VERSION 5.8 ;
BUSBITCHARS "[]" ;
DIVIDERCHAR "/" ;
UNITS
    DATABASE MICRONS 1000 ;
END UNITS

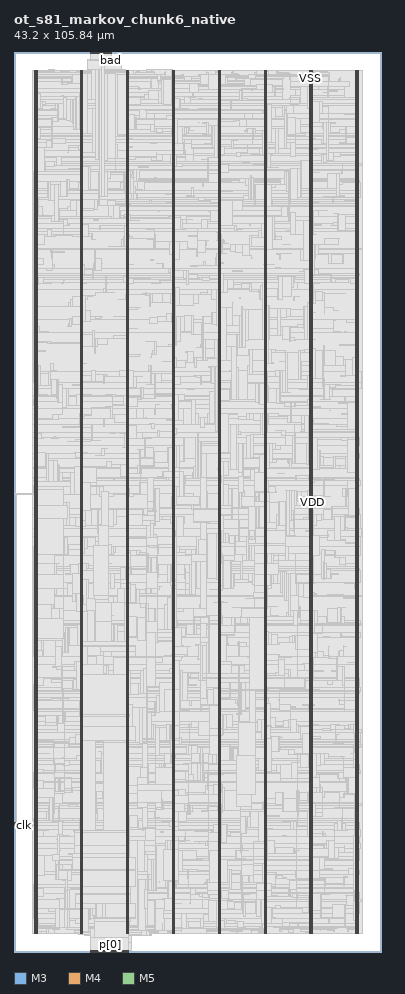
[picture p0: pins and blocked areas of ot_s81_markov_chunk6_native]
MACRO ot_s81_markov_chunk6_native
  FOREIGN ot_s81_markov_chunk6_native 0 0 ;
  CLASS BLOCK ;
  SIZE 43.2 BY 105.84 ;
  PIN bad
    DIRECTION OUTPUT ;
    USE SIGNAL ;
    PORT
      LAYER M3 ;
        RECT  11.448 105.696 11.466 105.84 ;
    END
  END bad
  PIN clk
    DIRECTION INPUT ;
    USE SIGNAL ;
    PORT
      LAYER M4 ;
        RECT  0 14.88 0.192 14.904 ;
    END
  END clk
  PIN p[0]
    DIRECTION INPUT ;
    USE SIGNAL ;
    PORT
      LAYER M3 ;
        RECT  11.304 0 11.322 0.144 ;
    END
  END p[0]
  PIN p[10]
    DIRECTION INPUT ;
    USE SIGNAL ;
    PORT
      LAYER M3 ;
        RECT  12.024 0 12.042 0.144 ;
    END
  END p[10]
  PIN p[11]
    DIRECTION INPUT ;
    USE SIGNAL ;
    PORT
      LAYER M5 ;
        RECT  12.048 0 12.072 0.192 ;
    END
  END p[11]
  PIN p[12]
    DIRECTION INPUT ;
    USE SIGNAL ;
    PORT
      LAYER M3 ;
        RECT  12.168 0 12.186 0.144 ;
    END
  END p[12]
  PIN p[13]
    DIRECTION INPUT ;
    USE SIGNAL ;
    PORT
      LAYER M5 ;
        RECT  12.192 0 12.216 0.192 ;
    END
  END p[13]
  PIN p[14]
    DIRECTION INPUT ;
    USE SIGNAL ;
    PORT
      LAYER M3 ;
        RECT  12.312 0 12.33 0.144 ;
    END
  END p[14]
  PIN p[15]
    DIRECTION INPUT ;
    USE SIGNAL ;
    PORT
      LAYER M5 ;
        RECT  12.336 0 12.36 0.192 ;
    END
  END p[15]
  PIN p[16]
    DIRECTION INPUT ;
    USE SIGNAL ;
    PORT
      LAYER M3 ;
        RECT  12.456 0 12.474 0.144 ;
    END
  END p[16]
  PIN p[17]
    DIRECTION INPUT ;
    USE SIGNAL ;
    PORT
      LAYER M5 ;
        RECT  12.48 0 12.504 0.192 ;
    END
  END p[17]
  PIN p[18]
    DIRECTION INPUT ;
    USE SIGNAL ;
    PORT
      LAYER M3 ;
        RECT  12.6 0 12.618 0.144 ;
    END
  END p[18]
  PIN p[19]
    DIRECTION INPUT ;
    USE SIGNAL ;
    PORT
      LAYER M5 ;
        RECT  12.624 0 12.648 0.192 ;
    END
  END p[19]
  PIN p[1]
    DIRECTION INPUT ;
    USE SIGNAL ;
    PORT
      LAYER M5 ;
        RECT  11.328 0 11.352 0.192 ;
    END
  END p[1]
  PIN p[20]
    DIRECTION INPUT ;
    USE SIGNAL ;
    PORT
      LAYER M3 ;
        RECT  12.744 0 12.762 0.144 ;
    END
  END p[20]
  PIN p[21]
    DIRECTION INPUT ;
    USE SIGNAL ;
    PORT
      LAYER M5 ;
        RECT  12.768 0 12.792 0.192 ;
    END
  END p[21]
  PIN p[22]
    DIRECTION INPUT ;
    USE SIGNAL ;
    PORT
      LAYER M3 ;
        RECT  12.888 0 12.906 0.144 ;
    END
  END p[22]
  PIN p[23]
    DIRECTION INPUT ;
    USE SIGNAL ;
    PORT
      LAYER M5 ;
        RECT  12.912 0 12.936 0.192 ;
    END
  END p[23]
  PIN p[24]
    DIRECTION INPUT ;
    USE SIGNAL ;
    PORT
      LAYER M3 ;
        RECT  13.032 0 13.05 0.144 ;
    END
  END p[24]
  PIN p[25]
    DIRECTION INPUT ;
    USE SIGNAL ;
    PORT
      LAYER M5 ;
        RECT  13.056 0 13.08 0.192 ;
    END
  END p[25]
  PIN p[26]
    DIRECTION INPUT ;
    USE SIGNAL ;
    PORT
      LAYER M3 ;
        RECT  13.176 0 13.194 0.144 ;
    END
  END p[26]
  PIN p[27]
    DIRECTION INPUT ;
    USE SIGNAL ;
    PORT
      LAYER M5 ;
        RECT  13.2 0 13.224 0.192 ;
    END
  END p[27]
  PIN p[28]
    DIRECTION INPUT ;
    USE SIGNAL ;
    PORT
      LAYER M3 ;
        RECT  13.32 0 13.338 0.144 ;
    END
  END p[28]
  PIN p[29]
    DIRECTION INPUT ;
    USE SIGNAL ;
    PORT
      LAYER M5 ;
        RECT  13.344 0 13.368 0.192 ;
    END
  END p[29]
  PIN p[2]
    DIRECTION INPUT ;
    USE SIGNAL ;
    PORT
      LAYER M3 ;
        RECT  11.448 0 11.466 0.144 ;
    END
  END p[2]
  PIN p[30]
    DIRECTION INPUT ;
    USE SIGNAL ;
    PORT
      LAYER M3 ;
        RECT  13.464 0 13.482 0.144 ;
    END
  END p[30]
  PIN p[31]
    DIRECTION INPUT ;
    USE SIGNAL ;
    PORT
      LAYER M5 ;
        RECT  13.488 0 13.512 0.192 ;
    END
  END p[31]
  PIN p[3]
    DIRECTION INPUT ;
    USE SIGNAL ;
    PORT
      LAYER M5 ;
        RECT  11.472 0 11.496 0.192 ;
    END
  END p[3]
  PIN p[4]
    DIRECTION INPUT ;
    USE SIGNAL ;
    PORT
      LAYER M3 ;
        RECT  11.592 0 11.61 0.144 ;
    END
  END p[4]
  PIN p[5]
    DIRECTION INPUT ;
    USE SIGNAL ;
    PORT
      LAYER M5 ;
        RECT  11.616 0 11.64 0.192 ;
    END
  END p[5]
  PIN p[6]
    DIRECTION INPUT ;
    USE SIGNAL ;
    PORT
      LAYER M3 ;
        RECT  11.736 0 11.754 0.144 ;
    END
  END p[6]
  PIN p[7]
    DIRECTION INPUT ;
    USE SIGNAL ;
    PORT
      LAYER M5 ;
        RECT  11.76 0 11.784 0.192 ;
    END
  END p[7]
  PIN p[8]
    DIRECTION INPUT ;
    USE SIGNAL ;
    PORT
      LAYER M3 ;
        RECT  11.88 0 11.898 0.144 ;
    END
  END p[8]
  PIN p[9]
    DIRECTION INPUT ;
    USE SIGNAL ;
    PORT
      LAYER M5 ;
        RECT  11.904 0 11.928 0.192 ;
    END
  END p[9]
  PIN rst_n
    DIRECTION INPUT ;
    USE SIGNAL ;
    PORT
      LAYER M4 ;
        RECT  0 15.024 0.192 15.048 ;
    END
  END rst_n
  PIN sum[0]
    DIRECTION INPUT ;
    USE SIGNAL ;
    PORT
      LAYER M3 ;
        RECT  9 0 9.018 0.144 ;
    END
  END sum[0]
  PIN sum[10]
    DIRECTION INPUT ;
    USE SIGNAL ;
    PORT
      LAYER M3 ;
        RECT  9.72 0 9.738 0.144 ;
    END
  END sum[10]
  PIN sum[11]
    DIRECTION INPUT ;
    USE SIGNAL ;
    PORT
      LAYER M5 ;
        RECT  9.744 0 9.768 0.192 ;
    END
  END sum[11]
  PIN sum[12]
    DIRECTION INPUT ;
    USE SIGNAL ;
    PORT
      LAYER M3 ;
        RECT  9.864 0 9.882 0.144 ;
    END
  END sum[12]
  PIN sum[13]
    DIRECTION INPUT ;
    USE SIGNAL ;
    PORT
      LAYER M5 ;
        RECT  9.888 0 9.912 0.192 ;
    END
  END sum[13]
  PIN sum[14]
    DIRECTION INPUT ;
    USE SIGNAL ;
    PORT
      LAYER M3 ;
        RECT  10.008 0 10.026 0.144 ;
    END
  END sum[14]
  PIN sum[15]
    DIRECTION INPUT ;
    USE SIGNAL ;
    PORT
      LAYER M5 ;
        RECT  10.032 0 10.056 0.192 ;
    END
  END sum[15]
  PIN sum[16]
    DIRECTION INPUT ;
    USE SIGNAL ;
    PORT
      LAYER M3 ;
        RECT  10.152 0 10.17 0.144 ;
    END
  END sum[16]
  PIN sum[17]
    DIRECTION INPUT ;
    USE SIGNAL ;
    PORT
      LAYER M5 ;
        RECT  10.176 0 10.2 0.192 ;
    END
  END sum[17]
  PIN sum[18]
    DIRECTION INPUT ;
    USE SIGNAL ;
    PORT
      LAYER M3 ;
        RECT  10.296 0 10.314 0.144 ;
    END
  END sum[18]
  PIN sum[19]
    DIRECTION INPUT ;
    USE SIGNAL ;
    PORT
      LAYER M5 ;
        RECT  10.32 0 10.344 0.192 ;
    END
  END sum[19]
  PIN sum[1]
    DIRECTION INPUT ;
    USE SIGNAL ;
    PORT
      LAYER M5 ;
        RECT  9.024 0 9.048 0.192 ;
    END
  END sum[1]
  PIN sum[20]
    DIRECTION INPUT ;
    USE SIGNAL ;
    PORT
      LAYER M3 ;
        RECT  10.44 0 10.458 0.144 ;
    END
  END sum[20]
  PIN sum[21]
    DIRECTION INPUT ;
    USE SIGNAL ;
    PORT
      LAYER M5 ;
        RECT  10.464 0 10.488 0.192 ;
    END
  END sum[21]
  PIN sum[22]
    DIRECTION INPUT ;
    USE SIGNAL ;
    PORT
      LAYER M3 ;
        RECT  10.584 0 10.602 0.144 ;
    END
  END sum[22]
  PIN sum[23]
    DIRECTION INPUT ;
    USE SIGNAL ;
    PORT
      LAYER M5 ;
        RECT  10.608 0 10.632 0.192 ;
    END
  END sum[23]
  PIN sum[24]
    DIRECTION INPUT ;
    USE SIGNAL ;
    PORT
      LAYER M3 ;
        RECT  10.728 0 10.746 0.144 ;
    END
  END sum[24]
  PIN sum[25]
    DIRECTION INPUT ;
    USE SIGNAL ;
    PORT
      LAYER M5 ;
        RECT  10.752 0 10.776 0.192 ;
    END
  END sum[25]
  PIN sum[26]
    DIRECTION INPUT ;
    USE SIGNAL ;
    PORT
      LAYER M3 ;
        RECT  10.872 0 10.89 0.144 ;
    END
  END sum[26]
  PIN sum[27]
    DIRECTION INPUT ;
    USE SIGNAL ;
    PORT
      LAYER M5 ;
        RECT  10.896 0 10.92 0.192 ;
    END
  END sum[27]
  PIN sum[28]
    DIRECTION INPUT ;
    USE SIGNAL ;
    PORT
      LAYER M3 ;
        RECT  11.016 0 11.034 0.144 ;
    END
  END sum[28]
  PIN sum[29]
    DIRECTION INPUT ;
    USE SIGNAL ;
    PORT
      LAYER M5 ;
        RECT  11.04 0 11.064 0.192 ;
    END
  END sum[29]
  PIN sum[2]
    DIRECTION INPUT ;
    USE SIGNAL ;
    PORT
      LAYER M3 ;
        RECT  9.144 0 9.162 0.144 ;
    END
  END sum[2]
  PIN sum[30]
    DIRECTION INPUT ;
    USE SIGNAL ;
    PORT
      LAYER M3 ;
        RECT  11.16 0 11.178 0.144 ;
    END
  END sum[30]
  PIN sum[31]
    DIRECTION INPUT ;
    USE SIGNAL ;
    PORT
      LAYER M5 ;
        RECT  11.184 0 11.208 0.192 ;
    END
  END sum[31]
  PIN sum[3]
    DIRECTION INPUT ;
    USE SIGNAL ;
    PORT
      LAYER M5 ;
        RECT  9.168 0 9.192 0.192 ;
    END
  END sum[3]
  PIN sum[4]
    DIRECTION INPUT ;
    USE SIGNAL ;
    PORT
      LAYER M3 ;
        RECT  9.288 0 9.306 0.144 ;
    END
  END sum[4]
  PIN sum[5]
    DIRECTION INPUT ;
    USE SIGNAL ;
    PORT
      LAYER M5 ;
        RECT  9.312 0 9.336 0.192 ;
    END
  END sum[5]
  PIN sum[6]
    DIRECTION INPUT ;
    USE SIGNAL ;
    PORT
      LAYER M3 ;
        RECT  9.432 0 9.45 0.144 ;
    END
  END sum[6]
  PIN sum[7]
    DIRECTION INPUT ;
    USE SIGNAL ;
    PORT
      LAYER M5 ;
        RECT  9.456 0 9.48 0.192 ;
    END
  END sum[7]
  PIN sum[8]
    DIRECTION INPUT ;
    USE SIGNAL ;
    PORT
      LAYER M3 ;
        RECT  9.576 0 9.594 0.144 ;
    END
  END sum[8]
  PIN sum[9]
    DIRECTION INPUT ;
    USE SIGNAL ;
    PORT
      LAYER M5 ;
        RECT  9.6 0 9.624 0.192 ;
    END
  END sum[9]
  PIN vin
    DIRECTION INPUT ;
    USE SIGNAL ;
    PORT
      LAYER M4 ;
        RECT  0 15.168 0.192 15.192 ;
    END
  END vin
  PIN vout
    DIRECTION OUTPUT ;
    USE SIGNAL ;
    PORT
      LAYER M3 ;
        RECT  11.304 105.696 11.322 105.84 ;
    END
  END vout
  PIN y[0]
    DIRECTION OUTPUT ;
    USE SIGNAL ;
    PORT
      LAYER M3 ;
        RECT  9 105.696 9.018 105.84 ;
    END
  END y[0]
  PIN y[10]
    DIRECTION OUTPUT ;
    USE SIGNAL ;
    PORT
      LAYER M3 ;
        RECT  9.72 105.696 9.738 105.84 ;
    END
  END y[10]
  PIN y[11]
    DIRECTION OUTPUT ;
    USE SIGNAL ;
    PORT
      LAYER M5 ;
        RECT  9.744 105.648 9.768 105.84 ;
    END
  END y[11]
  PIN y[12]
    DIRECTION OUTPUT ;
    USE SIGNAL ;
    PORT
      LAYER M3 ;
        RECT  9.864 105.696 9.882 105.84 ;
    END
  END y[12]
  PIN y[13]
    DIRECTION OUTPUT ;
    USE SIGNAL ;
    PORT
      LAYER M5 ;
        RECT  9.888 105.648 9.912 105.84 ;
    END
  END y[13]
  PIN y[14]
    DIRECTION OUTPUT ;
    USE SIGNAL ;
    PORT
      LAYER M3 ;
        RECT  10.008 105.696 10.026 105.84 ;
    END
  END y[14]
  PIN y[15]
    DIRECTION OUTPUT ;
    USE SIGNAL ;
    PORT
      LAYER M5 ;
        RECT  10.032 105.648 10.056 105.84 ;
    END
  END y[15]
  PIN y[16]
    DIRECTION OUTPUT ;
    USE SIGNAL ;
    PORT
      LAYER M3 ;
        RECT  10.152 105.696 10.17 105.84 ;
    END
  END y[16]
  PIN y[17]
    DIRECTION OUTPUT ;
    USE SIGNAL ;
    PORT
      LAYER M5 ;
        RECT  10.176 105.648 10.2 105.84 ;
    END
  END y[17]
  PIN y[18]
    DIRECTION OUTPUT ;
    USE SIGNAL ;
    PORT
      LAYER M3 ;
        RECT  10.296 105.696 10.314 105.84 ;
    END
  END y[18]
  PIN y[19]
    DIRECTION OUTPUT ;
    USE SIGNAL ;
    PORT
      LAYER M5 ;
        RECT  10.32 105.648 10.344 105.84 ;
    END
  END y[19]
  PIN y[1]
    DIRECTION OUTPUT ;
    USE SIGNAL ;
    PORT
      LAYER M5 ;
        RECT  9.024 105.648 9.048 105.84 ;
    END
  END y[1]
  PIN y[20]
    DIRECTION OUTPUT ;
    USE SIGNAL ;
    PORT
      LAYER M3 ;
        RECT  10.44 105.696 10.458 105.84 ;
    END
  END y[20]
  PIN y[21]
    DIRECTION OUTPUT ;
    USE SIGNAL ;
    PORT
      LAYER M5 ;
        RECT  10.464 105.648 10.488 105.84 ;
    END
  END y[21]
  PIN y[22]
    DIRECTION OUTPUT ;
    USE SIGNAL ;
    PORT
      LAYER M3 ;
        RECT  10.584 105.696 10.602 105.84 ;
    END
  END y[22]
  PIN y[23]
    DIRECTION OUTPUT ;
    USE SIGNAL ;
    PORT
      LAYER M5 ;
        RECT  10.608 105.648 10.632 105.84 ;
    END
  END y[23]
  PIN y[24]
    DIRECTION OUTPUT ;
    USE SIGNAL ;
    PORT
      LAYER M3 ;
        RECT  10.728 105.696 10.746 105.84 ;
    END
  END y[24]
  PIN y[25]
    DIRECTION OUTPUT ;
    USE SIGNAL ;
    PORT
      LAYER M5 ;
        RECT  10.752 105.648 10.776 105.84 ;
    END
  END y[25]
  PIN y[26]
    DIRECTION OUTPUT ;
    USE SIGNAL ;
    PORT
      LAYER M3 ;
        RECT  10.872 105.696 10.89 105.84 ;
    END
  END y[26]
  PIN y[27]
    DIRECTION OUTPUT ;
    USE SIGNAL ;
    PORT
      LAYER M5 ;
        RECT  10.896 105.648 10.92 105.84 ;
    END
  END y[27]
  PIN y[28]
    DIRECTION OUTPUT ;
    USE SIGNAL ;
    PORT
      LAYER M3 ;
        RECT  11.016 105.696 11.034 105.84 ;
    END
  END y[28]
  PIN y[29]
    DIRECTION OUTPUT ;
    USE SIGNAL ;
    PORT
      LAYER M5 ;
        RECT  11.04 105.648 11.064 105.84 ;
    END
  END y[29]
  PIN y[2]
    DIRECTION OUTPUT ;
    USE SIGNAL ;
    PORT
      LAYER M3 ;
        RECT  9.144 105.696 9.162 105.84 ;
    END
  END y[2]
  PIN y[30]
    DIRECTION OUTPUT ;
    USE SIGNAL ;
    PORT
      LAYER M3 ;
        RECT  11.16 105.696 11.178 105.84 ;
    END
  END y[30]
  PIN y[31]
    DIRECTION OUTPUT ;
    USE SIGNAL ;
    PORT
      LAYER M5 ;
        RECT  11.184 105.648 11.208 105.84 ;
    END
  END y[31]
  PIN y[3]
    DIRECTION OUTPUT ;
    USE SIGNAL ;
    PORT
      LAYER M5 ;
        RECT  9.168 105.648 9.192 105.84 ;
    END
  END y[3]
  PIN y[4]
    DIRECTION OUTPUT ;
    USE SIGNAL ;
    PORT
      LAYER M3 ;
        RECT  9.288 105.696 9.306 105.84 ;
    END
  END y[4]
  PIN y[5]
    DIRECTION OUTPUT ;
    USE SIGNAL ;
    PORT
      LAYER M5 ;
        RECT  9.312 105.648 9.336 105.84 ;
    END
  END y[5]
  PIN y[6]
    DIRECTION OUTPUT ;
    USE SIGNAL ;
    PORT
      LAYER M3 ;
        RECT  9.432 105.696 9.45 105.84 ;
    END
  END y[6]
  PIN y[7]
    DIRECTION OUTPUT ;
    USE SIGNAL ;
    PORT
      LAYER M5 ;
        RECT  9.456 105.648 9.48 105.84 ;
    END
  END y[7]
  PIN y[8]
    DIRECTION OUTPUT ;
    USE SIGNAL ;
    PORT
      LAYER M3 ;
        RECT  9.576 105.696 9.594 105.84 ;
    END
  END y[8]
  PIN y[9]
    DIRECTION OUTPUT ;
    USE SIGNAL ;
    PORT
      LAYER M5 ;
        RECT  9.6 105.648 9.624 105.84 ;
    END
  END y[9]
  PIN VDD
    DIRECTION INOUT ;
    USE POWER ;
    PORT
      LAYER M5 ;
        RECT  40.392 2.151 40.512 103.689 ;
        RECT  34.992 2.151 35.112 103.689 ;
        RECT  29.592 2.151 29.712 103.689 ;
        RECT  24.192 2.151 24.312 103.689 ;
        RECT  18.792 2.151 18.912 103.689 ;
        RECT  13.392 2.151 13.512 103.689 ;
        RECT  7.992 2.151 8.112 103.689 ;
        RECT  2.592 2.151 2.712 103.689 ;
    END
  END VDD
  PIN VSS
    DIRECTION INOUT ;
    USE GROUND ;
    PORT
      LAYER M5 ;
        RECT  40.2 2.137 40.32 103.703 ;
        RECT  34.8 2.137 34.92 103.703 ;
        RECT  29.4 2.137 29.52 103.703 ;
        RECT  24 2.137 24.12 103.703 ;
        RECT  18.6 2.137 18.72 103.703 ;
        RECT  13.2 2.137 13.32 103.703 ;
        RECT  7.8 2.137 7.92 103.703 ;
        RECT  2.4 2.137 2.52 103.703 ;
    END
  END VSS
  # OT_OBS_CLOSED layer=M5 d_um=1.536 added=411
  OBS
    LAYER RVTN ;
     RECT  2.16 2.16 41.04 2.295 ;
     RECT  2.16 2.565 41.04 2.835 ;
     RECT  2.16 3.105 41.04 3.375 ;
     RECT  2.16 3.645 41.04 3.915 ;
     RECT  2.16 4.185 41.04 4.455 ;
     RECT  2.16 4.725 41.04 4.995 ;
     RECT  2.16 5.265 41.04 5.535 ;
     RECT  2.16 5.805 41.04 6.075 ;
     RECT  2.16 6.345 41.04 6.615 ;
     RECT  2.16 6.885 41.04 7.155 ;
     RECT  2.16 7.425 41.04 7.695 ;
     RECT  2.16 7.965 41.04 8.235 ;
     RECT  2.16 8.505 41.04 8.775 ;
     RECT  2.16 9.045 41.04 9.315 ;
     RECT  2.16 9.585 41.04 9.855 ;
     RECT  2.16 10.125 41.04 10.395 ;
     RECT  2.16 10.665 41.04 10.935 ;
     RECT  2.16 11.205 41.04 11.475 ;
     RECT  2.16 11.745 41.04 12.015 ;
     RECT  2.16 12.285 41.04 12.555 ;
     RECT  2.16 12.825 41.04 13.095 ;
     RECT  2.16 13.365 41.04 13.635 ;
     RECT  2.16 13.905 41.04 14.175 ;
     RECT  2.16 14.445 41.04 14.715 ;
     RECT  2.16 14.985 41.04 15.255 ;
     RECT  2.16 15.525 41.04 15.795 ;
     RECT  2.16 16.065 41.04 16.335 ;
     RECT  2.16 16.605 41.04 16.875 ;
     RECT  2.16 17.145 41.04 17.415 ;
     RECT  2.16 17.685 41.04 17.955 ;
     RECT  2.16 18.225 41.04 18.495 ;
     RECT  2.16 18.765 41.04 19.035 ;
     RECT  2.16 19.305 41.04 19.575 ;
     RECT  2.16 19.845 41.04 20.115 ;
     RECT  2.16 20.385 41.04 20.655 ;
     RECT  2.16 20.925 41.04 21.195 ;
     RECT  2.16 21.465 41.04 21.735 ;
     RECT  2.16 22.005 41.04 22.275 ;
     RECT  2.16 22.545 41.04 22.815 ;
     RECT  2.16 23.085 41.04 23.355 ;
     RECT  2.16 23.625 41.04 23.895 ;
     RECT  2.16 24.165 41.04 24.435 ;
     RECT  2.16 24.705 41.04 24.975 ;
     RECT  2.16 25.245 41.04 25.515 ;
     RECT  2.16 25.785 41.04 26.055 ;
     RECT  2.16 26.325 41.04 26.595 ;
     RECT  2.16 26.865 41.04 27.135 ;
     RECT  2.16 27.405 41.04 27.675 ;
     RECT  2.16 27.945 41.04 28.215 ;
     RECT  2.16 28.485 41.04 28.755 ;
     RECT  2.16 29.025 41.04 29.295 ;
     RECT  2.16 29.565 41.04 29.835 ;
     RECT  2.16 30.105 41.04 30.375 ;
     RECT  2.16 30.645 41.04 30.915 ;
     RECT  2.16 31.185 41.04 31.455 ;
     RECT  2.16 31.725 41.04 31.995 ;
     RECT  2.16 32.265 41.04 32.535 ;
     RECT  2.16 32.805 41.04 33.075 ;
     RECT  2.16 33.345 41.04 33.615 ;
     RECT  2.16 33.885 41.04 34.155 ;
     RECT  2.16 34.425 41.04 34.695 ;
     RECT  2.16 34.965 41.04 35.235 ;
     RECT  2.16 35.505 41.04 35.775 ;
     RECT  2.16 36.045 41.04 36.315 ;
     RECT  2.16 36.585 41.04 36.855 ;
     RECT  2.16 37.125 41.04 37.395 ;
     RECT  2.16 37.665 41.04 37.935 ;
     RECT  2.16 38.205 41.04 38.475 ;
     RECT  2.16 38.745 41.04 39.015 ;
     RECT  2.16 39.285 41.04 39.555 ;
     RECT  2.16 39.825 41.04 40.095 ;
     RECT  2.16 40.365 41.04 40.635 ;
     RECT  2.16 40.905 41.04 41.175 ;
     RECT  2.16 41.445 41.04 41.715 ;
     RECT  2.16 41.985 41.04 42.255 ;
     RECT  2.16 42.525 41.04 42.795 ;
     RECT  2.16 43.065 41.04 43.335 ;
     RECT  2.16 43.605 41.04 43.875 ;
     RECT  2.16 44.145 41.04 44.415 ;
     RECT  2.16 44.685 41.04 44.955 ;
     RECT  2.16 45.225 41.04 45.495 ;
     RECT  2.16 45.765 41.04 46.035 ;
     RECT  2.16 46.305 41.04 46.575 ;
     RECT  2.16 46.845 41.04 47.115 ;
     RECT  2.16 47.385 41.04 47.655 ;
     RECT  2.16 47.925 41.04 48.195 ;
     RECT  2.16 48.465 41.04 48.735 ;
     RECT  2.16 49.005 41.04 49.275 ;
     RECT  2.16 49.545 41.04 49.815 ;
     RECT  2.16 50.085 41.04 50.355 ;
     RECT  2.16 50.625 41.04 50.895 ;
     RECT  2.16 51.165 41.04 51.435 ;
     RECT  2.16 51.705 41.04 51.975 ;
     RECT  2.16 52.245 41.04 52.515 ;
     RECT  2.16 52.785 41.04 53.055 ;
     RECT  2.16 53.325 41.04 53.595 ;
     RECT  2.16 53.865 41.04 54.135 ;
     RECT  2.16 54.405 41.04 54.675 ;
     RECT  2.16 54.945 41.04 55.215 ;
     RECT  2.16 55.485 41.04 55.755 ;
     RECT  2.16 56.025 41.04 56.295 ;
     RECT  2.16 56.565 41.04 56.835 ;
     RECT  2.16 57.105 41.04 57.375 ;
     RECT  2.16 57.645 41.04 57.915 ;
     RECT  2.16 58.185 41.04 58.455 ;
     RECT  2.16 58.725 41.04 58.995 ;
     RECT  2.16 59.265 41.04 59.535 ;
     RECT  2.16 59.805 41.04 60.075 ;
     RECT  2.16 60.345 41.04 60.615 ;
     RECT  2.16 60.885 41.04 61.155 ;
     RECT  2.16 61.425 41.04 61.695 ;
     RECT  2.16 61.965 41.04 62.235 ;
     RECT  2.16 62.505 41.04 62.775 ;
     RECT  2.16 63.045 41.04 63.315 ;
     RECT  2.16 63.585 41.04 63.855 ;
     RECT  2.16 64.125 41.04 64.395 ;
     RECT  2.16 64.665 41.04 64.935 ;
     RECT  2.16 65.205 41.04 65.475 ;
     RECT  2.16 65.745 41.04 66.015 ;
     RECT  2.16 66.285 41.04 66.555 ;
     RECT  2.16 66.825 41.04 67.095 ;
     RECT  2.16 67.365 41.04 67.635 ;
     RECT  2.16 67.905 41.04 68.175 ;
     RECT  2.16 68.445 41.04 68.715 ;
     RECT  2.16 68.985 41.04 69.255 ;
     RECT  2.16 69.525 41.04 69.795 ;
     RECT  2.16 70.065 41.04 70.335 ;
     RECT  2.16 70.605 41.04 70.875 ;
     RECT  2.16 71.145 41.04 71.415 ;
     RECT  2.16 71.685 41.04 71.955 ;
     RECT  2.16 72.225 41.04 72.495 ;
     RECT  2.16 72.765 41.04 73.035 ;
     RECT  2.16 73.305 41.04 73.575 ;
     RECT  2.16 73.845 41.04 74.115 ;
     RECT  2.16 74.385 41.04 74.655 ;
     RECT  2.16 74.925 41.04 75.195 ;
     RECT  2.16 75.465 41.04 75.735 ;
     RECT  2.16 76.005 41.04 76.275 ;
     RECT  2.16 76.545 41.04 76.815 ;
     RECT  2.16 77.085 41.04 77.355 ;
     RECT  2.16 77.625 41.04 77.895 ;
     RECT  2.16 78.165 41.04 78.435 ;
     RECT  2.16 78.705 41.04 78.975 ;
     RECT  2.16 79.245 41.04 79.515 ;
     RECT  2.16 79.785 41.04 80.055 ;
     RECT  2.16 80.325 41.04 80.595 ;
     RECT  2.16 80.865 41.04 81.135 ;
     RECT  2.16 81.405 41.04 81.675 ;
     RECT  2.16 81.945 41.04 82.215 ;
     RECT  2.16 82.485 41.04 82.755 ;
     RECT  2.16 83.025 41.04 83.295 ;
     RECT  2.16 83.565 41.04 83.835 ;
     RECT  2.16 84.105 41.04 84.375 ;
     RECT  2.16 84.645 41.04 84.915 ;
     RECT  2.16 85.185 41.04 85.455 ;
     RECT  2.16 85.725 41.04 85.995 ;
     RECT  2.16 86.265 41.04 86.535 ;
     RECT  2.16 86.805 41.04 87.075 ;
     RECT  2.16 87.345 41.04 87.615 ;
     RECT  2.16 87.885 41.04 88.155 ;
     RECT  2.16 88.425 41.04 88.695 ;
     RECT  2.16 88.965 41.04 89.235 ;
     RECT  2.16 89.505 41.04 89.775 ;
     RECT  2.16 90.045 41.04 90.315 ;
     RECT  2.16 90.585 41.04 90.855 ;
     RECT  2.16 91.125 41.04 91.395 ;
     RECT  2.16 91.665 41.04 91.935 ;
     RECT  2.16 92.205 41.04 92.475 ;
     RECT  2.16 92.745 41.04 93.015 ;
     RECT  2.16 93.285 41.04 93.555 ;
     RECT  2.16 93.825 41.04 94.095 ;
     RECT  2.16 94.365 41.04 94.635 ;
     RECT  2.16 94.905 41.04 95.175 ;
     RECT  2.16 95.445 41.04 95.715 ;
     RECT  2.16 95.985 41.04 96.255 ;
     RECT  2.16 96.525 41.04 96.795 ;
     RECT  2.16 97.065 41.04 97.335 ;
     RECT  2.16 97.605 41.04 97.875 ;
     RECT  2.16 98.145 41.04 98.415 ;
     RECT  2.16 98.685 41.04 98.955 ;
     RECT  2.16 99.225 41.04 99.495 ;
     RECT  2.16 99.765 41.04 100.035 ;
     RECT  2.16 100.305 41.04 100.575 ;
     RECT  2.16 100.845 41.04 101.115 ;
     RECT  2.16 101.385 41.04 101.655 ;
     RECT  2.16 101.925 41.04 102.195 ;
     RECT  2.16 102.465 41.04 102.735 ;
     RECT  2.16 103.005 41.04 103.275 ;
     RECT  2.16 103.545 41.04 103.68 ;
    LAYER RVTP ;
     RECT  2.16 2.295 41.04 2.565 ;
     RECT  2.16 2.835 41.04 3.105 ;
     RECT  2.16 3.375 41.04 3.645 ;
     RECT  2.16 3.915 41.04 4.185 ;
     RECT  2.16 4.455 41.04 4.725 ;
     RECT  2.16 4.995 41.04 5.265 ;
     RECT  2.16 5.535 41.04 5.805 ;
     RECT  2.16 6.075 41.04 6.345 ;
     RECT  2.16 6.615 41.04 6.885 ;
     RECT  2.16 7.155 41.04 7.425 ;
     RECT  2.16 7.695 41.04 7.965 ;
     RECT  2.16 8.235 41.04 8.505 ;
     RECT  2.16 8.775 41.04 9.045 ;
     RECT  2.16 9.315 41.04 9.585 ;
     RECT  2.16 9.855 41.04 10.125 ;
     RECT  2.16 10.395 41.04 10.665 ;
     RECT  2.16 10.935 41.04 11.205 ;
     RECT  2.16 11.475 41.04 11.745 ;
     RECT  2.16 12.015 41.04 12.285 ;
     RECT  2.16 12.555 41.04 12.825 ;
     RECT  2.16 13.095 41.04 13.365 ;
     RECT  2.16 13.635 41.04 13.905 ;
     RECT  2.16 14.175 41.04 14.445 ;
     RECT  2.16 14.715 41.04 14.985 ;
     RECT  2.16 15.255 41.04 15.525 ;
     RECT  2.16 15.795 41.04 16.065 ;
     RECT  2.16 16.335 41.04 16.605 ;
     RECT  2.16 16.875 41.04 17.145 ;
     RECT  2.16 17.415 41.04 17.685 ;
     RECT  2.16 17.955 41.04 18.225 ;
     RECT  2.16 18.495 41.04 18.765 ;
     RECT  2.16 19.035 41.04 19.305 ;
     RECT  2.16 19.575 41.04 19.845 ;
     RECT  2.16 20.115 41.04 20.385 ;
     RECT  2.16 20.655 41.04 20.925 ;
     RECT  2.16 21.195 41.04 21.465 ;
     RECT  2.16 21.735 41.04 22.005 ;
     RECT  2.16 22.275 41.04 22.545 ;
     RECT  2.16 22.815 41.04 23.085 ;
     RECT  2.16 23.355 41.04 23.625 ;
     RECT  2.16 23.895 41.04 24.165 ;
     RECT  2.16 24.435 41.04 24.705 ;
     RECT  2.16 24.975 41.04 25.245 ;
     RECT  2.16 25.515 41.04 25.785 ;
     RECT  2.16 26.055 41.04 26.325 ;
     RECT  2.16 26.595 41.04 26.865 ;
     RECT  2.16 27.135 41.04 27.405 ;
     RECT  2.16 27.675 41.04 27.945 ;
     RECT  2.16 28.215 41.04 28.485 ;
     RECT  2.16 28.755 41.04 29.025 ;
     RECT  2.16 29.295 41.04 29.565 ;
     RECT  2.16 29.835 41.04 30.105 ;
     RECT  2.16 30.375 41.04 30.645 ;
     RECT  2.16 30.915 41.04 31.185 ;
     RECT  2.16 31.455 41.04 31.725 ;
     RECT  2.16 31.995 41.04 32.265 ;
     RECT  2.16 32.535 41.04 32.805 ;
     RECT  2.16 33.075 41.04 33.345 ;
     RECT  2.16 33.615 41.04 33.885 ;
     RECT  2.16 34.155 41.04 34.425 ;
     RECT  2.16 34.695 41.04 34.965 ;
     RECT  2.16 35.235 41.04 35.505 ;
     RECT  2.16 35.775 41.04 36.045 ;
     RECT  2.16 36.315 41.04 36.585 ;
     RECT  2.16 36.855 41.04 37.125 ;
     RECT  2.16 37.395 41.04 37.665 ;
     RECT  2.16 37.935 41.04 38.205 ;
     RECT  2.16 38.475 41.04 38.745 ;
     RECT  2.16 39.015 41.04 39.285 ;
     RECT  2.16 39.555 41.04 39.825 ;
     RECT  2.16 40.095 41.04 40.365 ;
     RECT  2.16 40.635 41.04 40.905 ;
     RECT  2.16 41.175 41.04 41.445 ;
     RECT  2.16 41.715 41.04 41.985 ;
     RECT  2.16 42.255 41.04 42.525 ;
     RECT  2.16 42.795 41.04 43.065 ;
     RECT  2.16 43.335 41.04 43.605 ;
     RECT  2.16 43.875 41.04 44.145 ;
     RECT  2.16 44.415 41.04 44.685 ;
     RECT  2.16 44.955 41.04 45.225 ;
     RECT  2.16 45.495 41.04 45.765 ;
     RECT  2.16 46.035 41.04 46.305 ;
     RECT  2.16 46.575 41.04 46.845 ;
     RECT  2.16 47.115 41.04 47.385 ;
     RECT  2.16 47.655 41.04 47.925 ;
     RECT  2.16 48.195 41.04 48.465 ;
     RECT  2.16 48.735 41.04 49.005 ;
     RECT  2.16 49.275 41.04 49.545 ;
     RECT  2.16 49.815 41.04 50.085 ;
     RECT  2.16 50.355 41.04 50.625 ;
     RECT  2.16 50.895 41.04 51.165 ;
     RECT  2.16 51.435 41.04 51.705 ;
     RECT  2.16 51.975 41.04 52.245 ;
     RECT  2.16 52.515 41.04 52.785 ;
     RECT  2.16 53.055 41.04 53.325 ;
     RECT  2.16 53.595 41.04 53.865 ;
     RECT  2.16 54.135 41.04 54.405 ;
     RECT  2.16 54.675 41.04 54.945 ;
     RECT  2.16 55.215 41.04 55.485 ;
     RECT  2.16 55.755 41.04 56.025 ;
     RECT  2.16 56.295 41.04 56.565 ;
     RECT  2.16 56.835 41.04 57.105 ;
     RECT  2.16 57.375 41.04 57.645 ;
     RECT  2.16 57.915 41.04 58.185 ;
     RECT  2.16 58.455 41.04 58.725 ;
     RECT  2.16 58.995 41.04 59.265 ;
     RECT  2.16 59.535 41.04 59.805 ;
     RECT  2.16 60.075 41.04 60.345 ;
     RECT  2.16 60.615 41.04 60.885 ;
     RECT  2.16 61.155 41.04 61.425 ;
     RECT  2.16 61.695 41.04 61.965 ;
     RECT  2.16 62.235 41.04 62.505 ;
     RECT  2.16 62.775 41.04 63.045 ;
     RECT  2.16 63.315 41.04 63.585 ;
     RECT  2.16 63.855 41.04 64.125 ;
     RECT  2.16 64.395 41.04 64.665 ;
     RECT  2.16 64.935 41.04 65.205 ;
     RECT  2.16 65.475 41.04 65.745 ;
     RECT  2.16 66.015 41.04 66.285 ;
     RECT  2.16 66.555 41.04 66.825 ;
     RECT  2.16 67.095 41.04 67.365 ;
     RECT  2.16 67.635 41.04 67.905 ;
     RECT  2.16 68.175 41.04 68.445 ;
     RECT  2.16 68.715 41.04 68.985 ;
     RECT  2.16 69.255 41.04 69.525 ;
     RECT  2.16 69.795 41.04 70.065 ;
     RECT  2.16 70.335 41.04 70.605 ;
     RECT  2.16 70.875 41.04 71.145 ;
     RECT  2.16 71.415 41.04 71.685 ;
     RECT  2.16 71.955 41.04 72.225 ;
     RECT  2.16 72.495 41.04 72.765 ;
     RECT  2.16 73.035 41.04 73.305 ;
     RECT  2.16 73.575 41.04 73.845 ;
     RECT  2.16 74.115 41.04 74.385 ;
     RECT  2.16 74.655 41.04 74.925 ;
     RECT  2.16 75.195 41.04 75.465 ;
     RECT  2.16 75.735 41.04 76.005 ;
     RECT  2.16 76.275 41.04 76.545 ;
     RECT  2.16 76.815 41.04 77.085 ;
     RECT  2.16 77.355 41.04 77.625 ;
     RECT  2.16 77.895 41.04 78.165 ;
     RECT  2.16 78.435 41.04 78.705 ;
     RECT  2.16 78.975 41.04 79.245 ;
     RECT  2.16 79.515 41.04 79.785 ;
     RECT  2.16 80.055 41.04 80.325 ;
     RECT  2.16 80.595 41.04 80.865 ;
     RECT  2.16 81.135 41.04 81.405 ;
     RECT  2.16 81.675 41.04 81.945 ;
     RECT  2.16 82.215 41.04 82.485 ;
     RECT  2.16 82.755 41.04 83.025 ;
     RECT  2.16 83.295 41.04 83.565 ;
     RECT  2.16 83.835 41.04 84.105 ;
     RECT  2.16 84.375 41.04 84.645 ;
     RECT  2.16 84.915 41.04 85.185 ;
     RECT  2.16 85.455 41.04 85.725 ;
     RECT  2.16 85.995 41.04 86.265 ;
     RECT  2.16 86.535 41.04 86.805 ;
     RECT  2.16 87.075 41.04 87.345 ;
     RECT  2.16 87.615 41.04 87.885 ;
     RECT  2.16 88.155 41.04 88.425 ;
     RECT  2.16 88.695 41.04 88.965 ;
     RECT  2.16 89.235 41.04 89.505 ;
     RECT  2.16 89.775 41.04 90.045 ;
     RECT  2.16 90.315 41.04 90.585 ;
     RECT  2.16 90.855 41.04 91.125 ;
     RECT  2.16 91.395 41.04 91.665 ;
     RECT  2.16 91.935 41.04 92.205 ;
     RECT  2.16 92.475 41.04 92.745 ;
     RECT  2.16 93.015 41.04 93.285 ;
     RECT  2.16 93.555 41.04 93.825 ;
     RECT  2.16 94.095 41.04 94.365 ;
     RECT  2.16 94.635 41.04 94.905 ;
     RECT  2.16 95.175 41.04 95.445 ;
     RECT  2.16 95.715 41.04 95.985 ;
     RECT  2.16 96.255 41.04 96.525 ;
     RECT  2.16 96.795 41.04 97.065 ;
     RECT  2.16 97.335 41.04 97.605 ;
     RECT  2.16 97.875 41.04 98.145 ;
     RECT  2.16 98.415 41.04 98.685 ;
     RECT  2.16 98.955 41.04 99.225 ;
     RECT  2.16 99.495 41.04 99.765 ;
     RECT  2.16 100.035 41.04 100.305 ;
     RECT  2.16 100.575 41.04 100.845 ;
     RECT  2.16 101.115 41.04 101.385 ;
     RECT  2.16 101.655 41.04 101.925 ;
     RECT  2.16 102.195 41.04 102.465 ;
     RECT  2.16 102.735 41.04 103.005 ;
     RECT  2.16 103.275 41.04 103.545 ;
    LAYER M1 ;
     RECT  2.16 2.151 41.04 103.689 ;
    LAYER M2 ;
     RECT  2.16 2.151 4.027 103.689 ;
     RECT  4.027 2.151 4.775 103.734 ;
     RECT  4.775 2.151 7.591 103.689 ;
     RECT  7.591 2.106 8.023 103.689 ;
     RECT  8.023 2.034 8.275 103.689 ;
     RECT  8.275 1.962 9.167 103.689 ;
     RECT  9.167 2.07 9.311 103.689 ;
     RECT  9.139 104.796 9.355 104.814 ;
     RECT  9.311 2.106 9.607 103.689 ;
     RECT  9.715 1.152 9.751 1.17 ;
     RECT  9.607 2.106 9.887 103.77 ;
     RECT  9.751 1.152 9.895 1.242 ;
     RECT  9.895 1.152 10.291 1.314 ;
     RECT  9.887 2.106 10.291 103.734 ;
     RECT  9.751 0.144 10.399 0.162 ;
     RECT  10.399 0.144 10.463 0.234 ;
     RECT  10.291 1.152 10.463 103.734 ;
     RECT  10.463 1.224 10.499 103.734 ;
     RECT  9.355 104.796 10.723 104.886 ;
     RECT  10.499 1.728 10.751 103.734 ;
     RECT  10.751 2.106 10.831 103.734 ;
     RECT  10.723 104.796 10.831 104.922 ;
     RECT  10.831 2.106 10.931 104.922 ;
     RECT  10.931 2.151 11.011 104.922 ;
     RECT  10.463 0.216 11.443 0.234 ;
     RECT  11.479 1.224 11.587 1.242 ;
     RECT  11.587 1.152 11.615 1.242 ;
     RECT  11.011 2.151 11.759 104.994 ;
     RECT  11.443 0.144 11.875 0.234 ;
     RECT  11.759 104.904 11.975 104.994 ;
     RECT  11.875 0.144 12.191 0.396 ;
     RECT  11.759 2.151 12.451 103.734 ;
     RECT  11.615 1.152 12.595 1.17 ;
     RECT  11.975 104.904 12.695 104.922 ;
     RECT  12.595 1.152 12.703 1.278 ;
     RECT  12.451 2.106 12.703 103.734 ;
     RECT  12.191 0.144 12.839 0.234 ;
     RECT  12.703 1.152 13.163 103.734 ;
     RECT  13.163 1.152 13.199 103.689 ;
     RECT  13.199 1.152 13.523 1.242 ;
     RECT  12.839 0.144 13.631 0.198 ;
     RECT  13.631 0.144 13.847 0.162 ;
     RECT  13.523 1.152 13.847 1.17 ;
     RECT  13.199 2.106 13.999 103.689 ;
     RECT  13.999 2.034 14.431 103.689 ;
     RECT  14.431 1.962 15.583 103.689 ;
     RECT  15.583 1.962 16.115 103.734 ;
     RECT  16.115 2.151 18.599 103.734 ;
     RECT  18.599 2.151 41.04 103.689 ;
    LAYER M3 ;
     RECT  9 0.108 13.482 0.139 ;
     RECT  9 0.139 13.842 1.175 ;
     RECT  9 1.175 13.77 1.957 ;
     RECT  8.28 1.957 14.454 2.029 ;
     RECT  8.028 2.029 14.958 2.101 ;
     RECT  16.092 1.957 16.11 2.101 ;
     RECT  15.984 2.101 16.11 2.263 ;
     RECT  15.948 2.263 16.398 2.299 ;
     RECT  29.415 2.143 29.505 2.299 ;
     RECT  34.815 2.143 34.905 2.299 ;
     RECT  7.596 2.101 14.958 2.335 ;
     RECT  18.615 2.143 18.705 2.335 ;
     RECT  15.948 2.299 17.046 2.371 ;
     RECT  26.208 2.335 26.226 2.371 ;
     RECT  34.308 2.299 34.905 2.371 ;
     RECT  2.415 2.143 2.505 2.413 ;
     RECT  3.276 2.191 3.798 2.413 ;
     RECT  18.036 2.335 18.705 2.413 ;
     RECT  24.015 2.143 24.105 2.413 ;
     RECT  28.8 2.299 29.505 2.413 ;
     RECT  33.66 2.371 34.905 2.413 ;
     RECT  40.215 2.143 40.305 2.413 ;
     RECT  22.644 2.299 22.662 2.461 ;
     RECT  24.015 2.413 24.297 2.461 ;
     RECT  31.428 2.371 31.446 2.461 ;
     RECT  7.128 2.335 14.958 2.497 ;
     RECT  15.84 2.371 17.046 2.497 ;
     RECT  22.644 2.461 24.297 2.497 ;
     RECT  18.036 2.413 18.897 2.533 ;
     RECT  19.692 2.371 19.71 2.533 ;
     RECT  36.864 2.497 36.882 2.533 ;
     RECT  37.62 2.461 37.638 2.533 ;
     RECT  22.644 2.497 24.678 2.569 ;
     RECT  25.488 2.371 26.874 2.569 ;
     RECT  27.9 2.299 27.918 2.569 ;
     RECT  28.8 2.413 29.697 2.569 ;
     RECT  7.128 2.497 17.046 2.605 ;
     RECT  39.276 2.371 39.294 2.605 ;
     RECT  40.215 2.413 40.497 2.605 ;
     RECT  22.644 2.569 26.874 2.635 ;
     RECT  27.756 2.569 29.697 2.635 ;
     RECT  4.536 2.605 4.554 2.641 ;
     RECT  6.552 2.605 17.046 2.641 ;
     RECT  31.248 2.461 31.446 2.641 ;
     RECT  32.256 2.335 32.85 2.641 ;
     RECT  33.66 2.413 35.097 2.641 ;
     RECT  36 2.533 36.018 2.641 ;
     RECT  36.864 2.533 37.638 2.641 ;
     RECT  18.036 2.533 19.71 2.731 ;
     RECT  20.52 2.725 20.538 2.731 ;
     RECT  31.248 2.641 32.85 2.731 ;
     RECT  33.66 2.641 37.638 2.731 ;
     RECT  39.276 2.605 40.497 2.731 ;
     RECT  18.036 2.731 20.97 2.767 ;
     RECT  22.644 2.635 29.697 2.767 ;
     RECT  31.248 2.731 37.638 2.767 ;
     RECT  2.415 2.413 3.798 2.803 ;
     RECT  4.536 2.641 5.346 2.803 ;
     RECT  39.06 2.731 40.497 2.827 ;
     RECT  2.415 2.803 5.346 2.911 ;
     RECT  6.156 2.641 17.226 2.911 ;
     RECT  30.492 2.839 30.51 2.911 ;
     RECT  31.248 2.767 38.07 2.911 ;
     RECT  38.916 2.827 40.497 2.911 ;
     RECT  2.415 2.911 17.226 3.001 ;
     RECT  18.036 2.767 29.697 3.001 ;
     RECT  30.492 2.911 40.497 3.001 ;
     RECT  2.415 3.001 40.497 3.307 ;
     RECT  2.415 3.307 40.554 3.931 ;
     RECT  2.412 3.931 40.554 3.983 ;
     RECT  2.415 3.983 40.554 4.531 ;
     RECT  2.415 4.531 40.59 5.063 ;
     RECT  2.415 5.063 22.158 5.131 ;
     RECT  22.896 5.063 40.59 5.881 ;
     RECT  22.896 5.881 40.914 6.143 ;
     RECT  2.34 5.131 22.158 6.151 ;
     RECT  22.896 6.143 40.59 6.151 ;
     RECT  2.34 6.151 40.59 6.845 ;
     RECT  6.66 6.845 40.59 6.989 ;
     RECT  6.66 6.989 40.554 7.457 ;
     RECT  2.34 6.845 5.922 7.591 ;
     RECT  6.66 7.457 40.497 7.591 ;
     RECT  2.34 7.591 40.497 7.925 ;
     RECT  2.415 7.925 40.497 9.121 ;
     RECT  2.415 9.121 40.59 9.581 ;
     RECT  2.415 9.581 40.497 10.165 ;
     RECT  2.412 10.165 40.497 10.741 ;
     RECT  2.412 10.741 40.662 10.867 ;
     RECT  2.376 10.867 40.662 11.237 ;
     RECT  2.376 11.237 40.59 12.181 ;
     RECT  2.376 12.181 40.77 12.749 ;
     RECT  2.376 12.749 40.662 13.567 ;
     RECT  2.376 13.567 40.77 14.369 ;
     RECT  2.376 14.369 40.662 14.917 ;
     RECT  2.268 14.917 40.662 15.179 ;
     RECT  2.268 15.179 40.554 15.197 ;
     RECT  2.304 15.197 40.554 15.449 ;
     RECT  2.304 15.449 40.497 15.755 ;
     RECT  2.415 15.755 40.497 16.879 ;
     RECT  2.415 16.879 40.554 17.221 ;
     RECT  2.415 17.221 40.914 17.447 ;
     RECT  2.415 17.447 40.554 17.609 ;
     RECT  2.415 17.609 40.497 19.963 ;
     RECT  2.304 19.963 40.497 20.039 ;
     RECT  39.024 20.039 40.497 20.965 ;
     RECT  2.304 20.039 38.286 21.001 ;
     RECT  39.024 20.965 40.734 21.001 ;
     RECT  2.304 21.001 40.734 21.149 ;
     RECT  2.415 21.149 40.734 21.389 ;
     RECT  2.415 21.389 40.59 22.073 ;
     RECT  2.415 22.073 40.554 22.549 ;
     RECT  2.376 22.549 40.554 22.775 ;
     RECT  2.415 22.775 40.554 24.061 ;
     RECT  2.415 24.061 40.77 24.169 ;
     RECT  2.415 24.169 40.914 24.359 ;
     RECT  2.415 24.359 40.77 24.629 ;
     RECT  2.415 24.629 40.698 24.781 ;
     RECT  2.376 24.781 40.698 24.941 ;
     RECT  2.415 24.941 40.698 25.861 ;
     RECT  2.415 25.861 40.914 26.123 ;
     RECT  2.415 26.123 40.497 26.635 ;
     RECT  2.376 26.635 40.497 27.059 ;
     RECT  2.415 27.059 40.497 28.291 ;
     RECT  2.376 28.291 40.497 28.493 ;
     RECT  2.415 28.493 40.497 28.687 ;
     RECT  2.415 28.687 40.554 29.911 ;
     RECT  2.34 29.911 40.554 30.415 ;
     RECT  2.34 30.415 40.59 30.685 ;
     RECT  2.304 30.685 40.734 30.749 ;
     RECT  2.376 30.749 40.734 31.109 ;
     RECT  2.376 31.109 40.626 32.189 ;
     RECT  2.376 32.189 40.554 32.225 ;
     RECT  2.376 32.225 40.497 33.809 ;
     RECT  2.415 33.809 40.497 34.699 ;
     RECT  2.304 34.699 40.497 37.021 ;
     RECT  2.304 37.021 40.734 37.589 ;
     RECT  2.304 37.589 40.59 37.625 ;
     RECT  2.304 37.625 40.554 38.407 ;
     RECT  2.304 38.407 40.734 38.515 ;
     RECT  2.304 38.515 40.914 38.669 ;
     RECT  2.304 38.669 40.734 38.939 ;
     RECT  2.304 38.939 40.59 38.975 ;
     RECT  2.304 38.975 40.497 41.755 ;
     RECT  2.304 41.755 40.842 41.909 ;
     RECT  2.304 41.909 40.497 43.411 ;
     RECT  2.304 43.411 40.734 44.879 ;
     RECT  2.304 44.879 40.59 45.149 ;
     RECT  2.304 45.149 40.497 45.301 ;
     RECT  2.268 45.301 40.497 46.651 ;
     RECT  2.268 46.651 40.698 47.659 ;
     RECT  2.232 47.659 40.698 48.901 ;
     RECT  2.232 48.901 40.842 49.811 ;
     RECT  2.232 49.811 40.698 51.431 ;
     RECT  2.232 51.431 40.662 52.169 ;
     RECT  2.232 52.169 40.554 52.205 ;
     RECT  2.232 52.205 40.497 54.841 ;
     RECT  2.232 54.841 40.734 55.409 ;
     RECT  2.232 55.409 40.59 55.679 ;
     RECT  2.232 55.679 40.497 55.831 ;
     RECT  2.196 55.831 40.497 56.839 ;
     RECT  2.196 56.839 40.554 57.029 ;
     RECT  2.196 57.029 40.497 57.991 ;
     RECT  2.196 57.991 40.662 58.649 ;
     RECT  2.196 58.649 40.554 59.611 ;
     RECT  2.196 59.611 40.59 60.539 ;
     RECT  2.196 60.539 40.497 61.115 ;
     RECT  33.732 61.115 40.497 61.259 ;
     RECT  33.768 61.259 40.497 61.501 ;
     RECT  33.768 61.501 40.554 61.997 ;
     RECT  2.196 61.115 32.994 62.041 ;
     RECT  33.768 61.997 40.497 62.041 ;
     RECT  2.196 62.041 40.497 62.735 ;
     RECT  2.196 62.735 14.418 63.931 ;
     RECT  15.192 62.735 40.497 63.931 ;
     RECT  2.196 63.931 40.497 64.769 ;
     RECT  2.232 64.769 40.497 65.309 ;
     RECT  2.232 65.309 36.63 65.399 ;
     RECT  37.404 65.309 40.497 66.181 ;
     RECT  2.232 65.399 36.558 66.289 ;
     RECT  37.296 66.181 40.497 66.289 ;
     RECT  2.232 66.289 40.497 66.325 ;
     RECT  2.232 66.325 40.914 67.019 ;
     RECT  2.268 67.019 40.914 68.243 ;
     RECT  2.268 68.243 40.497 72.805 ;
     RECT  2.268 72.805 40.554 74.345 ;
     RECT  2.268 74.345 40.497 77.855 ;
     RECT  2.268 77.855 32.49 78.709 ;
     RECT  33.3 77.855 40.497 78.709 ;
     RECT  2.268 78.709 40.497 79.079 ;
     RECT  2.304 79.079 40.497 79.321 ;
     RECT  2.304 79.321 40.554 79.591 ;
     RECT  2.304 79.591 40.662 79.781 ;
     RECT  2.304 79.781 40.554 80.321 ;
     RECT  2.304 80.321 40.497 82.561 ;
     RECT  2.304 82.561 40.914 82.787 ;
     RECT  2.304 82.787 40.497 84.721 ;
     RECT  2.304 84.721 40.554 85.109 ;
     RECT  2.304 85.109 40.497 85.685 ;
     RECT  2.304 85.685 19.566 86.297 ;
     RECT  12.276 86.297 19.566 86.369 ;
     RECT  20.304 85.685 40.497 86.525 ;
     RECT  2.304 86.297 11.43 86.531 ;
     RECT  12.564 86.369 19.566 86.611 ;
     RECT  20.304 86.525 31.446 86.611 ;
     RECT  12.564 86.611 31.446 87.151 ;
     RECT  12.348 87.151 31.446 87.691 ;
     RECT  32.184 86.525 40.497 87.691 ;
     RECT  12.348 87.691 40.497 87.781 ;
     RECT  12.24 87.781 40.497 88.051 ;
     RECT  11.916 88.051 40.497 88.231 ;
     RECT  11.88 88.231 40.497 88.457 ;
     RECT  2.304 86.531 11.106 88.465 ;
     RECT  11.88 88.457 13.77 88.465 ;
     RECT  14.508 88.457 40.497 88.771 ;
     RECT  2.304 88.465 13.77 89.227 ;
     RECT  14.508 88.771 40.806 89.227 ;
     RECT  2.304 89.227 40.806 89.609 ;
     RECT  15.336 89.609 40.806 90.509 ;
     RECT  2.304 89.609 14.562 90.617 ;
     RECT  15.336 90.509 40.626 90.661 ;
     RECT  14.652 90.661 40.626 90.779 ;
     RECT  14.652 90.779 40.554 90.815 ;
     RECT  14.652 90.815 40.497 90.959 ;
     RECT  2.304 90.617 13.806 91.471 ;
     RECT  2.304 91.471 13.95 91.769 ;
     RECT  14.76 90.959 40.497 91.939 ;
     RECT  2.376 91.769 13.95 92.011 ;
     RECT  14.76 91.939 40.554 92.011 ;
     RECT  2.376 92.011 40.554 92.515 ;
     RECT  2.376 92.515 40.914 92.669 ;
     RECT  2.376 92.669 40.497 92.939 ;
     RECT  2.376 92.939 20.214 93.479 ;
     RECT  2.415 93.479 20.214 93.515 ;
     RECT  21.06 92.939 40.497 93.631 ;
     RECT  21.06 93.631 40.554 93.893 ;
     RECT  2.415 93.515 20.142 94.289 ;
     RECT  21.06 93.893 40.497 94.441 ;
     RECT  20.916 94.441 40.497 94.639 ;
     RECT  20.916 94.639 40.554 94.945 ;
     RECT  2.415 94.289 20.07 95.179 ;
     RECT  2.415 95.179 20.106 95.521 ;
     RECT  20.88 94.945 40.554 95.521 ;
     RECT  2.415 95.521 40.554 95.945 ;
     RECT  2.415 95.945 40.497 96.061 ;
     RECT  2.376 96.061 40.497 96.251 ;
     RECT  2.415 96.251 40.497 97.025 ;
     RECT  2.415 97.025 26.514 97.951 ;
     RECT  27.288 97.025 40.497 97.951 ;
     RECT  2.415 97.951 40.497 97.979 ;
     RECT  15.552 97.979 40.497 98.041 ;
     RECT  2.415 97.979 14.778 98.347 ;
     RECT  15.552 98.041 40.554 98.609 ;
     RECT  15.552 98.609 40.497 98.645 ;
     RECT  2.412 98.347 14.778 98.923 ;
     RECT  15.552 98.645 32.094 98.995 ;
     RECT  2.376 98.923 14.778 99.031 ;
     RECT  15.516 98.995 32.094 99.031 ;
     RECT  2.376 99.031 32.094 99.535 ;
     RECT  32.904 98.645 40.497 99.535 ;
     RECT  2.376 99.535 40.497 99.725 ;
     RECT  2.376 99.725 20.034 100.229 ;
     RECT  2.412 100.229 20.034 100.301 ;
     RECT  20.772 99.725 40.497 100.301 ;
     RECT  32.364 100.301 40.497 100.499 ;
     RECT  32.508 100.499 39.402 100.535 ;
     RECT  2.415 100.301 20.034 100.651 ;
     RECT  20.772 100.301 31.59 100.651 ;
     RECT  32.508 100.535 38.826 100.685 ;
     RECT  2.415 100.651 31.59 101.039 ;
     RECT  2.415 101.039 21.006 101.075 ;
     RECT  21.744 101.039 31.59 101.389 ;
     RECT  33.048 100.685 38.826 101.425 ;
     RECT  2.415 101.075 20.646 101.579 ;
     RECT  32.472 101.425 38.826 101.731 ;
     RECT  21.744 101.389 31.626 101.759 ;
     RECT  21.744 101.759 31.59 101.885 ;
     RECT  21.744 101.885 27.09 101.965 ;
     RECT  17.028 101.579 20.646 102.091 ;
     RECT  21.636 101.965 27.09 102.091 ;
     RECT  2.415 101.579 16.11 102.361 ;
     RECT  32.472 101.731 39.438 102.389 ;
     RECT  17.028 102.091 27.09 102.397 ;
     RECT  38.196 102.389 39.294 102.413 ;
     RECT  32.472 102.389 37.422 102.425 ;
     RECT  39.276 102.413 39.294 102.425 ;
     RECT  16.92 102.397 27.09 102.461 ;
     RECT  38.196 102.413 38.43 102.533 ;
     RECT  27.864 101.885 31.518 102.631 ;
     RECT  38.196 102.533 38.358 102.659 ;
     RECT  2.415 102.361 16.182 102.667 ;
     RECT  16.92 102.461 20.07 102.667 ;
     RECT  20.844 102.461 27.09 102.667 ;
     RECT  27.864 102.631 31.554 102.667 ;
     RECT  38.304 102.659 38.358 102.731 ;
     RECT  20.844 102.667 31.554 102.739 ;
     RECT  2.415 102.667 20.07 102.839 ;
     RECT  38.34 102.731 38.358 102.839 ;
     RECT  2.415 102.839 20.034 102.929 ;
     RECT  20.844 102.739 31.698 102.929 ;
     RECT  20.844 102.929 20.934 102.941 ;
     RECT  20.916 102.941 20.934 102.965 ;
     RECT  2.415 102.929 19.962 103.001 ;
     RECT  21.672 102.929 31.698 103.009 ;
     RECT  32.472 102.425 37.098 103.009 ;
     RECT  21.672 103.009 37.098 103.073 ;
     RECT  18.576 103.001 19.962 103.109 ;
     RECT  21.672 103.073 32.562 103.109 ;
     RECT  27.576 103.109 32.562 103.181 ;
     RECT  2.415 103.001 17.802 103.199 ;
     RECT  19.728 103.109 19.962 103.199 ;
     RECT  21.672 103.109 26.55 103.199 ;
     RECT  33.3 103.073 37.098 103.199 ;
     RECT  2.415 103.199 16.83 103.235 ;
     RECT  19.728 103.199 19.746 103.235 ;
     RECT  21.672 103.199 24.786 103.235 ;
     RECT  25.596 103.199 26.55 103.235 ;
     RECT  28.26 103.181 32.562 103.235 ;
     RECT  33.3 103.199 33.318 103.235 ;
     RECT  34.524 103.199 37.098 103.235 ;
     RECT  30.924 103.235 32.562 103.271 ;
     RECT  25.596 103.235 26.262 103.307 ;
     RECT  18.576 103.109 18.897 103.427 ;
     RECT  23.724 103.235 24.297 103.427 ;
     RECT  40.215 100.499 40.497 103.427 ;
     RECT  2.415 103.235 13.554 103.469 ;
     RECT  14.328 103.235 16.506 103.469 ;
     RECT  17.64 103.199 17.802 103.469 ;
     RECT  22.608 103.235 22.842 103.469 ;
     RECT  25.596 103.307 25.758 103.469 ;
     RECT  28.26 103.235 28.566 103.469 ;
     RECT  30.924 103.271 32.274 103.469 ;
     RECT  34.815 103.235 37.098 103.469 ;
     RECT  2.415 103.469 4.77 103.505 ;
     RECT  5.508 103.469 6.534 103.505 ;
     RECT  22.608 103.469 22.626 103.505 ;
     RECT  23.724 103.427 24.105 103.505 ;
     RECT  28.476 103.469 28.566 103.505 ;
     RECT  30.924 103.469 31.158 103.505 ;
     RECT  34.815 103.469 36.918 103.505 ;
     RECT  7.308 103.469 13.305 103.541 ;
     RECT  14.364 103.469 14.742 103.541 ;
     RECT  15.588 103.469 16.398 103.541 ;
     RECT  17.784 103.469 17.802 103.541 ;
     RECT  25.74 103.469 25.758 103.541 ;
     RECT  29.415 103.235 29.898 103.541 ;
     RECT  34.815 103.505 36.162 103.541 ;
     RECT  5.508 103.505 6.03 103.577 ;
     RECT  14.364 103.541 14.382 103.577 ;
     RECT  28.548 103.505 28.566 103.577 ;
     RECT  16.38 103.541 16.398 103.613 ;
     RECT  3.42 103.505 4.77 103.649 ;
     RECT  5.508 103.577 5.526 103.649 ;
     RECT  7.308 103.541 7.905 103.649 ;
     RECT  30.924 103.505 30.942 103.649 ;
     RECT  36.144 103.541 36.162 103.649 ;
     RECT  2.415 103.505 2.505 103.697 ;
     RECT  7.815 103.649 7.905 103.697 ;
     RECT  8.676 103.541 13.305 103.697 ;
     RECT  18.576 103.427 18.705 103.697 ;
     RECT  24.015 103.505 24.105 103.697 ;
     RECT  29.415 103.541 29.505 103.697 ;
     RECT  34.815 103.541 34.905 103.697 ;
     RECT  40.215 103.427 40.305 103.697 ;
     RECT  4.032 103.649 4.77 103.739 ;
     RECT  8.676 103.697 13.158 103.739 ;
     RECT  15.588 103.541 15.606 103.739 ;
     RECT  18.576 103.697 18.594 103.739 ;
     RECT  8.676 103.739 12.69 104.927 ;
     RECT  8.676 104.927 11.97 104.957 ;
     RECT  9 104.957 11.97 104.999 ;
     RECT  9 104.999 11.466 105.708 ;
    LAYER M4 ;
     RECT  0.156 14.88 0.275 15.192 ;
     RECT  2.252 19.968 2.293 19.992 ;
     RECT  2.252 30.72 2.293 30.744 ;
     RECT  0.229 53.856 2.293 53.88 ;
     RECT  2.265 79.248 2.329 79.272 ;
     RECT  2.293 30.72 2.365 31.416 ;
     RECT  2.365 10.992 2.401 11.016 ;
     RECT  2.365 99.696 2.401 99.72 ;
     RECT  2.293 3.936 2.408 3.96 ;
     RECT  2.285 5.136 2.408 5.16 ;
     RECT  2.329 7.44 2.408 7.464 ;
     RECT  2.401 10.176 2.408 11.016 ;
     RECT  2.365 13.632 2.408 13.656 ;
     RECT  0.275 15.024 2.408 15.192 ;
     RECT  2.293 19.248 2.408 19.992 ;
     RECT  2.293 21.12 2.408 21.144 ;
     RECT  2.365 24.912 2.408 24.936 ;
     RECT  2.365 26.64 2.408 26.664 ;
     RECT  2.293 28.464 2.408 28.488 ;
     RECT  2.365 30.72 2.408 32.328 ;
     RECT  2.365 41.76 2.408 42.024 ;
     RECT  2.365 44.448 2.408 44.472 ;
     RECT  2.365 49.296 2.408 49.32 ;
     RECT  2.293 53.856 2.408 54.696 ;
     RECT  2.252 63.216 2.408 63.24 ;
     RECT  2.245 64.32 2.408 64.968 ;
     RECT  2.329 78.48 2.408 79.272 ;
     RECT  2.293 80.256 2.408 80.28 ;
     RECT  2.365 87.936 2.408 88.776 ;
     RECT  2.401 99.696 2.408 100.296 ;
     RECT  2.408 2.148 2.512 103.692 ;
     RECT  2.512 2.418 2.704 103.422 ;
     RECT  2.704 62.64 2.819 64.2 ;
     RECT  2.704 2.832 2.837 3.96 ;
     RECT  2.704 40.992 2.837 45.576 ;
     RECT  2.819 64.176 2.837 64.2 ;
     RECT  2.704 50.64 2.86 51.96 ;
     RECT  2.704 65.52 2.86 68.952 ;
     RECT  2.704 46.656 2.867 49.32 ;
     RECT  2.867 46.656 2.873 48.456 ;
     RECT  2.837 40.992 2.909 42.744 ;
     RECT  2.704 78.48 2.909 79.272 ;
     RECT  2.704 86.592 2.915 88.776 ;
     RECT  2.704 72.912 2.945 73.512 ;
     RECT  2.704 38.688 2.981 40.008 ;
     RECT  2.837 2.832 3.017 3.096 ;
     RECT  2.909 41.616 3.017 42.744 ;
     RECT  2.86 51.168 3.053 51.96 ;
     RECT  2.704 95.664 3.059 96.936 ;
     RECT  2.86 66.672 3.089 68.952 ;
     RECT  3.059 95.664 3.1 95.688 ;
     RECT  2.704 99.168 3.133 100.92 ;
     RECT  2.704 60.432 3.203 60.984 ;
     RECT  2.873 46.656 3.305 48.024 ;
     RECT  2.915 86.592 3.305 87.72 ;
     RECT  2.837 44.448 3.341 45.576 ;
     RECT  3.305 46.656 3.341 47.352 ;
     RECT  3.133 99.168 3.341 100.056 ;
     RECT  2.704 6.576 3.413 7.464 ;
     RECT  2.704 31.392 3.413 32.328 ;
     RECT  2.704 80.832 3.413 81.528 ;
     RECT  3.305 86.592 3.413 86.76 ;
     RECT  3.413 7.44 3.449 7.464 ;
     RECT  2.704 19.248 3.449 20.136 ;
     RECT  3.413 86.64 3.449 86.76 ;
     RECT  2.704 103.2 3.449 103.224 ;
     RECT  2.909 78.624 3.485 79.272 ;
     RECT  3.413 80.832 3.485 80.856 ;
     RECT  2.704 13.632 3.491 14.28 ;
     RECT  2.704 21.12 3.521 21.432 ;
     RECT  2.704 34.752 3.521 37.656 ;
     RECT  3.203 60.432 3.521 60.456 ;
     RECT  2.704 8.976 3.557 11.4 ;
     RECT  3.017 41.616 3.557 42.072 ;
     RECT  3.341 47.28 3.557 47.352 ;
     RECT  3.053 51.168 3.557 51.192 ;
     RECT  2.704 83.184 3.557 84.408 ;
     RECT  2.704 91.776 3.629 94.632 ;
     RECT  3.413 32.304 3.665 32.328 ;
     RECT  2.704 57.072 3.665 58.728 ;
     RECT  3.341 99.648 3.665 100.056 ;
     RECT  2.704 26.64 3.697 26.664 ;
     RECT  2.704 27.744 3.697 27.768 ;
     RECT  2.704 70.656 3.701 70.68 ;
     RECT  3.629 91.776 3.731 93 ;
     RECT  3.697 26.64 3.737 27.768 ;
     RECT  2.704 52.992 3.769 55.848 ;
     RECT  3.629 94.56 3.769 94.632 ;
     RECT  3.341 44.448 3.813 44.472 ;
     RECT  3.769 52.176 3.841 55.848 ;
     RECT  3.665 57.072 3.841 58.68 ;
     RECT  3.521 21.12 3.845 21.144 ;
     RECT  2.981 38.688 3.845 39.672 ;
     RECT  2.704 16.512 3.877 16.536 ;
     RECT  3.557 84.192 3.884 84.408 ;
     RECT  2.915 88.752 3.887 88.776 ;
     RECT  2.704 89.76 3.887 90.648 ;
     RECT  2.704 71.664 3.949 71.832 ;
     RECT  2.86 65.52 3.953 65.544 ;
     RECT  3.884 84.192 3.971 85.128 ;
     RECT  3.845 39.168 4.019 39.672 ;
     RECT  2.945 72.912 4.019 72.936 ;
     RECT  3.813 43.92 4.021 44.472 ;
     RECT  3.841 52.176 4.025 58.68 ;
     RECT  3.877 15.408 4.057 16.536 ;
     RECT  3.089 66.672 4.057 68.088 ;
     RECT  3.887 88.752 4.057 90.648 ;
     RECT  4.025 52.176 4.067 58.392 ;
     RECT  2.704 5.088 4.093 5.112 ;
     RECT  3.491 14.256 4.097 14.28 ;
     RECT  2.704 23.328 4.169 23.352 ;
     RECT  4.057 15.408 4.201 17.112 ;
     RECT  2.704 18.144 4.201 18.168 ;
     RECT  4.057 66.672 4.237 68.232 ;
     RECT  4.057 88.32 4.277 90.648 ;
     RECT  4.237 66.672 4.313 69.192 ;
     RECT  3.949 71.616 4.313 71.832 ;
     RECT  3.805 45.6 4.345 45.624 ;
     RECT  4.309 82.32 4.381 82.68 ;
     RECT  3.485 78.624 4.403 78.648 ;
     RECT  4.313 66.672 4.405 67.32 ;
     RECT  3.449 86.64 4.405 86.664 ;
     RECT  3.769 94.56 4.412 95.4 ;
     RECT  3.059 96.672 4.412 96.936 ;
     RECT  2.704 98.016 4.412 98.04 ;
     RECT  3.971 84.192 4.451 84.936 ;
     RECT  2.704 29.616 4.453 29.64 ;
     RECT  4.412 94.56 4.453 98.04 ;
     RECT  2.819 62.64 4.489 62.712 ;
     RECT  4.453 94.56 4.499 98.088 ;
     RECT  3.805 80.112 4.501 80.376 ;
     RECT  4.381 81.504 4.501 82.68 ;
     RECT  3.017 3.072 4.525 3.096 ;
     RECT  4.499 96.912 4.529 98.088 ;
     RECT  4.499 94.56 4.537 95.688 ;
     RECT  4.501 80.112 4.547 82.68 ;
     RECT  4.201 15.408 4.561 18.168 ;
     RECT  4.313 68.352 4.595 69.192 ;
     RECT  2.704 24.912 4.597 24.936 ;
     RECT  4.561 15.312 4.601 18.168 ;
     RECT  4.597 24.528 4.601 24.936 ;
     RECT  4.451 84.192 4.601 84.408 ;
     RECT  4.021 43.824 4.633 44.472 ;
     RECT  4.345 45.552 4.633 45.624 ;
     RECT  4.597 22.752 4.669 22.776 ;
     RECT  4.067 52.176 4.673 57.816 ;
     RECT  4.601 24.528 4.681 24.552 ;
     RECT  4.309 40.416 4.693 40.44 ;
     RECT  4.601 16.32 4.709 18.168 ;
     RECT  4.547 80.352 4.709 80.904 ;
     RECT  4.709 80.352 4.739 80.376 ;
     RECT  4.633 43.824 4.741 45.624 ;
     RECT  3.557 47.28 4.741 47.304 ;
     RECT  4.453 60.384 4.777 60.408 ;
     RECT  4.693 40.416 4.78 40.92 ;
     RECT  4.525 2.832 4.813 3.096 ;
     RECT  4.709 16.368 4.813 18.168 ;
     RECT  3.449 19.248 4.813 19.992 ;
     RECT  4.777 24.48 4.813 24.504 ;
     RECT  4.405 85.92 4.813 86.664 ;
     RECT  4.277 88.32 4.813 90.312 ;
     RECT  4.813 16.368 4.817 19.992 ;
     RECT  3.731 92.352 4.817 93 ;
     RECT  4.817 17.088 4.835 19.992 ;
     RECT  3.521 34.752 4.844 37.032 ;
     RECT  4.741 47.28 4.844 47.832 ;
     RECT  4.601 84.192 4.853 84.36 ;
     RECT  4.813 2.832 4.885 3.384 ;
     RECT  4.093 4.752 4.885 5.112 ;
     RECT  3.557 9.504 4.885 11.4 ;
     RECT  4.525 33.504 4.885 33.528 ;
     RECT  4.844 34.512 4.885 37.032 ;
     RECT  3.557 42.048 4.885 42.072 ;
     RECT  4.453 99.12 4.885 99.144 ;
     RECT  4.885 8.544 4.925 11.4 ;
     RECT  4.777 60.384 4.925 60.6 ;
     RECT  4.885 33.504 4.931 37.032 ;
     RECT  4.237 6.144 4.957 6.168 ;
     RECT  4.925 8.544 4.957 10.344 ;
     RECT  4.885 41.904 4.957 42.072 ;
     RECT  4.741 43.824 4.961 45.72 ;
     RECT  4.595 68.352 4.961 68.376 ;
     RECT  3.737 27.024 4.993 27.768 ;
     RECT  4.931 34.896 4.993 37.032 ;
     RECT  4.817 92.544 4.993 93 ;
     RECT  4.961 43.824 5.027 44.328 ;
     RECT  4.931 33.504 5.029 33.624 ;
     RECT  4.405 65.568 5.029 67.32 ;
     RECT  5.029 65.136 5.075 67.32 ;
     RECT  4.993 26.784 5.077 27.768 ;
     RECT  5.075 65.136 5.077 67.272 ;
     RECT  4.345 49.104 5.101 49.128 ;
     RECT  5.027 43.872 5.105 44.328 ;
     RECT  4.957 13.248 5.125 13.272 ;
     RECT  5.101 50.352 5.137 50.376 ;
     RECT  5.105 43.872 5.141 43.896 ;
     RECT  4.673 52.416 5.141 57.816 ;
     RECT  5.125 13.248 5.171 13.848 ;
     RECT  4.529 97.632 5.173 98.088 ;
     RECT  4.885 99.12 5.173 99.768 ;
     RECT  4.489 62.64 5.177 63.192 ;
     RECT  5.171 13.632 5.209 13.848 ;
     RECT  4.601 15.312 5.209 15.336 ;
     RECT  5.141 52.416 5.213 57.384 ;
     RECT  4.813 85.92 5.213 90.312 ;
     RECT  5.173 97.632 5.213 99.768 ;
     RECT  5.077 25.872 5.249 27.768 ;
     RECT  5.213 53.856 5.249 57.384 ;
     RECT  4.835 17.472 5.269 19.992 ;
     RECT  4.993 21.12 5.269 21.144 ;
     RECT  4.925 60.384 5.285 60.408 ;
     RECT  5.077 64.656 5.285 67.272 ;
     RECT  5.209 13.632 5.315 15.336 ;
     RECT  5.269 17.472 5.315 21.144 ;
     RECT  4.019 39.168 5.317 39.192 ;
     RECT  4.78 40.416 5.317 40.44 ;
     RECT  5.213 85.92 5.321 87.432 ;
     RECT  4.844 47.232 5.324 47.832 ;
     RECT  4.885 2.832 5.353 5.112 ;
     RECT  4.957 6.144 5.353 6.312 ;
     RECT  5.249 53.856 5.357 57.192 ;
     RECT  4.961 45.696 5.393 45.72 ;
     RECT  4.853 84.24 5.393 84.36 ;
     RECT  4.453 29.616 5.425 29.784 ;
     RECT  5.213 88.896 5.425 90.312 ;
     RECT  5.125 11.952 5.429 11.976 ;
     RECT  5.101 49.008 5.461 49.128 ;
     RECT  5.137 50.112 5.461 50.376 ;
     RECT  5.315 17.472 5.501 20.52 ;
     RECT  5.029 33.264 5.533 33.624 ;
     RECT  4.453 31.728 5.557 31.992 ;
     RECT  4.993 92.544 5.573 93.528 ;
     RECT  5.557 30.912 5.612 31.992 ;
     RECT  5.533 33.024 5.612 33.624 ;
     RECT  5.101 102.672 5.641 102.696 ;
     RECT  5.612 30.912 5.644 33.624 ;
     RECT  5.357 53.856 5.645 56.424 ;
     RECT  5.285 64.656 5.645 66.792 ;
     RECT  4.669 22.176 5.669 22.776 ;
     RECT  5.644 30.96 5.699 33.624 ;
     RECT  5.324 46.752 5.701 47.832 ;
     RECT  5.461 49.008 5.701 50.376 ;
     RECT  5.177 63.168 5.701 63.192 ;
     RECT  5.645 64.656 5.701 66.216 ;
     RECT  5.249 26.784 5.708 27.768 ;
     RECT  5.701 46.752 5.708 50.376 ;
     RECT  4.957 8.496 5.713 10.344 ;
     RECT  4.313 71.616 5.713 71.64 ;
     RECT  5.315 13.632 5.745 13.848 ;
     RECT  5.501 17.472 5.747 18.984 ;
     RECT  5.701 63.168 5.747 66.216 ;
     RECT  5.315 15.312 5.749 15.336 ;
     RECT  5.708 46.752 5.749 50.712 ;
     RECT  5.669 22.176 5.753 22.824 ;
     RECT  4.993 34.896 5.753 37.08 ;
     RECT  5.641 102 5.753 102.696 ;
     RECT  5.641 78.672 5.785 78.696 ;
     RECT  5.393 84.288 5.785 84.36 ;
     RECT  5.321 85.92 5.785 86.088 ;
     RECT  5.749 15.312 5.789 15.432 ;
     RECT  5.785 78.672 5.789 78.936 ;
     RECT  5.573 93.504 5.789 93.528 ;
     RECT  5.749 46.752 5.795 51 ;
     RECT  5.213 97.968 5.845 99.768 ;
     RECT  5.533 100.752 5.845 100.776 ;
     RECT  5.753 22.176 5.852 22.488 ;
     RECT  5.708 26.784 5.857 27.816 ;
     RECT  5.317 39.168 5.861 40.44 ;
     RECT  5.845 97.968 5.861 100.776 ;
     RECT  5.785 84.288 5.869 86.088 ;
     RECT  5.353 2.832 5.893 6.312 ;
     RECT  5.753 35.232 5.893 37.08 ;
     RECT  5.795 46.752 5.897 48.84 ;
     RECT  5.789 78.912 5.897 78.936 ;
     RECT  5.893 35.232 5.929 37.128 ;
     RECT  5.747 18.624 5.939 18.984 ;
     RECT  5.857 26.784 5.965 28.248 ;
     RECT  4.547 82.32 5.969 82.344 ;
     RECT  5.965 26.784 5.987 28.296 ;
     RECT  5.929 35.232 6.001 37.56 ;
     RECT  5.987 27.072 6.005 28.296 ;
     RECT  6.005 27.264 6.113 28.296 ;
     RECT  4.537 95.088 6.113 95.688 ;
     RECT  5.861 97.968 6.181 100.488 ;
     RECT  5.747 63.984 6.185 66.216 ;
     RECT  5.795 50.16 6.217 51 ;
     RECT  5.425 88.896 6.217 90.648 ;
     RECT  6.181 97.776 6.221 100.488 ;
     RECT  6.217 50.16 6.229 51.048 ;
     RECT  5.213 52.416 6.229 52.824 ;
     RECT  5.897 46.752 6.257 48.696 ;
     RECT  5.321 87.168 6.277 87.432 ;
     RECT  4.957 41.904 6.289 42.744 ;
     RECT  6.257 46.752 6.289 47.88 ;
     RECT  5.893 2.832 6.293 7.368 ;
     RECT  6.217 88.896 6.293 90.888 ;
     RECT  6.001 35.232 6.329 38.184 ;
     RECT  5.869 85.488 6.329 86.088 ;
     RECT  5.753 102 6.329 102.312 ;
     RECT  6.325 73.536 6.361 73.56 ;
     RECT  6.332 93.984 6.361 94.008 ;
     RECT  6.185 64.32 6.365 66.216 ;
     RECT  5.747 17.472 6.397 17.496 ;
     RECT  4.813 24.096 6.397 24.504 ;
     RECT  6.361 93.984 6.419 94.872 ;
     RECT  2.704 75.936 6.433 75.96 ;
     RECT  6.397 17.088 6.437 17.496 ;
     RECT  5.425 29.52 6.437 29.784 ;
     RECT  6.329 35.28 6.437 38.184 ;
     RECT  6.289 46.704 6.437 47.88 ;
     RECT  6.397 24.096 6.469 24.744 ;
     RECT  6.361 73.536 6.469 73.944 ;
     RECT  6.469 24.096 6.509 25.224 ;
     RECT  6.229 50.16 6.509 52.824 ;
     RECT  6.437 36 6.545 38.184 ;
     RECT  6.509 50.16 6.545 52.152 ;
     RECT  6.293 89.712 6.545 90.888 ;
     RECT  6.181 96.288 6.545 96.312 ;
     RECT  6.293 2.88 6.563 7.368 ;
     RECT  5.745 13.632 6.581 13.656 ;
     RECT  5.852 21.888 6.581 22.488 ;
     RECT  6.329 85.488 6.581 85.512 ;
     RECT  6.545 90.864 6.581 90.888 ;
     RECT  6.109 44.448 6.649 44.472 ;
     RECT  6.505 45.504 6.649 45.528 ;
     RECT  5.645 53.856 6.649 55.272 ;
     RECT  5.645 56.4 6.649 56.424 ;
     RECT  6.221 97.776 6.649 100.2 ;
     RECT  6.433 75.936 6.685 76.392 ;
     RECT  6.277 87.168 6.685 87.72 ;
     RECT  5.713 8.352 6.725 10.344 ;
     RECT  5.939 18.768 6.757 18.984 ;
     RECT  6.329 102.144 6.792 102.312 ;
     RECT  6.469 73.536 6.797 74.472 ;
     RECT  5.501 20.352 6.803 20.52 ;
     RECT  5.699 30.96 6.829 31.896 ;
     RECT  5.869 84.288 6.829 84.36 ;
     RECT  6.649 97.632 6.829 100.2 ;
     RECT  6.757 18.768 6.833 19.32 ;
     RECT  6.792 102.144 6.853 102.648 ;
     RECT  5.789 15.408 6.865 15.432 ;
     RECT  6.289 41.904 6.865 43.32 ;
     RECT  6.853 102.144 6.865 102.792 ;
     RECT  6.797 73.824 6.901 74.472 ;
     RECT  6.685 75.936 6.901 76.728 ;
     RECT  6.829 30.864 7.045 31.896 ;
     RECT  6.829 97.44 7.045 100.2 ;
     RECT  6.685 58.656 7.117 58.68 ;
     RECT  5.699 33.072 7.153 33.624 ;
     RECT  6.649 53.856 7.153 56.424 ;
     RECT  6.509 24.48 7.189 25.224 ;
     RECT  7.045 96.72 7.189 100.2 ;
     RECT  7.117 58.656 7.196 58.728 ;
     RECT  6.289 60 7.196 60.024 ;
     RECT  6.545 50.16 7.225 51.096 ;
     RECT  7.196 58.128 7.237 58.728 ;
     RECT  6.865 41.232 7.261 43.32 ;
     RECT  7.189 96.72 7.261 100.536 ;
     RECT  7.045 30.864 7.333 32.04 ;
     RECT  7.153 33.072 7.333 34.152 ;
     RECT  6.365 64.32 7.333 65.304 ;
     RECT  6.581 22.464 7.369 22.488 ;
     RECT  5.861 40.128 7.369 40.152 ;
     RECT  7.261 41.232 7.369 43.368 ;
     RECT  6.685 87.168 7.369 88.344 ;
     RECT  7.261 96.72 7.369 100.584 ;
     RECT  7.369 40.128 7.405 43.368 ;
     RECT  6.545 36.048 7.477 38.184 ;
     RECT  6.437 17.088 7.513 17.304 ;
     RECT  6.649 44.448 7.549 45.528 ;
     RECT  6.545 89.712 7.585 89.736 ;
     RECT  6.419 94.56 7.585 94.872 ;
     RECT  6.865 15.408 7.657 15.72 ;
     RECT  5.701 61.728 7.669 61.752 ;
     RECT  7.369 96.72 7.669 100.632 ;
     RECT  6.113 27.744 7.693 28.296 ;
     RECT  6.437 29.52 7.693 29.544 ;
     RECT  7.045 14.16 7.729 14.28 ;
     RECT  7.657 15.312 7.729 15.72 ;
     RECT  7.369 22.464 7.765 23.16 ;
     RECT  7.405 40.032 7.765 43.368 ;
     RECT  7.549 44.448 7.765 45.72 ;
     RECT  6.563 2.88 7.808 3.72 ;
     RECT  6.563 4.752 7.808 7.368 ;
     RECT  6.725 9.312 7.808 10.344 ;
     RECT  6.361 11.52 7.808 11.544 ;
     RECT  7.141 13.056 7.808 13.08 ;
     RECT  7.729 14.16 7.808 15.72 ;
     RECT  7.513 17.088 7.808 17.496 ;
     RECT  6.833 18.96 7.808 19.32 ;
     RECT  6.803 20.352 7.808 20.376 ;
     RECT  7.765 21.984 7.808 23.16 ;
     RECT  7.189 24.48 7.808 25.56 ;
     RECT  7.693 27.744 7.808 29.544 ;
     RECT  7.333 30.864 7.808 34.152 ;
     RECT  7.477 36.048 7.808 38.52 ;
     RECT  7.765 40.032 7.808 45.72 ;
     RECT  6.437 47.28 7.808 47.88 ;
     RECT  7.225 50.016 7.808 51.096 ;
     RECT  6.545 52.128 7.808 52.152 ;
     RECT  7.153 53.856 7.808 57.096 ;
     RECT  7.237 58.128 7.808 58.776 ;
     RECT  7.196 60 7.808 60.264 ;
     RECT  7.669 61.728 7.808 63.288 ;
     RECT  7.333 64.32 7.808 65.592 ;
     RECT  6.829 66.672 7.808 66.696 ;
     RECT  5.713 71.616 7.808 71.736 ;
     RECT  6.901 73.824 7.808 74.76 ;
     RECT  6.901 75.936 7.808 77.064 ;
     RECT  6.865 78.72 7.808 78.744 ;
     RECT  6.829 84.144 7.808 84.36 ;
     RECT  7.369 86.448 7.808 88.344 ;
     RECT  7.585 89.712 7.808 90.552 ;
     RECT  6.373 92.112 7.808 92.136 ;
     RECT  7.585 94.368 7.808 94.872 ;
     RECT  7.669 96.72 7.808 101.064 ;
     RECT  6.865 102.144 7.808 103.224 ;
     RECT  7.808 2.148 7.912 103.692 ;
     RECT  7.912 2.418 8.104 103.422 ;
     RECT  8.104 63.024 8.237 63.24 ;
     RECT  8.104 79.728 8.309 80.808 ;
     RECT  8.104 46.896 8.345 48.696 ;
     RECT  8.104 24.48 8.381 29.832 ;
     RECT  8.104 50.016 8.387 51.912 ;
     RECT  8.104 74.112 8.417 77.256 ;
     RECT  8.104 44.88 8.489 45.72 ;
     RECT  8.104 69.216 8.489 69.24 ;
     RECT  8.104 78.624 8.525 78.648 ;
     RECT  8.104 36.24 8.531 43.848 ;
     RECT  8.104 58.752 8.597 58.776 ;
     RECT  8.417 76.704 8.597 77.256 ;
     RECT  8.104 96.24 8.641 103.32 ;
     RECT  8.345 47.472 8.669 48.696 ;
     RECT  8.104 89.52 8.723 92.424 ;
     RECT  8.104 2.418 8.813 23.4 ;
     RECT  8.531 41.52 8.813 43.848 ;
     RECT  8.489 45.12 8.813 45.72 ;
     RECT  8.104 84.144 8.813 85.512 ;
     RECT  8.665 104.928 8.821 104.952 ;
     RECT  8.813 3.792 8.849 23.4 ;
     RECT  8.104 30.816 8.849 33.864 ;
     RECT  8.104 56.304 8.849 57.096 ;
     RECT  8.417 74.112 8.957 75.432 ;
     RECT  8.723 89.712 8.957 92.424 ;
     RECT  8.104 60 8.963 60.264 ;
     RECT  8.813 2.418 8.981 2.76 ;
     RECT  8.849 3.792 8.993 14.472 ;
     RECT  8.957 74.112 8.993 74.76 ;
     RECT  8.993 3.792 9.029 6.168 ;
     RECT  8.963 60.144 9.109 60.264 ;
     RECT  8.104 61.728 9.109 62.04 ;
     RECT  8.237 63.12 9.109 63.24 ;
     RECT  8.104 65.52 9.109 65.544 ;
     RECT  8.813 84.144 9.109 84.552 ;
     RECT  8.387 50.16 9.133 51.912 ;
     RECT  8.104 67.104 9.133 67.8 ;
     RECT  9.109 63.12 9.155 64.056 ;
     RECT  8.641 100.272 9.157 103.32 ;
     RECT  8.849 16.272 9.173 23.4 ;
     RECT  9.109 60.144 9.196 62.04 ;
     RECT  8.993 7.488 9.209 14.472 ;
     RECT  8.597 77.04 9.209 77.256 ;
     RECT  9.109 83.76 9.216 84.552 ;
     RECT  8.104 71.232 9.241 72.6 ;
     RECT  8.309 79.728 9.241 80.28 ;
     RECT  8.104 94.032 9.241 95.16 ;
     RECT  8.641 96.24 9.241 99.192 ;
     RECT  9.196 60.144 9.281 61.032 ;
     RECT  8.104 87.168 9.317 87.384 ;
     RECT  9.241 79.248 9.325 80.28 ;
     RECT  9.325 80.112 9.349 80.28 ;
     RECT  9.029 3.936 9.389 6.168 ;
     RECT  9.317 87.36 9.421 87.384 ;
     RECT  9.313 88.464 9.421 88.488 ;
     RECT  9.173 16.272 9.425 19.992 ;
     RECT  9.241 71.232 9.445 73.128 ;
     RECT  9.349 80.112 9.445 81 ;
     RECT  8.104 82.56 9.445 82.584 ;
     RECT  9.445 80.112 9.452 82.584 ;
     RECT  8.531 36.24 9.461 40.152 ;
     RECT  8.813 41.52 9.491 43.32 ;
     RECT  9.445 70.416 9.497 73.128 ;
     RECT  9.461 36.24 9.529 37.608 ;
     RECT  8.813 45.12 9.529 45.48 ;
     RECT  9.497 70.416 9.532 72.168 ;
     RECT  8.669 47.712 9.533 48.696 ;
     RECT  9.133 67.104 9.533 68.376 ;
     RECT  9.452 80.112 9.533 82.68 ;
     RECT  9.216 83.76 9.533 83.784 ;
     RECT  9.533 82.56 9.539 82.68 ;
     RECT  9.209 77.232 9.541 77.256 ;
     RECT  8.849 32.304 9.569 33.864 ;
     RECT  9.491 41.52 9.569 42.168 ;
     RECT  8.993 74.352 9.569 74.76 ;
     RECT  9.541 77.232 9.587 77.544 ;
     RECT  9.529 35.952 9.589 37.608 ;
     RECT  9.241 94.032 9.601 99.192 ;
     RECT  8.981 1.728 9.605 2.76 ;
     RECT  9.569 41.904 9.635 42.168 ;
     RECT  9.601 93.216 9.637 99.192 ;
     RECT  9.157 100.272 9.637 103.752 ;
     RECT  9.533 67.104 9.641 68.328 ;
     RECT  8.381 25.152 9.644 29.832 ;
     RECT  8.849 30.816 9.644 31.32 ;
     RECT  8.104 53.856 9.644 54.744 ;
     RECT  9.644 25.152 9.673 31.32 ;
     RECT  9.569 32.736 9.685 33.864 ;
     RECT  8.104 34.848 9.685 34.92 ;
     RECT  9.389 3.936 9.713 6.12 ;
     RECT  9.425 16.272 9.713 18.84 ;
     RECT  9.685 32.736 9.713 34.92 ;
     RECT  9.673 24.912 9.731 31.32 ;
     RECT  9.644 53.856 9.731 55.272 ;
     RECT  8.849 56.304 9.731 57.048 ;
     RECT  9.125 0.576 9.779 0.6 ;
     RECT  9.731 30.048 9.785 31.32 ;
     RECT  9.421 87.36 9.785 88.488 ;
     RECT  9.713 16.272 9.853 16.92 ;
     RECT  9.532 71.184 9.857 72.168 ;
     RECT  9.529 44.448 9.877 45.48 ;
     RECT  9.133 50.16 9.877 52.008 ;
     RECT  9.425 19.824 9.893 19.992 ;
     RECT  9.385 86.064 9.893 86.088 ;
     RECT  9.533 47.712 9.923 48.264 ;
     RECT  9.877 49.248 9.923 52.008 ;
     RECT  9.785 87.792 9.925 88.488 ;
     RECT  8.957 89.712 9.925 91.752 ;
     RECT  9.637 93.216 9.925 103.752 ;
     RECT  9.731 53.856 9.997 54.696 ;
     RECT  9.925 87.792 10.001 91.8 ;
     RECT  9.785 30.048 10.037 30.984 ;
     RECT  10.001 88.848 10.069 91.8 ;
     RECT  9.925 93.216 10.069 103.8 ;
     RECT  9.923 47.712 10.105 47.88 ;
     RECT  8.821 104.88 10.141 104.952 ;
     RECT  9.923 49.248 10.145 49.272 ;
     RECT  9.569 74.496 10.145 74.76 ;
     RECT  9.173 21.12 10.177 22.488 ;
     RECT  9.713 34.8 10.177 34.92 ;
     RECT  9.589 35.904 10.177 37.608 ;
     RECT  10.069 84.912 10.181 85.416 ;
     RECT  9.281 60.144 10.217 60.168 ;
     RECT  10.177 20.976 10.249 22.488 ;
     RECT  9.889 23.568 10.249 23.592 ;
     RECT  9.529 58.368 10.249 58.392 ;
     RECT  10.069 88.848 10.249 103.8 ;
     RECT  10.141 104.88 10.249 105.048 ;
     RECT  9.731 24.912 10.259 28.2 ;
     RECT  9.533 80.112 10.259 81.576 ;
     RECT  10.249 20.976 10.289 23.592 ;
     RECT  10.177 34.8 10.289 37.608 ;
     RECT  10.145 74.64 10.289 74.76 ;
     RECT  9.713 18 10.361 18.84 ;
     RECT  10.289 36.912 10.361 37.608 ;
     RECT  9.605 2.736 10.421 2.76 ;
     RECT  9.713 3.936 10.421 6.024 ;
     RECT  10.421 2.736 10.433 6.024 ;
     RECT  10.289 74.736 10.433 74.76 ;
     RECT  10.259 80.928 10.433 80.952 ;
     RECT  9.845 0.192 10.505 0.552 ;
     RECT  9.635 42.144 10.505 42.168 ;
     RECT  9.253 62.736 10.508 62.76 ;
     RECT  10.361 37.584 10.537 37.608 ;
     RECT  9.461 39.264 10.537 40.152 ;
     RECT  9.209 7.488 10.549 14.232 ;
     RECT  9.853 15.456 10.549 16.92 ;
     RECT  9.641 67.104 10.549 67.896 ;
     RECT  9.587 77.52 10.573 77.544 ;
     RECT  9.997 53.568 10.577 54.696 ;
     RECT  10.508 61.824 10.595 62.76 ;
     RECT  9.491 43.296 10.609 43.32 ;
     RECT  9.877 44.448 10.609 46.104 ;
     RECT  10.249 58.368 10.649 59.256 ;
     RECT  10.249 88.848 10.684 105.048 ;
     RECT  10.549 66.864 10.685 67.896 ;
     RECT  10.684 93.024 10.685 105.048 ;
     RECT  10.361 18.672 10.717 18.84 ;
     RECT  9.893 19.824 10.717 19.848 ;
     RECT  10.573 77.52 10.717 78.072 ;
     RECT  10.037 30.72 10.757 30.984 ;
     RECT  10.537 37.584 10.757 40.536 ;
     RECT  10.609 43.296 10.757 46.104 ;
     RECT  10.505 0.528 10.787 0.552 ;
     RECT  10.685 104.304 10.787 105.048 ;
     RECT  10.105 47.664 10.789 47.88 ;
     RECT  9.155 64.032 10.789 64.056 ;
     RECT  9.731 57.024 10.825 57.048 ;
     RECT  10.717 77.52 10.829 79.464 ;
     RECT  10.717 18.672 10.835 19.848 ;
     RECT  10.549 7.488 10.861 16.92 ;
     RECT  10.259 25.104 10.861 28.2 ;
     RECT  10.757 43.296 10.865 45.72 ;
     RECT  10.685 67.68 10.865 67.896 ;
     RECT  10.829 78.672 10.901 79.464 ;
     RECT  9.713 32.736 10.933 33.72 ;
     RECT  10.649 59.232 10.937 59.256 ;
     RECT  10.684 88.848 10.937 91.8 ;
     RECT  10.685 93.024 10.937 103.32 ;
     RECT  9.605 1.728 10.969 1.752 ;
     RECT  10.861 25.104 10.969 28.344 ;
     RECT  10.861 7.488 10.973 17.544 ;
     RECT  10.865 67.68 10.973 67.848 ;
     RECT  9.857 71.472 10.973 72.168 ;
     RECT  10.937 88.848 10.973 89.736 ;
     RECT  10.901 78.672 10.979 78.792 ;
     RECT  9.923 50.256 11.005 52.008 ;
     RECT  10.001 87.792 11.005 87.816 ;
     RECT  10.973 67.68 11.009 67.752 ;
     RECT  10.433 3.216 11.041 6.024 ;
     RECT  10.973 7.488 11.081 17.064 ;
     RECT  10.289 20.976 11.081 23.352 ;
     RECT  10.979 78.768 11.081 78.792 ;
     RECT  11.041 3.216 11.113 6.12 ;
     RECT  11.081 7.488 11.113 14.232 ;
     RECT  10.787 104.88 11.116 105.048 ;
     RECT  11.081 15.264 11.117 17.064 ;
     RECT  10.835 18.816 11.149 19.848 ;
     RECT  11.081 20.976 11.149 21.288 ;
     RECT  10.933 32.544 11.153 33.72 ;
     RECT  10.969 1.728 11.219 1.8 ;
     RECT  10.969 25.104 11.297 28.728 ;
     RECT  10.937 90.96 11.333 91.8 ;
     RECT  10.865 43.296 11.365 44.472 ;
     RECT  10.595 62.688 11.365 62.76 ;
     RECT  10.789 64.032 11.365 64.104 ;
     RECT  10.789 46.752 11.441 47.88 ;
     RECT  10.825 57.024 11.441 57.672 ;
     RECT  11.113 3.216 11.459 14.232 ;
     RECT  11.117 15.264 11.459 15.672 ;
     RECT  10.757 37.584 11.461 39.624 ;
     RECT  11.401 41.04 11.473 41.064 ;
     RECT  11.473 41.04 11.485 41.16 ;
     RECT  10.289 34.8 11.509 35.64 ;
     RECT  11.459 15.264 11.513 15.624 ;
     RECT  11.461 36.672 11.513 39.624 ;
     RECT  10.865 45.696 11.513 45.72 ;
     RECT  11.365 62.688 11.537 64.104 ;
     RECT  10.741 65.52 11.537 65.544 ;
     RECT  11.459 3.216 11.549 13.704 ;
     RECT  11.537 62.688 11.603 65.544 ;
     RECT  11.509 34.704 11.621 35.64 ;
     RECT  11.603 64.32 11.621 65.544 ;
     RECT  11.297 25.104 11.653 28.344 ;
     RECT  10.757 30.96 11.653 30.984 ;
     RECT  11.153 32.544 11.653 33.048 ;
     RECT  11.621 34.896 11.653 35.64 ;
     RECT  11.513 36.672 11.653 38.568 ;
     RECT  11.653 34.896 11.657 38.568 ;
     RECT  11.485 41.136 11.689 41.16 ;
     RECT  10.973 72.144 11.689 72.168 ;
     RECT  11.441 46.752 11.693 47.688 ;
     RECT  11.005 50.016 11.693 52.008 ;
     RECT  11.513 39.6 11.729 39.624 ;
     RECT  10.577 53.568 11.729 53.88 ;
     RECT  11.081 22.368 11.747 23.352 ;
     RECT  11.66 75.792 11.747 75.816 ;
     RECT  11.603 62.688 11.761 63.24 ;
     RECT  11.365 42.768 11.765 44.472 ;
     RECT  10.829 77.52 11.837 77.544 ;
     RECT  11.657 34.992 11.873 38.568 ;
     RECT  11.653 55.488 11.873 55.512 ;
     RECT  11.333 91.68 11.9 91.8 ;
     RECT  10.937 93.36 11.9 103.32 ;
     RECT  11.621 65.376 11.909 65.544 ;
     RECT  11.116 104.88 11.941 104.904 ;
     RECT  11.329 60.96 11.945 60.984 ;
     RECT  11.9 91.68 11.945 103.32 ;
     RECT  11.693 47.04 11.981 47.688 ;
     RECT  11.005 87.792 11.981 88.344 ;
     RECT  11.945 91.68 11.987 94.92 ;
     RECT  11.549 3.216 12.017 13.176 ;
     RECT  11.987 91.68 12.017 91.8 ;
     RECT  11.149 18.816 12.049 21.288 ;
     RECT  11.653 24.528 12.053 28.344 ;
     RECT  11.693 50.256 12.053 52.008 ;
     RECT  12.017 91.68 12.089 91.752 ;
     RECT  11.689 41.136 12.121 41.784 ;
     RECT  11.873 36.48 12.125 38.568 ;
     RECT  11.945 95.904 12.125 103.176 ;
     RECT  11.941 104.832 12.125 104.904 ;
     RECT  11.893 0.192 12.157 0.216 ;
     RECT  11.987 93.312 12.161 94.92 ;
     RECT  11.219 1.728 12.193 1.752 ;
     RECT  12.085 2.784 12.193 2.856 ;
     RECT  11.747 22.752 12.197 23.352 ;
     RECT  12.125 104.832 12.227 104.856 ;
     RECT  12.053 27.456 12.445 28.344 ;
     RECT  11.009 67.68 12.445 67.704 ;
     RECT  12.049 18.816 12.469 21.72 ;
     RECT  11.725 29.616 12.476 29.64 ;
     RECT  11.653 30.96 12.476 33.048 ;
     RECT  11.765 43.824 12.517 44.472 ;
     RECT  11.441 57.024 12.517 57.336 ;
     RECT  10.973 89.712 12.517 89.736 ;
     RECT  11.513 15.456 12.613 15.624 ;
     RECT  12.476 29.616 12.613 33.048 ;
     RECT  11.113 82.992 12.625 83.016 ;
     RECT  11.117 16.896 12.697 17.064 ;
     RECT  12.613 15.456 12.709 15.864 ;
     RECT  12.697 16.896 12.709 17.64 ;
     RECT  12.017 3.936 12.805 13.176 ;
     RECT  12.157 78.72 12.841 78.744 ;
     RECT  12.625 82.992 12.841 83.832 ;
     RECT  11.621 64.32 12.877 64.344 ;
     RECT  11.909 65.376 12.877 65.4 ;
     RECT  12.517 89.712 12.877 90.552 ;
     RECT  12.089 91.68 12.877 91.704 ;
     RECT  12.805 3.936 12.913 13.416 ;
     RECT  12.841 78.72 12.913 79.224 ;
     RECT  12.841 82.992 12.985 84.12 ;
     RECT  12.157 0.192 12.989 0.312 ;
     RECT  12.913 3.936 13.013 13.608 ;
     RECT  12.709 15.456 13.013 17.64 ;
     RECT  12.985 82.992 13.045 84.36 ;
     RECT  10.181 85.392 13.045 85.416 ;
     RECT  12.877 86.448 13.045 86.472 ;
     RECT  12.877 89.712 13.045 91.704 ;
     RECT  12.769 59.28 13.052 59.304 ;
     RECT  12.445 61.008 13.052 61.032 ;
     RECT  12.469 18.768 13.057 21.72 ;
     RECT  11.981 87.792 13.057 87.96 ;
     RECT  13.045 89.328 13.057 91.704 ;
     RECT  12.053 24.528 13.093 26.472 ;
     RECT  12.445 27.456 13.093 28.536 ;
     RECT  12.337 76.704 13.129 76.728 ;
     RECT  11.873 34.992 13.201 35.016 ;
     RECT  12.193 1.728 13.208 2.856 ;
     RECT  13.013 3.936 13.208 17.64 ;
     RECT  13.057 18.768 13.208 21.768 ;
     RECT  12.197 22.752 13.208 23.304 ;
     RECT  13.093 24.528 13.208 28.536 ;
     RECT  12.613 29.616 13.208 34.008 ;
     RECT  13.201 34.992 13.208 35.208 ;
     RECT  12.125 36.48 13.208 37.656 ;
     RECT  13.093 39.696 13.208 39.72 ;
     RECT  12.121 41.136 13.208 42.744 ;
     RECT  12.517 43.824 13.208 45.192 ;
     RECT  11.981 47.664 13.208 47.688 ;
     RECT  12.053 51.216 13.208 52.008 ;
     RECT  11.729 53.856 13.208 53.88 ;
     RECT  12.517 55.872 13.208 57.336 ;
     RECT  13.052 59.28 13.208 61.032 ;
     RECT  11.761 62.304 13.208 63.24 ;
     RECT  12.877 64.32 13.208 65.4 ;
     RECT  12.445 67.68 13.208 68.424 ;
     RECT  11.689 72.144 13.208 72.456 ;
     RECT  11.689 74.688 13.208 74.712 ;
     RECT  13.129 76.704 13.208 77.304 ;
     RECT  12.913 78.72 13.208 79.464 ;
     RECT  13.045 82.992 13.208 85.416 ;
     RECT  13.045 86.448 13.208 86.76 ;
     RECT  13.057 87.792 13.208 91.704 ;
     RECT  12.161 93.312 13.208 94.296 ;
     RECT  12.125 96.192 13.208 103.176 ;
     RECT  12.989 0.288 13.235 0.312 ;
     RECT  13.208 1.728 13.312 103.692 ;
     RECT  13.312 1.728 13.385 103.422 ;
     RECT  13.385 1.824 13.504 103.422 ;
     RECT  13.504 1.824 13.523 1.848 ;
     RECT  13.504 48.672 13.565 48.792 ;
     RECT  13.504 83.856 13.565 84.36 ;
     RECT  13.504 3.12 13.619 16.008 ;
     RECT  13.504 53.568 13.619 54.456 ;
     RECT  13.504 86.016 13.673 86.76 ;
     RECT  13.504 44.448 13.681 47.208 ;
     RECT  13.504 30.24 13.709 33.048 ;
     RECT  13.504 34.608 13.715 35.976 ;
     RECT  13.504 87.936 13.715 88.056 ;
     RECT  13.504 89.232 13.715 91.848 ;
     RECT  13.715 34.608 13.817 34.776 ;
     RECT  13.681 44.448 13.817 45.336 ;
     RECT  13.504 95.664 13.889 95.688 ;
     RECT  13.504 24.672 13.925 29.112 ;
     RECT  13.565 83.856 13.925 84.168 ;
     RECT  13.504 94.656 13.955 94.68 ;
     RECT  13.619 53.568 13.997 53.88 ;
     RECT  13.504 78.672 13.997 79.224 ;
     RECT  13.715 89.232 13.997 91.08 ;
     RECT  13.504 66.432 14.105 68.376 ;
     RECT  13.504 80.832 14.105 80.856 ;
     RECT  13.997 91.056 14.147 91.08 ;
     RECT  13.504 96.672 14.177 98.472 ;
     RECT  13.997 79.056 14.213 79.224 ;
     RECT  13.715 35.952 14.243 35.976 ;
     RECT  13.997 89.232 14.243 90.072 ;
     RECT  13.504 93.168 14.243 93.576 ;
     RECT  14.243 89.664 14.249 90.072 ;
     RECT  14.243 93.552 14.285 93.576 ;
     RECT  14.177 96.672 14.285 98.184 ;
     RECT  13.504 40.992 14.321 43.272 ;
     RECT  14.105 66.432 14.357 67.704 ;
     RECT  13.504 37.056 14.393 39.432 ;
     RECT  14.321 40.992 14.393 42.696 ;
     RECT  13.681 46.608 14.393 47.208 ;
     RECT  13.504 60.384 14.429 61.896 ;
     RECT  14.285 96.672 14.435 98.088 ;
     RECT  13.504 17.616 14.497 18.6 ;
     RECT  13.504 73.344 14.501 73.368 ;
     RECT  14.393 37.056 14.533 39.384 ;
     RECT  13.504 56.304 14.533 56.328 ;
     RECT  13.619 14.592 14.537 16.008 ;
     RECT  13.619 3.12 14.573 13.128 ;
     RECT  13.504 64.128 14.573 65.208 ;
     RECT  13.504 75.6 14.573 75.816 ;
     RECT  14.497 17.04 14.579 18.6 ;
     RECT  14.537 14.592 14.605 15.48 ;
     RECT  14.573 3.12 14.641 8.52 ;
     RECT  13.504 101.568 14.641 101.784 ;
     RECT  13.709 30.24 14.645 31.608 ;
     RECT  14.579 17.04 14.681 18.024 ;
     RECT  14.641 101.472 14.681 101.784 ;
     RECT  13.925 24.672 14.713 28.728 ;
     RECT  14.533 56.304 14.713 57.192 ;
     RECT  14.497 59.04 14.713 59.064 ;
     RECT  14.393 40.992 14.717 42.648 ;
     RECT  13.504 70.08 14.717 70.296 ;
     RECT  13.673 86.016 14.753 86.04 ;
     RECT  14.681 101.472 14.753 101.688 ;
     RECT  13.997 53.856 14.785 53.88 ;
     RECT  14.645 30.432 14.821 31.608 ;
     RECT  14.785 53.856 14.821 55.176 ;
     RECT  14.713 56.304 14.821 59.064 ;
     RECT  14.821 53.856 14.825 59.064 ;
     RECT  14.821 30.432 14.857 31.752 ;
     RECT  13.709 32.736 14.857 33.048 ;
     RECT  14.393 46.752 14.861 47.208 ;
     RECT  14.717 70.272 14.861 70.296 ;
     RECT  14.573 75.792 14.861 75.816 ;
     RECT  14.753 101.472 14.861 101.496 ;
     RECT  13.504 99.696 14.867 100.488 ;
     RECT  14.717 40.992 14.893 41.016 ;
     RECT  14.825 53.856 14.905 57.192 ;
     RECT  14.867 100.176 14.905 100.488 ;
     RECT  14.573 64.992 14.929 65.208 ;
     RECT  14.905 56.304 14.969 57.192 ;
     RECT  14.929 64.992 14.969 66.408 ;
     RECT  13.817 34.608 15.037 34.632 ;
     RECT  13.504 77.28 15.061 77.304 ;
     RECT  14.357 67.68 15.107 67.704 ;
     RECT  14.249 89.664 15.107 89.688 ;
     RECT  14.605 14.496 15.109 15.48 ;
     RECT  13.504 19.632 15.109 21.768 ;
     RECT  13.504 22.752 15.109 23.304 ;
     RECT  15.037 34.608 15.109 34.728 ;
     RECT  14.429 60.384 15.113 61.08 ;
     RECT  13.504 51.984 15.145 52.2 ;
     RECT  14.681 17.04 15.155 17.784 ;
     RECT  14.713 24.528 15.155 28.728 ;
     RECT  15.145 51.312 15.185 52.2 ;
     RECT  14.969 65.136 15.185 66.408 ;
     RECT  15.185 51.312 15.229 52.152 ;
     RECT  14.857 30.432 15.253 33.048 ;
     RECT  15.109 14.256 15.257 15.48 ;
     RECT  14.825 58.176 15.325 59.064 ;
     RECT  15.113 60.384 15.325 60.408 ;
     RECT  14.905 100.224 15.325 100.488 ;
     RECT  14.573 9.504 15.401 13.128 ;
     RECT  14.717 42.144 15.433 42.648 ;
     RECT  15.325 58.176 15.437 60.408 ;
     RECT  15.109 19.632 15.443 23.304 ;
     RECT  15.061 77.28 15.452 77.448 ;
     RECT  14.533 36.624 15.469 39.384 ;
     RECT  14.893 40.464 15.469 41.016 ;
     RECT  15.452 77.28 15.493 77.544 ;
     RECT  14.641 2.544 15.509 8.52 ;
     RECT  15.493 77.232 15.539 77.544 ;
     RECT  13.504 50.112 15.541 50.136 ;
     RECT  15.155 25.056 15.545 28.728 ;
     RECT  13.817 44.448 15.548 45 ;
     RECT  15.469 62.784 15.581 62.808 ;
     RECT  15.253 30.432 15.587 33.288 ;
     RECT  13.565 48.672 15.613 48.696 ;
     RECT  15.548 44.448 15.649 45.432 ;
     RECT  14.861 46.752 15.649 46.92 ;
     RECT  15.257 14.496 15.683 15.48 ;
     RECT  15.587 31.872 15.685 33.288 ;
     RECT  15.109 34.608 15.685 34.776 ;
     RECT  13.925 83.856 15.685 83.88 ;
     RECT  15.509 3.12 15.725 8.52 ;
     RECT  15.587 30.432 15.731 30.456 ;
     RECT  15.685 31.872 15.731 34.776 ;
     RECT  15.443 19.632 15.761 22.152 ;
     RECT  15.649 44.448 15.761 46.92 ;
     RECT  15.469 36.624 15.82 41.016 ;
     RECT  15.82 36.624 15.825 40.488 ;
     RECT  15.731 32.304 15.829 34.776 ;
     RECT  15.325 100.224 15.829 100.872 ;
     RECT  14.677 92.304 15.833 92.328 ;
     RECT  13.715 88.032 15.901 88.056 ;
     RECT  15.761 19.632 15.937 19.656 ;
     RECT  15.613 48.672 15.973 49.128 ;
     RECT  15.541 50.112 15.973 50.424 ;
     RECT  15.937 73.92 15.973 73.944 ;
     RECT  15.932 75.888 15.973 75.912 ;
     RECT  15.539 77.232 15.973 77.448 ;
     RECT  15.683 14.496 15.977 14.616 ;
     RECT  14.435 96.672 16.009 97.272 ;
     RECT  15.973 75.888 16.019 77.448 ;
     RECT  15.155 17.616 16.021 17.784 ;
     RECT  15.937 18.768 16.021 19.656 ;
     RECT  14.905 53.856 16.021 55.176 ;
     RECT  16.021 53.376 16.049 55.176 ;
     RECT  16.021 17.616 16.067 19.656 ;
     RECT  15.433 42.144 16.076 42.744 ;
     RECT  15.761 44.448 16.076 46.392 ;
     RECT  16.067 19.632 16.077 19.656 ;
     RECT  15.577 66.72 16.081 66.744 ;
     RECT  15.865 68.4 16.081 68.952 ;
     RECT  14.213 79.2 16.085 79.224 ;
     RECT  16.049 53.376 16.093 54.744 ;
     RECT  16.081 66.72 16.115 68.952 ;
     RECT  15.725 7.248 16.117 8.52 ;
     RECT  15.401 9.504 16.117 12.36 ;
     RECT  15.437 60.384 16.117 60.408 ;
     RECT  16.069 69.936 16.117 69.96 ;
     RECT  16.067 17.616 16.121 18.168 ;
     RECT  15.545 25.056 16.121 28.2 ;
     RECT  16.115 66.72 16.121 68.424 ;
     RECT  16.117 69.936 16.156 70.44 ;
     RECT  15.977 14.496 16.157 14.52 ;
     RECT  16.117 60.384 16.157 60.552 ;
     RECT  15.901 88.032 16.157 88.392 ;
     RECT  16.076 42.144 16.163 46.392 ;
     RECT  15.973 62.16 16.165 62.184 ;
     RECT  15.757 93.456 16.225 93.48 ;
     RECT  16.019 76.368 16.252 77.448 ;
     RECT  16.156 70.272 16.297 70.44 ;
     RECT  15.229 52.128 16.333 52.152 ;
     RECT  16.117 7.248 16.369 12.36 ;
     RECT  15.973 47.616 16.373 50.424 ;
     RECT  16.081 81.36 16.373 81.384 ;
     RECT  16.333 51.888 16.405 52.152 ;
     RECT  16.093 53.376 16.405 54.504 ;
     RECT  15.437 58.176 16.409 59.352 ;
     RECT  16.369 7.248 16.441 12.456 ;
     RECT  16.121 25.056 16.441 26.76 ;
     RECT  14.969 57.072 16.441 57.192 ;
     RECT  16.409 58.176 16.441 59.256 ;
     RECT  15.685 83.76 16.441 83.88 ;
     RECT  16.441 57.072 16.451 59.256 ;
     RECT  16.451 57.072 16.481 58.824 ;
     RECT  16.412 72.864 16.499 72.888 ;
     RECT  16.373 50.16 16.501 50.424 ;
     RECT  16.405 51.888 16.501 54.504 ;
     RECT  16.297 70.272 16.501 70.728 ;
     RECT  15.469 71.808 16.501 71.832 ;
     RECT  16.441 82.752 16.501 83.88 ;
     RECT  15.577 84.912 16.501 84.936 ;
     RECT  16.009 96.48 16.501 97.272 ;
     RECT  16.045 98.64 16.501 98.664 ;
     RECT  15.865 16.512 16.513 16.536 ;
     RECT  16.121 27.84 16.513 28.2 ;
     RECT  15.637 29.424 16.513 29.448 ;
     RECT  16.121 66.72 16.513 68.088 ;
     RECT  16.513 15.744 16.517 16.536 ;
     RECT  16.165 61.584 16.547 62.184 ;
     RECT  16.501 82.752 16.547 84.936 ;
     RECT  16.501 96.48 16.547 98.664 ;
     RECT  15.725 3.12 16.549 6.072 ;
     RECT  15.829 32.304 16.549 35.592 ;
     RECT  15.825 36.624 16.549 40.44 ;
     RECT  15.185 65.136 16.549 65.544 ;
     RECT  16.513 66.624 16.549 68.088 ;
     RECT  16.121 18.144 16.553 18.168 ;
     RECT  16.547 96.48 16.553 97.944 ;
     RECT  16.501 63.264 16.556 63.288 ;
     RECT  16.549 2.496 16.589 6.072 ;
     RECT  16.547 82.752 16.589 84.36 ;
     RECT  16.441 7.248 16.595 12.744 ;
     RECT  16.549 32.304 16.595 40.44 ;
     RECT  16.549 65.136 16.595 68.088 ;
     RECT  16.556 63.264 16.597 63.816 ;
     RECT  16.513 14.208 16.625 14.232 ;
     RECT  16.595 32.304 16.625 34.68 ;
     RECT  16.597 63.264 16.625 64.44 ;
     RECT  16.625 32.736 16.643 34.68 ;
     RECT  16.625 63.792 16.643 64.44 ;
     RECT  16.595 65.52 16.643 68.088 ;
     RECT  15.443 23.136 16.645 23.304 ;
     RECT  16.441 25.008 16.645 26.76 ;
     RECT  16.513 27.84 16.661 29.448 ;
     RECT  16.645 23.136 16.697 26.76 ;
     RECT  16.501 50.16 16.697 54.504 ;
     RECT  16.225 93.024 16.721 93.48 ;
     RECT  16.553 96.48 16.741 96.888 ;
     RECT  16.661 28.176 16.765 29.448 ;
     RECT  16.501 70.272 16.769 71.832 ;
     RECT  16.081 95.04 16.787 95.064 ;
     RECT  16.163 44.064 16.796 46.392 ;
     RECT  16.595 7.248 16.805 12.552 ;
     RECT  16.796 44.064 16.805 46.536 ;
     RECT  16.373 47.616 16.805 49.128 ;
     RECT  16.769 71.232 16.805 71.832 ;
     RECT  16.549 91.056 16.805 91.08 ;
     RECT  16.721 93.024 16.805 94.056 ;
     RECT  16.157 88.032 16.835 88.056 ;
     RECT  16.805 46.512 16.837 46.536 ;
     RECT  16.805 47.616 16.837 48.696 ;
     RECT  15.973 73.92 16.837 74.616 ;
     RECT  16.157 60.528 16.873 60.552 ;
     RECT  16.837 73.92 16.877 74.712 ;
     RECT  16.595 36.384 16.883 40.44 ;
     RECT  16.837 46.512 16.883 48.696 ;
     RECT  16.081 103.152 16.909 103.176 ;
     RECT  16.163 42.144 16.913 43.032 ;
     RECT  15.829 100.224 16.981 101.304 ;
     RECT  16.883 36.384 16.985 36.648 ;
     RECT  16.883 46.848 16.985 47.976 ;
     RECT  16.805 44.064 17.021 45.528 ;
     RECT  16.913 42.624 17.057 43.032 ;
     RECT  16.697 50.592 17.057 54.504 ;
     RECT  16.697 23.136 17.093 26.376 ;
     RECT  16.945 87.072 17.093 87.096 ;
     RECT  16.837 19.728 17.125 19.752 ;
     RECT  15.761 21.12 17.125 22.152 ;
     RECT  16.597 31.2 17.125 31.224 ;
     RECT  16.517 15.744 17.129 15.768 ;
     RECT  16.765 28.176 17.129 30.216 ;
     RECT  17.057 50.592 17.129 53.88 ;
     RECT  16.643 64.416 17.129 64.44 ;
     RECT  17.129 28.272 17.161 30.216 ;
     RECT  17.125 31.2 17.161 31.704 ;
     RECT  16.117 78.672 17.161 78.696 ;
     RECT  16.873 60.528 17.165 61.272 ;
     RECT  17.161 78.672 17.201 78.936 ;
     RECT  16.909 102.528 17.237 103.176 ;
     RECT  16.981 99.744 17.305 101.304 ;
     RECT  17.237 102.528 17.305 102.6 ;
     RECT  16.729 16.752 17.317 17.016 ;
     RECT  17.125 19.728 17.317 22.152 ;
     RECT  17.057 43.008 17.345 43.032 ;
     RECT  16.643 67.008 17.345 68.088 ;
     RECT  16.805 93.024 17.413 93.768 ;
     RECT  17.317 16.752 17.453 17.88 ;
     RECT  17.129 50.832 17.453 51.24 ;
     RECT  16.741 96.432 17.453 96.888 ;
     RECT  16.643 34.08 17.489 34.68 ;
     RECT  16.837 55.92 17.521 55.944 ;
     RECT  16.252 76.368 17.521 76.392 ;
     RECT  16.252 77.424 17.521 77.448 ;
     RECT  16.765 80.928 17.521 80.952 ;
     RECT  17.453 16.752 17.525 17.736 ;
     RECT  17.521 55.92 17.557 56.472 ;
     RECT  17.521 80.4 17.561 80.952 ;
     RECT  17.305 99.744 17.564 102.6 ;
     RECT  17.269 14.112 17.597 14.136 ;
     RECT  17.317 19.2 17.597 22.152 ;
     RECT  16.589 2.496 17.653 5.112 ;
     RECT  16.883 37.968 17.701 40.44 ;
     RECT  17.597 20.16 17.737 22.152 ;
     RECT  17.093 23.136 17.737 23.4 ;
     RECT  16.805 7.632 17.809 12.552 ;
     RECT  17.557 55.776 17.881 56.472 ;
     RECT  17.093 24.912 17.917 26.376 ;
     RECT  16.877 74.112 17.917 74.712 ;
     RECT  16.553 97.92 17.989 97.944 ;
     RECT  16.481 57.552 18.017 58.824 ;
     RECT  17.701 37.968 18.025 40.92 ;
     RECT  17.021 44.352 18.025 45.528 ;
     RECT  17.413 6.288 18.097 6.312 ;
     RECT  17.809 7.632 18.097 13.128 ;
     RECT  18.025 37.968 18.097 41.592 ;
     RECT  16.805 71.232 18.169 71.256 ;
     RECT  17.561 80.4 18.169 80.424 ;
     RECT  17.881 55.488 18.205 56.472 ;
     RECT  18.017 57.552 18.205 59.304 ;
     RECT  18.097 86.352 18.205 86.376 ;
     RECT  17.377 15.36 18.229 15.384 ;
     RECT  16.589 82.752 18.229 83.592 ;
     RECT  16.643 32.736 18.241 33.096 ;
     RECT  18.205 86.352 18.277 86.472 ;
     RECT  17.917 24.912 18.313 26.808 ;
     RECT  17.665 34.8 18.349 34.824 ;
     RECT  17.201 78.912 18.349 78.936 ;
     RECT  18.169 79.968 18.349 80.424 ;
     RECT  17.737 20.16 18.373 23.4 ;
     RECT  18.313 24.384 18.373 26.808 ;
     RECT  18.025 43.488 18.421 45.528 ;
     RECT  17.521 76.368 18.421 77.448 ;
     RECT  17.413 92.928 18.421 93.768 ;
     RECT  17.453 50.832 18.457 51.192 ;
     RECT  18.421 43.104 18.469 45.528 ;
     RECT  17.917 74.112 18.493 75.144 ;
     RECT  17.453 96.48 18.529 96.888 ;
     RECT  18.349 34.8 18.565 34.92 ;
     RECT  18.097 37.968 18.565 41.736 ;
     RECT  18.469 42.72 18.565 45.528 ;
     RECT  18.385 64.368 18.565 64.392 ;
     RECT  17.564 99.696 18.565 102.6 ;
     RECT  17.525 17.712 18.601 17.736 ;
     RECT  17.653 2.496 18.608 5.16 ;
     RECT  18.097 6.288 18.608 13.128 ;
     RECT  18.229 14.784 18.608 15.384 ;
     RECT  18.601 17.616 18.608 17.736 ;
     RECT  18.277 18.96 18.608 18.984 ;
     RECT  18.373 20.16 18.608 26.808 ;
     RECT  17.161 28.272 18.608 31.704 ;
     RECT  18.241 32.736 18.608 33.384 ;
     RECT  18.565 34.8 18.608 34.968 ;
     RECT  16.985 36.48 18.608 36.648 ;
     RECT  18.565 37.968 18.608 45.528 ;
     RECT  16.985 47.616 18.608 47.976 ;
     RECT  18.457 50.4 18.608 51.192 ;
     RECT  17.129 52.272 18.608 53.88 ;
     RECT  18.205 55.488 18.608 59.304 ;
     RECT  17.165 60.528 18.608 61.176 ;
     RECT  17.989 62.544 18.608 62.568 ;
     RECT  18.565 63.84 18.608 64.392 ;
     RECT  16.643 65.52 18.608 65.736 ;
     RECT  17.345 67.248 18.608 68.088 ;
     RECT  17.413 69.456 18.608 69.48 ;
     RECT  18.169 71.232 18.608 71.4 ;
     RECT  18.493 74.064 18.608 75.144 ;
     RECT  18.421 76.32 18.608 77.448 ;
     RECT  18.349 78.912 18.608 80.424 ;
     RECT  18.229 82.032 18.608 83.592 ;
     RECT  18.277 86.256 18.608 86.472 ;
     RECT  17.953 88.08 18.608 88.104 ;
     RECT  17.797 89.088 18.608 89.112 ;
     RECT  18.421 92.784 18.608 93.768 ;
     RECT  18.529 96 18.608 96.888 ;
     RECT  17.989 97.92 18.608 98.376 ;
     RECT  18.565 99.696 18.608 102.696 ;
     RECT  18.608 2.148 18.712 103.692 ;
     RECT  18.712 2.418 18.904 103.422 ;
     RECT  18.904 20.304 18.929 21.528 ;
     RECT  18.904 7.632 19.001 8.52 ;
     RECT  18.904 22.8 19.001 23.4 ;
     RECT  18.904 71.376 19.001 78.12 ;
     RECT  18.904 42 19.073 43.128 ;
     RECT  18.904 68.784 19.073 69.864 ;
     RECT  19.001 7.632 19.109 8.28 ;
     RECT  18.904 52.56 19.109 59.592 ;
     RECT  18.904 60.816 19.109 61.56 ;
     RECT  18.904 92.352 19.109 93.768 ;
     RECT  18.904 46.992 19.145 51.192 ;
     RECT  19.001 71.376 19.145 74.712 ;
     RECT  18.904 95.088 19.18 98.04 ;
     RECT  18.904 36.048 19.181 38.952 ;
     RECT  19.109 61.536 19.276 61.56 ;
     RECT  18.904 62.544 19.289 65.592 ;
     RECT  19.109 7.968 19.331 8.28 ;
     RECT  19.001 76.08 19.42 78.12 ;
     RECT  19.109 53.568 19.427 59.592 ;
     RECT  18.904 81.456 19.427 83.592 ;
     RECT  18.904 24.384 19.433 25.272 ;
     RECT  18.904 99.168 19.433 100.344 ;
     RECT  18.904 28.272 19.469 35.064 ;
     RECT  19.469 28.368 19.475 35.064 ;
     RECT  19.181 36.048 19.505 38.136 ;
     RECT  19.145 46.992 19.505 47.736 ;
     RECT  19.427 81.456 19.505 81.48 ;
     RECT  19.475 28.368 19.541 33.048 ;
     RECT  18.904 66.768 19.541 67.704 ;
     RECT  18.904 90.816 19.577 90.936 ;
     RECT  19.433 99.168 19.577 100.104 ;
     RECT  19.145 71.808 19.613 74.712 ;
     RECT  19.613 72.288 19.619 74.712 ;
     RECT  18.904 84.912 19.619 86.376 ;
     RECT  18.904 5.664 19.685 5.688 ;
     RECT  19.433 24.384 19.685 25.224 ;
     RECT  19.475 34.32 19.713 35.064 ;
     RECT  18.904 9.504 19.757 11.976 ;
     RECT  19.541 29.52 19.793 33.048 ;
     RECT  19.577 90.816 19.793 90.84 ;
     RECT  19.109 92.352 19.793 92.712 ;
     RECT  19.713 34.656 19.829 35.064 ;
     RECT  19.619 84.912 19.859 86.184 ;
     RECT  19.18 95.088 19.865 97.032 ;
     RECT  19.427 57.696 19.897 59.592 ;
     RECT  18.904 79.344 19.897 80.088 ;
     RECT  19.505 36.048 19.937 36.072 ;
     RECT  18.904 40.032 19.937 40.44 ;
     RECT  19.145 48.864 19.937 51.192 ;
     RECT  19.427 53.568 19.937 56.52 ;
     RECT  19.109 93.744 19.957 93.768 ;
     RECT  19.865 95.088 19.957 95.112 ;
     RECT  19.289 62.544 19.969 63.864 ;
     RECT  19.331 7.968 20.009 7.992 ;
     RECT  19.897 57.696 20.009 60.456 ;
     RECT  19.289 64.896 20.009 65.592 ;
     RECT  19.957 93.744 20.044 95.112 ;
     RECT  19.937 50.4 20.045 51.192 ;
     RECT  19.937 53.568 20.045 56.088 ;
     RECT  19.865 96.192 20.045 97.032 ;
     RECT  19.619 72.96 20.077 74.712 ;
     RECT  19.18 98.016 20.081 98.04 ;
     RECT  18.904 13.008 20.108 13.128 ;
     RECT  18.904 44.448 20.108 45.528 ;
     RECT  19.505 46.992 20.113 47.304 ;
     RECT  20.108 13.008 20.117 13.608 ;
     RECT  20.117 13.056 20.149 13.608 ;
     RECT  19.505 37.056 20.153 38.136 ;
     RECT  19.073 68.784 20.153 69.576 ;
     RECT  18.929 20.304 20.185 21.192 ;
     RECT  20.045 55.104 20.189 56.088 ;
     RECT  20.149 13.056 20.195 14.28 ;
     RECT  18.904 17.616 20.225 19.08 ;
     RECT  19.859 84.912 20.225 84.936 ;
     RECT  19.001 23.184 20.257 23.4 ;
     RECT  19.685 24.384 20.257 24.408 ;
     RECT  18.904 2.736 20.261 4.536 ;
     RECT  18.904 15.36 20.261 16.536 ;
     RECT  20.153 37.392 20.293 38.136 ;
     RECT  19.897 79.248 20.293 80.088 ;
     RECT  20.045 96.192 20.333 96.984 ;
     RECT  19.829 34.8 20.341 35.064 ;
     RECT  20.261 16.224 20.365 16.536 ;
     RECT  20.225 17.616 20.365 18.744 ;
     RECT  20.153 69.312 20.365 69.576 ;
     RECT  20.185 70.56 20.365 70.584 ;
     RECT  19.793 29.52 20.369 32.904 ;
     RECT  19.427 82.656 20.369 83.592 ;
     RECT  20.341 34.8 20.387 35.928 ;
     RECT  20.387 34.8 20.405 34.824 ;
     RECT  19.757 9.504 20.437 9.72 ;
     RECT  20.369 82.656 20.477 82.824 ;
     RECT  20.185 20.16 20.492 21.192 ;
     RECT  19.897 22.176 20.492 22.2 ;
     RECT  20.293 78.528 20.531 80.088 ;
     RECT  18.904 26.352 20.545 26.76 ;
     RECT  20.261 2.736 20.549 3.576 ;
     RECT  20.257 23.184 20.549 24.408 ;
     RECT  20.369 31.392 20.549 32.904 ;
     RECT  20.531 79.248 20.549 80.088 ;
     RECT  20.437 8.688 20.579 9.72 ;
     RECT  20.365 16.224 20.579 18.744 ;
     RECT  20.333 96.384 20.579 96.984 ;
     RECT  19.577 99.168 20.579 99.192 ;
     RECT  20.545 26.352 20.581 26.808 ;
     RECT  20.195 13.056 20.585 13.08 ;
     RECT  19.541 28.368 20.585 28.392 ;
     RECT  19.073 42 20.617 42.6 ;
     RECT  20.579 96.576 20.62 96.984 ;
     RECT  20.579 16.224 20.621 17.496 ;
     RECT  20.617 42 20.629 42.936 ;
     RECT  20.108 43.92 20.629 45.528 ;
     RECT  20.369 29.52 20.653 29.544 ;
     RECT  20.581 25.632 20.668 26.808 ;
     RECT  19.109 52.56 20.689 52.584 ;
     RECT  20.533 7.44 20.725 7.464 ;
     RECT  20.621 16.224 20.729 17.208 ;
     RECT  20.549 32.448 20.729 32.904 ;
     RECT  20.387 35.904 20.729 35.928 ;
     RECT  20.725 7.344 20.761 7.464 ;
     RECT  20.689 5.664 20.773 5.688 ;
     RECT  20.492 20.16 20.828 22.2 ;
     RECT  20.549 23.184 20.828 24.312 ;
     RECT  20.689 52.512 20.833 52.584 ;
     RECT  20.668 26.352 20.869 26.808 ;
     RECT  20.077 72.96 20.869 74.856 ;
     RECT  20.329 88.896 20.869 88.92 ;
     RECT  20.653 29.04 20.873 29.544 ;
     RECT  18.904 102.912 20.873 102.936 ;
     RECT  19.969 62.064 20.905 63.864 ;
     RECT  20.009 64.896 20.905 65.016 ;
     RECT  19.793 92.688 20.909 92.712 ;
     RECT  20.044 95.088 20.909 95.112 ;
     RECT  20.629 42 20.917 45.528 ;
     RECT  20.113 46.704 20.917 47.304 ;
     RECT  20.533 100.464 20.965 100.488 ;
     RECT  20.044 93.744 21.011 93.768 ;
     RECT  20.189 55.632 21.013 56.088 ;
     RECT  20.195 14.256 21.017 14.28 ;
     RECT  20.729 16.512 21.017 17.208 ;
     RECT  19.859 86.16 21.017 86.184 ;
     RECT  21.017 16.512 21.053 16.536 ;
     RECT  20.965 90.912 21.053 90.936 ;
     RECT  19.541 67.68 21.061 67.704 ;
     RECT  20.833 52.032 21.107 52.584 ;
     RECT  20.869 88.896 21.107 89.88 ;
     RECT  20.293 37.392 21.109 38.472 ;
     RECT  21.013 55.632 21.109 56.376 ;
     RECT  20.045 53.568 21.125 53.88 ;
     RECT  20.869 72.672 21.125 74.856 ;
     RECT  19.42 76.08 21.125 77.304 ;
     RECT  20.965 100.464 21.155 101.064 ;
     RECT  20.365 69.312 21.161 70.584 ;
     RECT  20.62 96.576 21.161 96.6 ;
     RECT  21.161 69.312 21.193 69.96 ;
     RECT  21.109 37.392 21.196 39.336 ;
     RECT  19.937 40.368 21.229 40.44 ;
     RECT  20.437 66.144 21.269 66.168 ;
     RECT  21.107 88.896 21.269 88.92 ;
     RECT  20.917 42 21.337 47.304 ;
     RECT  21.109 55.632 21.337 57.048 ;
     RECT  20.009 58.032 21.337 60.456 ;
     RECT  20.905 62.064 21.34 65.016 ;
     RECT  21.337 42 21.341 47.496 ;
     RECT  21.061 50.544 21.373 50.568 ;
     RECT  20.761 6.816 21.377 7.464 ;
     RECT  21.155 100.464 21.377 100.488 ;
     RECT  20.159 87.696 21.413 87.72 ;
     RECT  21.341 42.768 21.445 47.496 ;
     RECT  19.937 48.864 21.445 48.888 ;
     RECT  21.373 50.544 21.445 50.904 ;
     RECT  21.061 67.68 21.445 67.8 ;
     RECT  20.549 31.392 21.449 31.416 ;
     RECT  21.196 37.392 21.449 38.472 ;
     RECT  19.757 10.896 21.485 11.976 ;
     RECT  21.193 68.784 21.491 69.96 ;
     RECT  20.477 82.656 21.517 82.68 ;
     RECT  21.445 50.544 21.589 50.952 ;
     RECT  21.517 81.744 21.589 82.68 ;
     RECT  20.473 84.096 21.589 84.264 ;
     RECT  20.579 9.504 21.593 9.72 ;
     RECT  20.828 20.16 21.593 24.312 ;
     RECT  21.337 55.632 21.617 60.456 ;
     RECT  21.553 34.512 21.625 34.536 ;
     RECT  21.589 81.744 21.625 84.264 ;
     RECT  21.068 102.096 21.625 102.12 ;
     RECT  20.549 79.248 21.635 79.656 ;
     RECT  20.725 80.64 21.635 80.712 ;
     RECT  21.625 81.744 21.635 85.128 ;
     RECT  20.797 98.928 21.644 98.952 ;
     RECT  21.377 6.816 21.661 6.84 ;
     RECT  21.125 76.32 21.665 77.304 ;
     RECT  21.34 62.064 21.683 63.336 ;
     RECT  20.729 32.736 21.697 32.904 ;
     RECT  21.625 34.416 21.697 34.536 ;
     RECT  21.301 36.096 21.697 36.12 ;
     RECT  21.617 55.632 21.701 60.984 ;
     RECT  21.644 98.928 21.701 99.192 ;
     RECT  20.869 26.352 21.733 27.096 ;
     RECT  21.229 39.504 21.769 40.44 ;
     RECT  21.661 6.768 21.805 6.84 ;
     RECT  21.193 13.008 21.805 13.032 ;
     RECT  21.107 52.512 21.805 52.584 ;
     RECT  21.125 53.568 21.805 53.592 ;
     RECT  21.733 97.536 21.82 97.56 ;
     RECT  21.635 79.248 21.841 79.272 ;
     RECT  21.593 20.16 21.877 24.072 ;
     RECT  21.449 37.392 21.877 38.04 ;
     RECT  21.701 55.632 21.877 60.072 ;
     RECT  21.683 62.064 21.877 62.856 ;
     RECT  21.625 102 21.877 102.12 ;
     RECT  21.445 42.768 21.881 48.888 ;
     RECT  20.549 2.88 21.913 3.576 ;
     RECT  21.445 67.536 21.913 67.8 ;
     RECT  21.881 42.912 21.917 48.888 ;
     RECT  20.873 29.52 21.932 29.544 ;
     RECT  21.697 31.92 21.949 32.904 ;
     RECT  21.697 34.416 21.949 36.12 ;
     RECT  21.404 71.04 21.949 71.064 ;
     RECT  21.665 77.28 21.949 77.304 ;
     RECT  21.877 102 21.949 102.6 ;
     RECT  21.932 29.52 21.973 30.024 ;
     RECT  21.589 50.544 21.985 51 ;
     RECT  21.949 71.04 22.021 71.496 ;
     RECT  21.125 72.672 22.021 74.04 ;
     RECT  21.635 85.104 22.057 85.128 ;
     RECT  21.769 39.504 22.061 40.92 ;
     RECT  21.973 28.464 22.097 28.488 ;
     RECT  21.877 55.488 22.097 60.072 ;
     RECT  21.913 66.72 22.097 67.8 ;
     RECT  21.805 6.576 22.129 6.84 ;
     RECT  21.877 20.064 22.133 24.072 ;
     RECT  21.485 10.896 22.165 11.016 ;
     RECT  22.021 71.04 22.165 74.04 ;
     RECT  22.165 10.8 22.201 11.016 ;
     RECT  21.491 69.504 22.201 69.96 ;
     RECT  22.165 71.04 22.201 74.712 ;
     RECT  21.625 96.288 22.201 96.312 ;
     RECT  21.949 31.92 22.205 36.12 ;
     RECT  21.685 100.32 22.205 100.344 ;
     RECT  21.917 43.824 22.211 48.888 ;
     RECT  21.841 79.056 22.213 79.272 ;
     RECT  22.165 90 22.213 90.024 ;
     RECT  21.913 2.88 22.237 3.96 ;
     RECT  21.805 52.512 22.237 53.592 ;
     RECT  22.201 69.504 22.241 74.712 ;
     RECT  22.213 90 22.259 90.648 ;
     RECT  21.635 80.688 22.273 80.712 ;
     RECT  22.237 2.88 22.277 4.44 ;
     RECT  22.061 39.504 22.277 40.344 ;
     RECT  22.133 20.064 22.307 23.352 ;
     RECT  20.579 18.48 22.309 18.744 ;
     RECT  21.877 61.632 22.349 62.856 ;
     RECT  22.307 20.064 22.385 21.048 ;
     RECT  21.985 50.544 22.412 51.432 ;
     RECT  22.237 52.512 22.412 53.928 ;
     RECT  22.349 62.064 22.421 62.856 ;
     RECT  21.697 88.32 22.421 88.776 ;
     RECT  22.412 50.544 22.453 53.928 ;
     RECT  21.805 12.816 22.489 13.032 ;
     RECT  21.973 29.52 22.489 30.84 ;
     RECT  22.241 69.504 22.529 72.024 ;
     RECT  22.421 88.32 22.529 88.536 ;
     RECT  22.273 80.688 22.547 81.24 ;
     RECT  21.635 82.272 22.547 83.64 ;
     RECT  22.309 18.48 22.561 18.792 ;
     RECT  22.453 8.112 22.633 8.136 ;
     RECT  22.097 55.488 22.637 58.68 ;
     RECT  22.633 8.112 22.669 8.184 ;
     RECT  22.205 32.736 22.669 36.12 ;
     RECT  21.877 37.2 22.669 38.04 ;
     RECT  22.201 96.144 22.669 96.312 ;
     RECT  22.201 97.488 22.669 97.512 ;
     RECT  22.547 83.088 22.691 83.64 ;
     RECT  22.453 50.544 22.709 54.168 ;
     RECT  22.093 16.56 22.741 16.584 ;
     RECT  22.421 62.16 22.741 62.856 ;
     RECT  21.949 77.28 22.741 77.544 ;
     RECT  22.529 69.504 22.745 69.96 ;
     RECT  22.057 85.104 22.745 86.088 ;
     RECT  22.277 39.504 22.777 39.624 ;
     RECT  22.259 90.528 22.777 90.648 ;
     RECT  22.741 16.56 22.781 17.064 ;
     RECT  22.385 20.544 22.787 21.048 ;
     RECT  22.489 29.04 22.787 30.84 ;
     RECT  22.669 8.112 22.789 8.472 ;
     RECT  22.777 90.528 22.789 91.512 ;
     RECT  22.021 93.168 22.789 93.192 ;
     RECT  22.489 12.48 22.805 13.032 ;
     RECT  21.593 9.504 22.813 9.528 ;
     RECT  22.211 43.872 22.813 48.888 ;
     RECT  22.709 50.544 22.813 53.928 ;
     RECT  22.805 12.48 22.821 13.128 ;
     RECT  21.265 14.208 22.821 14.232 ;
     RECT  22.129 6.384 22.835 6.84 ;
     RECT  22.789 90.528 22.835 93.48 ;
     RECT  22.669 96.144 22.835 97.512 ;
     RECT  22.201 10.704 22.837 11.016 ;
     RECT  22.821 12.48 22.837 14.232 ;
     RECT  22.669 32.736 22.837 38.04 ;
     RECT  22.777 39.36 22.837 39.624 ;
     RECT  22.277 3.552 22.849 4.44 ;
     RECT  22.691 83.616 22.853 83.64 ;
     RECT  21.949 102 22.885 103.224 ;
     RECT  22.835 90.528 22.889 92.328 ;
     RECT  22.849 3.552 22.921 4.824 ;
     RECT  21.733 25.488 22.961 27.096 ;
     RECT  22.213 78.912 22.961 79.272 ;
     RECT  22.837 32.736 22.979 39.624 ;
     RECT  21.34 64.368 22.988 65.016 ;
     RECT  22.961 79.152 22.993 79.272 ;
     RECT  22.789 7.92 22.997 8.472 ;
     RECT  22.741 62.16 23.029 63.288 ;
     RECT  22.988 64.368 23.029 65.88 ;
     RECT  22.529 88.32 23.101 88.44 ;
     RECT  22.097 67.104 23.125 67.8 ;
     RECT  22.885 68.784 23.125 68.808 ;
     RECT  22.745 85.92 23.125 86.088 ;
     RECT  22.849 87.12 23.125 87.144 ;
     RECT  23.125 67.104 23.209 68.808 ;
     RECT  22.241 73.92 23.245 74.712 ;
     RECT  22.741 77.28 23.245 77.928 ;
     RECT  22.453 95.04 23.245 95.064 ;
     RECT  22.835 96.144 23.245 97.224 ;
     RECT  22.837 10.704 23.281 14.232 ;
     RECT  22.813 9.504 23.317 9.624 ;
     RECT  23.281 10.704 23.317 14.376 ;
     RECT  22.307 22.224 23.353 23.352 ;
     RECT  23.245 73.92 23.389 75.24 ;
     RECT  23.245 95.04 23.389 97.224 ;
     RECT  23.317 9.504 23.425 14.376 ;
     RECT  22.561 18.48 23.425 19.56 ;
     RECT  22.787 29.088 23.497 30.84 ;
     RECT  22.835 93.456 23.533 93.48 ;
     RECT  23.389 94.656 23.533 97.224 ;
     RECT  23.029 62.16 23.569 65.88 ;
     RECT  23.209 66.864 23.569 68.808 ;
     RECT  22.745 69.792 23.605 69.96 ;
     RECT  22.529 70.944 23.605 72.024 ;
     RECT  23.569 62.16 23.677 68.808 ;
     RECT  22.997 7.92 23.749 8.184 ;
     RECT  22.547 80.688 23.749 80.712 ;
     RECT  23.389 73.776 23.785 75.24 ;
     RECT  23.245 76.752 23.785 77.928 ;
     RECT  23.749 80.688 23.785 81.624 ;
     RECT  22.921 3.552 23.821 6.12 ;
     RECT  23.353 22.224 23.821 23.592 ;
     RECT  22.813 43.872 23.821 49.272 ;
     RECT  23.785 73.776 23.857 77.928 ;
     RECT  23.677 61.2 23.893 68.808 ;
     RECT  23.605 69.792 23.893 72.024 ;
     RECT  22.781 16.608 23.929 17.064 ;
     RECT  23.857 83.616 23.929 83.64 ;
     RECT  23.857 84.624 23.929 84.648 ;
     RECT  23.533 93.456 23.965 97.224 ;
     RECT  22.961 25.488 24.001 26.376 ;
     RECT  23.821 2.832 24.008 6.12 ;
     RECT  23.749 7.44 24.008 8.184 ;
     RECT  23.425 9.504 24.008 15.048 ;
     RECT  23.929 16.608 24.008 17.112 ;
     RECT  23.425 18.48 24.008 19.656 ;
     RECT  22.787 20.88 24.008 21.048 ;
     RECT  23.821 22.224 24.008 23.976 ;
     RECT  24.001 25.2 24.008 26.376 ;
     RECT  23.965 27.888 24.008 27.912 ;
     RECT  23.497 29.088 24.008 30.936 ;
     RECT  22.979 32.736 24.008 38.52 ;
     RECT  22.979 39.6 24.008 39.624 ;
     RECT  23.497 41.136 24.008 41.16 ;
     RECT  23.029 42.576 24.008 42.6 ;
     RECT  23.821 43.824 24.008 49.272 ;
     RECT  22.813 50.448 24.008 53.928 ;
     RECT  22.637 55.776 24.008 58.68 ;
     RECT  22.097 59.808 24.008 60.072 ;
     RECT  23.893 61.2 24.008 72.024 ;
     RECT  23.857 73.632 24.008 77.928 ;
     RECT  22.993 79.152 24.008 79.512 ;
     RECT  23.785 80.688 24.008 82.2 ;
     RECT  23.929 83.616 24.008 84.648 ;
     RECT  23.125 85.92 24.008 87.144 ;
     RECT  23.101 88.128 24.008 88.44 ;
     RECT  22.889 90.528 24.008 91.512 ;
     RECT  23.965 93.456 24.008 97.944 ;
     RECT  21.701 99.168 24.008 99.192 ;
     RECT  22.885 101.424 24.008 103.224 ;
     RECT  24.008 2.148 24.112 103.692 ;
     RECT  24.112 2.418 24.304 103.422 ;
     RECT  24.304 25.2 24.329 27.912 ;
     RECT  24.304 82.176 24.419 84.36 ;
     RECT  24.304 5.04 24.437 7.176 ;
     RECT  24.304 40.8 24.46 41.208 ;
     RECT  24.304 16.368 24.467 19.752 ;
     RECT  24.46 41.088 24.473 41.208 ;
     RECT  24.419 82.176 24.473 83.784 ;
     RECT  24.304 95.904 24.473 95.928 ;
     RECT  24.329 25.488 24.515 27.912 ;
     RECT  24.304 42.528 24.515 46.824 ;
     RECT  24.467 16.608 24.545 19.752 ;
     RECT  24.304 38.4 24.545 39.624 ;
     RECT  24.515 42.768 24.545 46.824 ;
     RECT  24.545 42.768 24.581 46.632 ;
     RECT  24.304 48.144 24.581 51.384 ;
     RECT  24.304 52.512 24.581 57.72 ;
     RECT  24.304 20.88 24.617 20.904 ;
     RECT  24.515 25.584 24.617 27.912 ;
     RECT  24.473 41.136 24.617 41.208 ;
     RECT  24.304 81.024 24.659 81.048 ;
     RECT  24.304 77.568 24.689 79.8 ;
     RECT  24.473 83.28 24.689 83.784 ;
     RECT  24.304 2.832 24.733 3.96 ;
     RECT  24.545 16.608 24.797 19.32 ;
     RECT  24.689 83.28 24.797 83.64 ;
     RECT  24.304 93.84 24.797 94.68 ;
     RECT  24.304 102.048 24.841 103.224 ;
     RECT  24.581 48.144 24.905 49.272 ;
     RECT  24.733 3.312 24.941 3.96 ;
     RECT  24.304 12.864 24.941 15.048 ;
     RECT  24.617 26.208 24.941 27.912 ;
     RECT  24.473 82.176 24.977 82.2 ;
     RECT  24.304 69.504 25.005 75.768 ;
     RECT  25.005 69.504 25.036 72.6 ;
     RECT  24.304 35.424 25.043 37.272 ;
     RECT  24.941 13.68 25.085 15.048 ;
     RECT  24.304 8.16 25.121 10.824 ;
     RECT  24.617 41.136 25.121 41.16 ;
     RECT  24.689 77.568 25.121 79.032 ;
     RECT  24.841 102.048 25.121 102.792 ;
     RECT  25.043 36 25.157 37.272 ;
     RECT  25.157 36 25.193 36.264 ;
     RECT  24.581 56.016 25.193 57.72 ;
     RECT  24.905 48.144 25.229 49.224 ;
     RECT  24.304 58.704 25.229 63.288 ;
     RECT  24.797 83.28 25.229 83.304 ;
     RECT  24.437 6.096 25.265 7.176 ;
     RECT  24.581 52.512 25.265 55.032 ;
     RECT  24.304 91.728 25.283 92.664 ;
     RECT  25.265 6.096 25.301 6.264 ;
     RECT  24.304 64.896 25.301 66.168 ;
     RECT  25.283 92.64 25.324 92.664 ;
     RECT  24.304 29.664 25.325 29.784 ;
     RECT  24.304 30.768 25.325 31.656 ;
     RECT  24.304 22.512 25.333 24.168 ;
     RECT  25.121 8.16 25.369 9.72 ;
     RECT  25.229 48.144 25.369 48.984 ;
     RECT  25.325 29.664 25.427 31.656 ;
     RECT  25.193 56.736 25.441 57.72 ;
     RECT  25.229 58.704 25.441 62.088 ;
     RECT  25.301 64.944 25.441 66.168 ;
     RECT  24.304 67.2 25.441 67.224 ;
     RECT  25.085 13.68 25.445 14.136 ;
     RECT  24.581 42.768 25.477 46.056 ;
     RECT  25.333 22.512 25.481 24.456 ;
     RECT  24.304 100.128 25.484 100.248 ;
     RECT  25.477 42.72 25.523 46.056 ;
     RECT  24.304 32.736 25.549 32.76 ;
     RECT  24.304 34.128 25.549 34.152 ;
     RECT  25.441 64.944 25.549 67.224 ;
     RECT  25.369 68.352 25.549 68.376 ;
     RECT  25.036 69.504 25.549 71.256 ;
     RECT  24.797 94.512 25.549 94.68 ;
     RECT  25.369 7.344 25.571 9.72 ;
     RECT  25.484 99.168 25.571 100.248 ;
     RECT  24.304 90.528 25.58 90.552 ;
     RECT  24.581 50.88 25.585 51.384 ;
     RECT  25.265 52.512 25.585 54.456 ;
     RECT  25.481 22.512 25.589 24.168 ;
     RECT  25.549 32.736 25.589 34.152 ;
     RECT  24.545 38.4 25.589 39.336 ;
     RECT  25.571 7.344 25.612 9.624 ;
     RECT  25.005 73.632 25.669 75.768 ;
     RECT  25.589 22.512 25.697 24.12 ;
     RECT  25.585 50.88 25.697 54.456 ;
     RECT  24.304 89.472 25.708 89.496 ;
     RECT  25.669 73.632 25.715 76.392 ;
     RECT  25.301 6.096 25.733 6.12 ;
     RECT  24.941 26.352 25.733 27.912 ;
     RECT  24.304 85.44 25.733 88.392 ;
     RECT  25.523 42.72 25.769 44.472 ;
     RECT  25.121 78.048 25.769 79.032 ;
     RECT  25.549 94.512 25.805 95.4 ;
     RECT  24.304 97.632 25.805 97.944 ;
     RECT  25.697 22.512 25.841 23.928 ;
     RECT  25.715 76.368 25.841 76.392 ;
     RECT  24.437 5.04 25.873 5.112 ;
     RECT  25.157 37.248 25.909 37.272 ;
     RECT  25.589 38.4 25.909 39.288 ;
     RECT  25.733 85.44 25.909 85.464 ;
     RECT  25.369 48.048 25.916 48.984 ;
     RECT  25.769 43.008 25.949 44.472 ;
     RECT  25.909 37.248 25.955 39.288 ;
     RECT  25.955 37.584 25.996 39.288 ;
     RECT  25.916 47.328 26.003 48.984 ;
     RECT  25.427 29.664 26.017 29.688 ;
     RECT  24.941 3.312 26.021 3.672 ;
     RECT  25.121 102.432 26.053 102.792 ;
     RECT  25.805 97.632 26.057 97.896 ;
     RECT  25.121 10.8 26.089 10.824 ;
     RECT  26.017 11.952 26.089 11.976 ;
     RECT  25.441 82.368 26.089 83.208 ;
     RECT  25.549 64.944 26.125 71.256 ;
     RECT  25.036 72.576 26.125 72.6 ;
     RECT  25.441 56.736 26.129 62.088 ;
     RECT  26.053 102.432 26.129 102.84 ;
     RECT  25.909 84.72 26.147 85.464 ;
     RECT  26.089 10.8 26.201 11.976 ;
     RECT  26.125 64.944 26.201 72.6 ;
     RECT  26.021 3.312 26.233 3.576 ;
     RECT  26.147 84.72 26.237 84.936 ;
     RECT  25.229 63.264 26.243 63.288 ;
     RECT  25.841 22.512 26.293 23.88 ;
     RECT  26.201 70.128 26.309 72.6 ;
     RECT  25.805 95.376 26.309 95.4 ;
     RECT  26.017 29.232 26.341 29.688 ;
     RECT  25.193 36 26.341 36.072 ;
     RECT  26.129 60.864 26.345 62.088 ;
     RECT  26.293 21.552 26.377 23.88 ;
     RECT  26.129 56.736 26.377 59.784 ;
     RECT  26.201 64.944 26.381 68.712 ;
     RECT  26.003 48.24 26.389 48.984 ;
     RECT  26.389 48.24 26.413 49.752 ;
     RECT  25.697 50.88 26.413 50.904 ;
     RECT  26.057 97.824 26.417 97.896 ;
     RECT  26.129 102.72 26.417 102.84 ;
     RECT  26.341 36 26.437 36.456 ;
     RECT  26.413 48.24 26.476 50.904 ;
     RECT  26.197 27.984 26.485 28.008 ;
     RECT  26.341 29.04 26.485 29.688 ;
     RECT  25.697 52.224 26.485 54.456 ;
     RECT  25.58 90.528 26.485 90.744 ;
     RECT  25.571 100.128 26.485 100.248 ;
     RECT  26.417 97.872 26.489 97.896 ;
     RECT  26.377 21.024 26.521 23.88 ;
     RECT  26.309 71.136 26.521 72.6 ;
     RECT  25.715 73.632 26.521 74.904 ;
     RECT  26.437 34.752 26.533 36.456 ;
     RECT  26.485 100.128 26.557 100.392 ;
     RECT  26.345 60.864 26.579 61.224 ;
     RECT  26.485 27.984 26.593 29.688 ;
     RECT  25.427 30.864 26.593 31.656 ;
     RECT  25.949 43.824 26.593 44.472 ;
     RECT  25.523 45.552 26.593 46.056 ;
     RECT  26.485 76.896 26.597 76.92 ;
     RECT  25.612 7.344 26.665 8.184 ;
     RECT  25.612 9.216 26.665 9.624 ;
     RECT  25.996 38.688 26.665 39.288 ;
     RECT  26.125 93.552 26.669 94.056 ;
     RECT  26.665 7.344 26.701 9.624 ;
     RECT  26.593 27.984 26.705 31.656 ;
     RECT  26.579 60.864 26.741 60.888 ;
     RECT  26.701 6.816 26.771 9.624 ;
     RECT  25.873 5.04 26.773 5.784 ;
     RECT  26.771 6.816 26.773 9.24 ;
     RECT  26.201 10.944 26.773 11.976 ;
     RECT  26.701 25.152 26.773 25.176 ;
     RECT  26.521 71.136 26.773 74.904 ;
     RECT  25.729 80.064 26.773 80.088 ;
     RECT  26.557 100.128 26.773 101.352 ;
     RECT  26.485 52.224 26.777 54.6 ;
     RECT  26.773 10.944 26.784 12.552 ;
     RECT  25.769 78.048 26.809 78.552 ;
     RECT  26.777 52.224 26.813 52.536 ;
     RECT  26.773 24.912 26.819 25.176 ;
     RECT  24.797 16.608 26.821 18.984 ;
     RECT  26.521 20.352 26.821 23.88 ;
     RECT  26.593 43.824 26.821 46.056 ;
     RECT  26.777 53.52 26.849 54.6 ;
     RECT  25.733 87.168 26.849 88.392 ;
     RECT  26.784 11.952 26.857 12.552 ;
     RECT  26.773 71.136 26.857 75.864 ;
     RECT  26.821 16.608 26.867 23.88 ;
     RECT  26.821 43.824 26.867 46.776 ;
     RECT  26.773 80.064 26.867 80.136 ;
     RECT  25.996 37.584 26.885 37.608 ;
     RECT  26.867 16.608 26.893 18.744 ;
     RECT  26.773 5.04 26.917 9.24 ;
     RECT  26.377 56.352 26.917 59.784 ;
     RECT  26.089 82.272 26.917 83.208 ;
     RECT  26.917 4.656 26.921 9.24 ;
     RECT  26.237 84.912 26.921 84.936 ;
     RECT  26.773 100.128 26.921 101.496 ;
     RECT  26.849 88.368 26.953 88.392 ;
     RECT  26.921 4.656 26.957 6.84 ;
     RECT  26.233 2.832 26.993 3.576 ;
     RECT  26.417 102.72 26.993 102.792 ;
     RECT  26.953 88.368 27.024 88.968 ;
     RECT  26.957 4.656 27.025 5.784 ;
     RECT  26.917 55.872 27.029 59.784 ;
     RECT  26.849 87.168 27.065 87.192 ;
     RECT  26.849 53.52 27.101 54.264 ;
     RECT  25.589 32.736 27.137 33.672 ;
     RECT  26.784 10.944 27.173 10.968 ;
     RECT  26.993 2.832 27.205 2.856 ;
     RECT  25.445 14.112 27.205 14.136 ;
     RECT  26.665 15.408 27.205 15.432 ;
     RECT  26.485 90.528 27.212 90.936 ;
     RECT  27.205 2.64 27.245 2.856 ;
     RECT  27.025 4.128 27.245 5.784 ;
     RECT  26.705 28.416 27.245 31.656 ;
     RECT  26.857 71.136 27.253 75.528 ;
     RECT  26.867 19.776 27.281 23.88 ;
     RECT  25.733 26.352 27.285 26.808 ;
     RECT  27.205 13.968 27.292 15.432 ;
     RECT  27.285 26.352 27.301 26.952 ;
     RECT  27.029 58.08 27.301 59.784 ;
     RECT  27.061 96.528 27.313 96.552 ;
     RECT  26.533 35.952 27.317 36.456 ;
     RECT  26.867 46.032 27.385 46.776 ;
     RECT  26.476 48.24 27.385 48.84 ;
     RECT  26.413 62.592 27.385 62.952 ;
     RECT  27.281 19.776 27.389 22.776 ;
     RECT  27.313 96.528 27.421 96.888 ;
     RECT  26.381 64.944 27.425 68.376 ;
     RECT  26.921 100.128 27.425 100.392 ;
     RECT  27.292 14.688 27.457 15.432 ;
     RECT  26.893 16.608 27.457 18.504 ;
     RECT  27.425 67.872 27.457 68.376 ;
     RECT  26.669 93.984 27.457 94.056 ;
     RECT  26.533 34.752 27.493 34.776 ;
     RECT  26.665 38.688 27.493 39.432 ;
     RECT  25.729 40.464 27.493 40.488 ;
     RECT  27.457 93.984 27.497 95.016 ;
     RECT  26.867 43.824 27.529 44.472 ;
     RECT  26.857 11.952 27.533 11.976 ;
     RECT  27.389 21.408 27.533 22.776 ;
     RECT  26.309 70.128 27.565 70.152 ;
     RECT  26.993 102.768 27.565 102.792 ;
     RECT  27.253 71.856 27.569 75.528 ;
     RECT  27.385 46.032 27.589 48.84 ;
     RECT  26.476 49.92 27.589 50.904 ;
     RECT  27.024 88.464 27.589 88.968 ;
     RECT  27.212 90.192 27.589 90.936 ;
     RECT  26.921 8.16 27.635 9.24 ;
     RECT  27.421 10.272 27.635 10.296 ;
     RECT  26.957 6.816 27.641 6.84 ;
     RECT  26.917 92.88 27.641 92.952 ;
     RECT  27.493 34.656 27.673 34.776 ;
     RECT  26.809 78.048 27.673 78.648 ;
     RECT  27.635 8.16 27.676 9.048 ;
     RECT  27.589 46.032 27.676 50.904 ;
     RECT  26.917 81.888 27.677 83.208 ;
     RECT  27.493 38.688 27.683 40.488 ;
     RECT  27.385 62.592 27.709 63.288 ;
     RECT  27.137 32.736 27.713 33.144 ;
     RECT  27.677 82.944 27.733 83.208 ;
     RECT  27.457 67.872 27.745 69 ;
     RECT  27.565 70.128 27.745 70.824 ;
     RECT  27.589 88.464 27.781 90.936 ;
     RECT  27.701 85.488 27.785 85.512 ;
     RECT  27.457 14.688 27.821 18.504 ;
     RECT  27.389 19.776 27.821 20.376 ;
     RECT  27.029 55.872 27.853 56.76 ;
     RECT  27.301 58.08 27.853 60.696 ;
     RECT  27.853 58.08 27.857 60.888 ;
     RECT  27.425 100.128 27.857 100.152 ;
     RECT  27.677 81.888 27.877 81.912 ;
     RECT  27.877 81.504 27.923 81.912 ;
     RECT  27.821 18.48 27.925 18.504 ;
     RECT  26.819 24.912 27.929 24.936 ;
     RECT  27.713 32.736 27.929 33 ;
     RECT  27.673 77.712 27.929 78.648 ;
     RECT  27.733 82.944 27.929 84.312 ;
     RECT  27.781 88.464 27.929 91.272 ;
     RECT  26.921 101.472 27.932 101.496 ;
     RECT  27.676 46.032 27.965 48.84 ;
     RECT  27.929 77.712 27.965 78.552 ;
     RECT  27.245 28.704 27.971 31.656 ;
     RECT  27.971 30.72 27.997 31.656 ;
     RECT  27.929 32.736 27.997 32.952 ;
     RECT  27.529 43.584 27.997 44.472 ;
     RECT  27.281 23.856 28.001 23.88 ;
     RECT  27.097 98.016 28.001 98.664 ;
     RECT  27.932 101.28 28.019 101.496 ;
     RECT  27.497 94.992 28.021 95.016 ;
     RECT  27.421 96.24 28.021 96.888 ;
     RECT  27.923 81.504 28.029 81.528 ;
     RECT  27.997 30.72 28.037 32.952 ;
     RECT  27.745 67.872 28.037 70.824 ;
     RECT  28.021 94.992 28.067 96.888 ;
     RECT  27.997 43.296 28.069 44.472 ;
     RECT  28.067 95.712 28.108 96.888 ;
     RECT  28.033 37.152 28.141 37.416 ;
     RECT  27.821 20.352 28.145 20.376 ;
     RECT  27.709 62.592 28.165 63.384 ;
     RECT  27.205 41.568 28.172 41.592 ;
     RECT  27.676 49.872 28.177 50.904 ;
     RECT  26.813 52.224 28.177 52.392 ;
     RECT  27.929 88.464 28.181 91.032 ;
     RECT  27.925 18.48 28.217 18.648 ;
     RECT  27.857 58.128 28.217 60.888 ;
     RECT  27.853 55.44 28.249 56.76 ;
     RECT  27.673 34.176 28.253 34.776 ;
     RECT  28.172 41.568 28.259 42.216 ;
     RECT  28.253 34.656 28.285 34.776 ;
     RECT  28.249 55.2 28.285 56.76 ;
     RECT  28.181 88.464 28.309 90.264 ;
     RECT  28.177 49.872 28.321 52.392 ;
     RECT  28.217 18.48 28.355 18.504 ;
     RECT  27.317 35.952 28.357 35.976 ;
     RECT  28.141 37.152 28.357 37.56 ;
     RECT  28.108 96.24 28.361 96.888 ;
     RECT  28.001 98.64 28.361 98.664 ;
     RECT  28.309 87.792 28.397 90.264 ;
     RECT  27.565 102.768 28.397 103.176 ;
     RECT  28.259 41.568 28.429 41.928 ;
     RECT  27.425 64.944 28.429 66.888 ;
     RECT  27.245 4.512 28.453 5.784 ;
     RECT  28.285 34.656 28.501 34.968 ;
     RECT  28.357 35.952 28.501 37.56 ;
     RECT  28.019 101.472 28.501 101.496 ;
     RECT  28.453 4.512 28.537 6.216 ;
     RECT  27.533 21.408 28.537 21.672 ;
     RECT  28.321 49.872 28.573 52.488 ;
     RECT  27.101 53.52 28.573 53.544 ;
     RECT  27.301 25.968 28.645 26.952 ;
     RECT  28.285 55.2 28.709 56.904 ;
     RECT  28.537 21.36 28.717 21.672 ;
     RECT  27.533 22.752 28.717 22.776 ;
     RECT  28.069 43.248 28.717 44.472 ;
     RECT  28.573 49.872 28.741 53.544 ;
     RECT  28.709 54.912 28.741 56.904 ;
     RECT  27.683 38.688 28.748 40.056 ;
     RECT  28.429 41.28 28.748 41.928 ;
     RECT  27.929 84.048 28.753 84.312 ;
     RECT  28.501 34.656 28.789 37.56 ;
     RECT  28.429 64.656 28.789 66.888 ;
     RECT  27.965 77.712 28.789 77.928 ;
     RECT  28.789 64.56 28.825 66.888 ;
     RECT  27.925 93.84 28.825 93.864 ;
     RECT  28.789 34.656 28.861 37.608 ;
     RECT  28.789 77.616 28.861 77.928 ;
     RECT  27.245 2.64 28.897 2.808 ;
     RECT  28.741 49.872 28.897 56.904 ;
     RECT  28.217 58.128 28.897 58.488 ;
     RECT  28.217 60.864 28.933 60.888 ;
     RECT  28.165 62.448 28.933 63.384 ;
     RECT  27.676 8.16 28.969 8.184 ;
     RECT  28.897 2.64 29.005 2.856 ;
     RECT  28.537 4.176 29.029 6.216 ;
     RECT  28.969 7.2 29.029 8.184 ;
     RECT  28.861 76.704 29.039 77.928 ;
     RECT  28.753 84.048 29.077 84.888 ;
     RECT  29.005 2.64 29.125 2.904 ;
     RECT  29.029 4.176 29.125 8.184 ;
     RECT  28.645 25.968 29.149 27.384 ;
     RECT  28.165 12.96 29.173 12.984 ;
     RECT  27.821 14.688 29.173 17.448 ;
     RECT  29.039 76.704 29.185 78.36 ;
     RECT  29.125 2.64 29.269 8.184 ;
     RECT  28.393 10.464 29.269 10.872 ;
     RECT  28.933 60.864 29.269 63.384 ;
     RECT  27.569 72 29.269 75.528 ;
     RECT  29.185 76.704 29.269 78.696 ;
     RECT  28.825 93.84 29.269 94.536 ;
     RECT  28.361 96.24 29.269 96.6 ;
     RECT  29.173 12.96 29.365 17.448 ;
     RECT  29.269 2.64 29.408 10.872 ;
     RECT  29.365 12.96 29.408 17.688 ;
     RECT  28.717 21.36 29.408 22.776 ;
     RECT  29.149 25.008 29.408 27.384 ;
     RECT  27.971 28.704 29.408 29.64 ;
     RECT  28.037 30.72 29.408 32.76 ;
     RECT  28.861 34.656 29.408 37.656 ;
     RECT  28.748 38.688 29.408 41.928 ;
     RECT  28.717 43.248 29.408 45 ;
     RECT  27.965 46.032 29.408 48.072 ;
     RECT  28.897 49.872 29.408 58.488 ;
     RECT  28.217 59.76 29.408 59.832 ;
     RECT  29.269 60.816 29.408 63.384 ;
     RECT  28.825 64.416 29.408 66.888 ;
     RECT  28.037 67.872 29.408 68.28 ;
     RECT  28.037 69.504 29.408 70.824 ;
     RECT  29.269 72 29.408 78.696 ;
     RECT  26.917 79.776 29.408 79.848 ;
     RECT  29.293 80.88 29.408 80.904 ;
     RECT  27.929 82.944 29.408 82.968 ;
     RECT  29.077 84.048 29.408 85.704 ;
     RECT  28.397 88.464 29.408 90.264 ;
     RECT  28.213 92.64 29.408 92.664 ;
     RECT  29.269 93.84 29.408 96.6 ;
     RECT  29.221 98.784 29.408 98.808 ;
     RECT  27.973 100.08 29.408 100.104 ;
     RECT  28.501 101.472 29.408 102.024 ;
     RECT  28.397 103.152 29.408 103.176 ;
     RECT  29.408 2.148 29.512 103.692 ;
     RECT  29.512 2.418 29.704 103.422 ;
     RECT  29.704 41.616 29.765 47.88 ;
     RECT  29.704 61.2 29.765 63.384 ;
     RECT  29.704 92.208 29.765 99.72 ;
     RECT  29.704 10.704 29.801 14.472 ;
     RECT  29.704 79.824 29.801 79.848 ;
     RECT  29.801 10.704 29.837 13.08 ;
     RECT  29.765 41.616 29.843 41.64 ;
     RECT  29.704 64.656 29.843 68.232 ;
     RECT  29.704 36.192 29.873 37.656 ;
     RECT  29.704 54.096 29.873 55.464 ;
     RECT  29.765 62.16 29.873 63.384 ;
     RECT  29.843 64.656 29.945 66.6 ;
     RECT  29.704 29.184 29.981 29.784 ;
     RECT  29.704 30.864 29.981 31.032 ;
     RECT  29.704 69.264 29.981 76.056 ;
     RECT  29.981 71.808 29.987 76.056 ;
     RECT  29.704 56.88 30.017 59.832 ;
     RECT  29.987 72 30.017 76.056 ;
     RECT  29.704 50.544 30.035 53.016 ;
     RECT  30.017 72 30.053 73.32 ;
     RECT  29.704 39.456 30.125 40.632 ;
     RECT  29.981 29.184 30.179 29.208 ;
     RECT  29.765 92.208 30.197 93.912 ;
     RECT  29.873 36.192 30.233 37.608 ;
     RECT  29.765 42.72 30.233 47.88 ;
     RECT  29.765 95.232 30.233 99.72 ;
     RECT  29.981 69.264 30.269 70.824 ;
     RECT  30.233 95.232 30.275 99.336 ;
     RECT  29.704 3.408 30.305 5.256 ;
     RECT  29.704 87.648 30.305 90.264 ;
     RECT  29.704 22.464 30.316 25.32 ;
     RECT  29.704 6.528 30.323 7.992 ;
     RECT  29.801 14.448 30.341 14.472 ;
     RECT  30.316 22.464 30.377 22.584 ;
     RECT  30.305 87.648 30.377 88.488 ;
     RECT  29.704 82.608 30.413 86.52 ;
     RECT  30.197 93.84 30.413 93.912 ;
     RECT  30.017 57.552 30.419 59.832 ;
     RECT  30.305 3.984 30.449 5.256 ;
     RECT  29.704 101.088 30.457 102.024 ;
     RECT  29.704 103.2 30.457 103.224 ;
     RECT  30.269 69.264 30.485 69.288 ;
     RECT  30.233 43.344 30.515 47.88 ;
     RECT  30.377 87.648 30.521 87.672 ;
     RECT  30.515 43.344 30.556 46.92 ;
     RECT  30.556 43.344 30.565 46.056 ;
     RECT  29.704 80.88 30.593 80.904 ;
     RECT  30.413 82.608 30.611 82.632 ;
     RECT  29.837 11.616 30.665 13.08 ;
     RECT  30.457 101.088 30.668 101.736 ;
     RECT  30.413 83.76 30.672 86.52 ;
     RECT  29.704 17.424 30.697 18.072 ;
     RECT  29.843 67.632 30.697 68.232 ;
     RECT  30.665 11.616 30.701 12.312 ;
     RECT  29.704 26.352 30.701 27.624 ;
     RECT  30.305 89.952 30.701 90.264 ;
     RECT  30.697 17.424 30.733 18.792 ;
     RECT  30.701 27.6 30.737 27.624 ;
     RECT  29.873 54.096 30.737 54.696 ;
     RECT  30.275 98.064 30.737 99.336 ;
     RECT  30.668 100.752 30.755 101.736 ;
     RECT  30.323 7.68 30.769 7.992 ;
     RECT  29.704 9.36 30.769 9.384 ;
     RECT  30.449 3.984 30.773 4.008 ;
     RECT  30.269 70.512 30.773 70.824 ;
     RECT  30.449 5.088 30.805 5.256 ;
     RECT  29.704 32.496 30.805 32.76 ;
     RECT  30.413 93.888 30.805 93.912 ;
     RECT  30.275 95.232 30.805 96.888 ;
     RECT  30.769 7.68 30.809 9.384 ;
     RECT  30.419 59.088 30.809 59.832 ;
     RECT  30.672 83.76 30.809 84.552 ;
     RECT  30.755 101.472 30.809 101.736 ;
     RECT  29.945 64.656 30.841 66.312 ;
     RECT  30.809 8.64 30.845 9.384 ;
     RECT  29.704 21.072 30.877 21.288 ;
     RECT  30.737 54.096 30.881 54.12 ;
     RECT  30.419 57.552 30.917 57.96 ;
     RECT  29.704 77.088 30.985 78.072 ;
     RECT  30.323 6.528 30.989 6.6 ;
     RECT  30.125 40.608 30.989 40.632 ;
     RECT  30.565 43.344 30.989 45 ;
     RECT  30.053 72.528 30.997 73.32 ;
     RECT  30.017 74.592 30.997 75.72 ;
     RECT  30.985 79.152 31.021 79.176 ;
     RECT  30.233 36.192 31.025 37.368 ;
     RECT  30.985 76.704 31.057 78.072 ;
     RECT  31.021 79.152 31.057 79.464 ;
     RECT  30.125 39.456 31.061 39.624 ;
     RECT  30.197 92.208 31.061 92.232 ;
     RECT  30.805 93.888 31.061 96.888 ;
     RECT  30.805 32.496 31.093 32.856 ;
     RECT  29.704 34.32 31.093 34.968 ;
     RECT  30.035 50.544 31.129 52.824 ;
     RECT  30.316 23.568 31.133 25.32 ;
     RECT  29.873 63.024 31.133 63.384 ;
     RECT  31.093 32.496 31.139 34.968 ;
     RECT  29.704 15.936 31.169 16.056 ;
     RECT  31.139 34.608 31.169 34.968 ;
     RECT  31.025 36.192 31.169 36.408 ;
     RECT  31.139 32.736 31.18 33.432 ;
     RECT  31.148 29.616 31.201 29.64 ;
     RECT  31.133 23.616 31.205 25.32 ;
     RECT  31.201 28.368 31.235 29.64 ;
     RECT  29.981 31.008 31.237 31.032 ;
     RECT  30.841 64.56 31.244 66.312 ;
     RECT  30.697 67.632 31.244 68.376 ;
     RECT  29.704 49.056 31.273 49.512 ;
     RECT  31.129 50.544 31.273 53.016 ;
     RECT  30.913 81.984 31.273 82.152 ;
     RECT  31.205 23.808 31.277 25.32 ;
     RECT  30.841 19.92 31.285 19.944 ;
     RECT  30.877 21.072 31.285 22.104 ;
     RECT  31.285 19.92 31.331 22.104 ;
     RECT  30.997 72.528 31.331 75.72 ;
     RECT  30.701 90.24 31.345 90.264 ;
     RECT  31.277 23.808 31.349 24.216 ;
     RECT  31.273 81.456 31.357 82.152 ;
     RECT  30.989 43.344 31.381 44.76 ;
     RECT  30.805 5.088 31.385 5.496 ;
     RECT  31.277 25.248 31.385 25.32 ;
     RECT  30.809 59.088 31.385 59.544 ;
     RECT  31.244 64.56 31.385 68.376 ;
     RECT  30.733 80.448 31.385 80.472 ;
     RECT  30.805 61.344 31.453 61.368 ;
     RECT  30.809 83.76 31.457 84.168 ;
     RECT  31.309 2.688 31.525 2.712 ;
     RECT  31.381 42.24 31.525 44.76 ;
     RECT  31.385 65.808 31.525 68.376 ;
     RECT  30.845 8.64 31.565 8.952 ;
     RECT  31.385 25.248 31.565 25.272 ;
     RECT  31.169 34.608 31.565 34.68 ;
     RECT  31.525 2.688 31.571 3.864 ;
     RECT  31.057 76.704 31.571 79.464 ;
     RECT  31.571 3.024 31.612 3.864 ;
     RECT  30.737 98.304 31.621 99.336 ;
     RECT  30.733 17.328 31.633 18.792 ;
     RECT  31.331 72.528 31.633 73.512 ;
     RECT  30.809 101.472 31.667 101.496 ;
     RECT  30.701 26.352 31.669 26.52 ;
     RECT  31.633 16.56 31.709 18.792 ;
     RECT  31.621 98.304 31.753 99.576 ;
     RECT  31.237 30.912 31.765 31.032 ;
     RECT  31.525 41.808 31.777 44.76 ;
     RECT  31.385 5.088 31.817 5.256 ;
     RECT  31.385 64.56 31.849 64.584 ;
     RECT  31.345 90.24 31.849 90.936 ;
     RECT  31.061 94.512 31.849 96.888 ;
     RECT  31.753 98.304 31.849 98.664 ;
     RECT  31.765 30.912 31.853 31.368 ;
     RECT  31.021 56.304 31.853 56.328 ;
     RECT  30.565 46.032 31.885 46.056 ;
     RECT  31.385 59.52 31.885 59.544 ;
     RECT  31.453 60.768 31.885 61.368 ;
     RECT  31.525 65.808 31.885 68.424 ;
     RECT  31.237 69.456 31.885 69.48 ;
     RECT  30.773 70.512 31.885 70.728 ;
     RECT  31.885 59.52 31.889 61.368 ;
     RECT  31.885 46.032 31.909 46.68 ;
     RECT  31.273 48.24 31.909 53.016 ;
     RECT  31.909 46.032 31.961 53.016 ;
     RECT  31.885 65.808 31.961 70.728 ;
     RECT  31.961 48.96 31.993 53.016 ;
     RECT  31.957 54.288 31.993 54.312 ;
     RECT  31.565 8.64 32.033 8.76 ;
     RECT  31.777 41.376 32.033 44.76 ;
     RECT  31.849 90.24 32.065 91.752 ;
     RECT  31.525 13.632 32.069 13.656 ;
     RECT  31.331 74.592 32.069 75.72 ;
     RECT  31.849 94.512 32.069 98.664 ;
     RECT  31.061 39.456 32.101 39.48 ;
     RECT  32.069 96.192 32.105 98.664 ;
     RECT  31.853 30.912 32.173 30.936 ;
     RECT  30.917 57.936 32.173 57.96 ;
     RECT  31.133 63.024 32.173 63.144 ;
     RECT  31.961 65.808 32.213 70.536 ;
     RECT  30.989 6.528 32.245 6.552 ;
     RECT  31.18 32.736 32.245 33.24 ;
     RECT  31.417 88.032 32.245 88.056 ;
     RECT  32.065 89.424 32.245 91.752 ;
     RECT  31.961 46.032 32.249 47.736 ;
     RECT  30.672 85.872 32.273 86.52 ;
     RECT  32.245 88.032 32.273 91.752 ;
     RECT  31.669 26.352 32.281 27.192 ;
     RECT  32.173 57.552 32.293 57.96 ;
     RECT  31.349 23.808 32.317 23.832 ;
     RECT  32.101 39.456 32.317 39.912 ;
     RECT  32.033 41.376 32.317 44.472 ;
     RECT  32.293 57.456 32.353 57.96 ;
     RECT  31.633 72.048 32.353 73.512 ;
     RECT  31.612 3.024 32.357 3.432 ;
     RECT  31.993 48.96 32.357 54.312 ;
     RECT  32.273 85.872 32.357 91.752 ;
     RECT  31.169 36.384 32.389 36.408 ;
     RECT  32.353 71.904 32.389 73.512 ;
     RECT  32.357 49.008 32.393 54.312 ;
     RECT  32.173 30.816 32.429 30.936 ;
     RECT  32.348 80.448 32.435 80.472 ;
     RECT  32.245 6.528 32.437 7.416 ;
     RECT  32.209 8.544 32.437 8.568 ;
     RECT  31.633 103.2 32.453 103.224 ;
     RECT  32.069 94.512 32.461 95.208 ;
     RECT  32.069 74.784 32.465 75.72 ;
     RECT  32.437 6.528 32.483 8.568 ;
     RECT  32.281 26.352 32.485 27.336 ;
     RECT  31.235 28.368 32.485 29.112 ;
     RECT  32.053 84.768 32.485 84.792 ;
     RECT  32.357 85.872 32.485 86.952 ;
     RECT  32.453 102.624 32.485 103.224 ;
     RECT  32.173 62.256 32.497 63.144 ;
     RECT  31.849 64.128 32.497 64.584 ;
     RECT  32.485 84.768 32.497 86.952 ;
     RECT  31.561 83.232 32.501 83.256 ;
     RECT  32.485 26.352 32.531 29.112 ;
     RECT  32.317 39.456 32.531 44.472 ;
     RECT  32.389 71.808 32.531 73.512 ;
     RECT  31.561 15.36 32.533 15.384 ;
     RECT  32.531 26.352 32.533 28.824 ;
     RECT  32.245 32.304 32.537 33.24 ;
     RECT  32.213 65.808 32.537 65.832 ;
     RECT  32.531 71.856 32.537 73.512 ;
     RECT  32.485 101.712 32.537 103.224 ;
     RECT  32.357 88.032 32.569 91.752 ;
     RECT  32.485 99.696 32.572 100.68 ;
     RECT  32.533 25.872 32.573 28.824 ;
     RECT  32.497 62.256 32.573 64.584 ;
     RECT  32.569 88.032 32.573 92.136 ;
     RECT  32.573 62.304 32.581 64.584 ;
     RECT  31.571 77.088 32.609 79.464 ;
     RECT  31.357 82.128 32.609 82.152 ;
     RECT  31.565 34.608 32.645 34.632 ;
     RECT  31.331 20.352 32.677 22.104 ;
     RECT  32.483 7.92 32.681 8.568 ;
     RECT  32.393 50.688 32.681 54.312 ;
     RECT  32.353 56.88 32.681 57.96 ;
     RECT  32.681 57.456 32.725 57.96 ;
     RECT  31.889 59.52 32.725 60.792 ;
     RECT  32.389 36.384 32.749 37.08 ;
     RECT  32.483 6.528 32.785 6.84 ;
     RECT  30.701 11.616 32.825 12.264 ;
     RECT  31.489 38.4 32.893 38.424 ;
     RECT  32.531 39.456 32.893 40.152 ;
     RECT  32.533 14.4 32.908 15.384 ;
     RECT  32.609 78.096 32.915 79.464 ;
     RECT  32.581 64.128 32.929 64.584 ;
     RECT  32.825 11.616 32.933 12.168 ;
     RECT  32.869 76.608 32.956 77.064 ;
     RECT  32.317 23.232 32.969 23.832 ;
     RECT  32.681 51.888 32.969 54.312 ;
     RECT  32.537 71.856 32.969 72.264 ;
     RECT  32.915 78.72 32.969 79.464 ;
     RECT  32.681 50.688 33.004 50.904 ;
     RECT  32.749 36.384 33.005 37.272 ;
     RECT  32.393 49.008 33.005 49.512 ;
     RECT  32.725 57.456 33.013 60.792 ;
     RECT  33.013 57.456 33.059 61.08 ;
     RECT  32.497 84.336 33.059 86.952 ;
     RECT  32.461 93.6 33.061 95.208 ;
     RECT  32.105 96.192 33.061 98.088 ;
     RECT  32.929 64.128 33.077 64.632 ;
     RECT  32.933 11.616 33.113 11.976 ;
     RECT  32.573 28.8 33.113 28.824 ;
     RECT  33.059 57.456 33.113 60.024 ;
     RECT  32.969 79.44 33.113 79.464 ;
     RECT  33.061 93.6 33.113 98.088 ;
     RECT  33.005 36.384 33.145 37.176 ;
     RECT  31.957 55.392 33.145 55.416 ;
     RECT  33.113 94.56 33.148 97.992 ;
     RECT  33.005 49.008 33.149 49.032 ;
     RECT  32.969 71.856 33.149 72.072 ;
     RECT  33.059 84.336 33.149 86.472 ;
     RECT  33.148 94.56 33.149 94.92 ;
     RECT  33.149 94.56 33.155 94.824 ;
     RECT  33.148 96.192 33.155 97.992 ;
     RECT  31.817 5.184 33.181 5.256 ;
     RECT  32.785 6.432 33.181 6.84 ;
     RECT  32.969 52.512 33.185 54.312 ;
     RECT  33.149 72 33.185 72.072 ;
     RECT  32.531 41.808 33.221 44.472 ;
     RECT  31.709 16.56 33.253 18.072 ;
     RECT  32.573 25.872 33.257 27.336 ;
     RECT  33.145 55.392 33.257 55.992 ;
     RECT  33.181 5.184 33.265 6.84 ;
     RECT  32.893 38.4 33.293 40.152 ;
     RECT  32.537 32.304 33.301 32.328 ;
     RECT  32.573 88.512 33.329 92.136 ;
     RECT  32.908 14.784 33.356 15.384 ;
     RECT  33.253 16.56 33.356 18.936 ;
     RECT  32.537 73.488 33.361 73.512 ;
     RECT  33.265 6.288 33.365 6.84 ;
     RECT  33.356 14.784 33.395 18.936 ;
     RECT  32.677 20.352 33.395 22.248 ;
     RECT  32.357 3.408 33.397 3.432 ;
     RECT  33.257 25.872 33.401 26.76 ;
     RECT  33.395 15.888 33.436 18.936 ;
     RECT  33.436 15.888 33.443 16.584 ;
     RECT  33.436 17.616 33.443 18.936 ;
     RECT  32.213 67.296 33.469 70.536 ;
     RECT  32.572 99.696 33.473 99.72 ;
     RECT  33.397 2.832 33.484 3.432 ;
     RECT  33.221 41.808 33.491 43.368 ;
     RECT  33.293 38.688 33.541 40.152 ;
     RECT  33.113 11.952 33.545 11.976 ;
     RECT  32.956 77.04 33.581 77.064 ;
     RECT  33.443 17.856 33.617 18.888 ;
     RECT  33.155 94.56 33.617 94.584 ;
     RECT  33.401 25.872 33.649 26.52 ;
     RECT  33.577 99.744 33.649 100.536 ;
     RECT  32.537 101.712 33.649 101.736 ;
     RECT  33.155 96.24 33.653 97.992 ;
     RECT  33.541 38.688 33.683 40.632 ;
     RECT  33.395 21.648 33.685 22.248 ;
     RECT  32.969 23.232 33.685 23.352 ;
     RECT  33.109 82.608 33.685 82.632 ;
     RECT  33.329 88.704 33.72 92.136 ;
     RECT  33.683 38.736 33.725 40.632 ;
     RECT  33.469 67.296 33.725 70.68 ;
     RECT  33.185 52.512 33.761 54.12 ;
     RECT  33.72 88.704 33.761 93.096 ;
     RECT  32.429 30.912 33.793 30.936 ;
     RECT  33.725 67.296 33.797 69.48 ;
     RECT  33.145 8.784 33.829 9.528 ;
     RECT  32.581 62.304 33.865 63.048 ;
     RECT  33.265 5.184 33.901 5.256 ;
     RECT  33.301 32.208 33.901 32.328 ;
     RECT  33.361 73.488 34.021 73.752 ;
     RECT  32.465 74.784 34.021 75.576 ;
     RECT  33.685 81.36 34.021 82.632 ;
     RECT  33.004 50.88 34.045 50.904 ;
     RECT  34.021 73.344 34.045 75.576 ;
     RECT  33.541 80.016 34.045 80.04 ;
     RECT  34.021 81.36 34.045 82.968 ;
     RECT  33.149 84.336 34.045 86.04 ;
     RECT  33.491 41.808 34.081 43.32 ;
     RECT  33.725 70.512 34.117 70.68 ;
     RECT  33.901 32.208 34.152 32.712 ;
     RECT  33.937 33.936 34.152 33.96 ;
     RECT  33.865 62.16 34.153 63.048 ;
     RECT  33.185 72 34.165 72.024 ;
     RECT  34.045 73.344 34.165 75.864 ;
     RECT  33.793 30.864 34.213 30.936 ;
     RECT  34.152 32.208 34.213 33.96 ;
     RECT  33.059 61.056 34.213 61.08 ;
     RECT  34.153 62.16 34.213 63.096 ;
     RECT  34.189 78.624 34.213 78.648 ;
     RECT  34.045 80.016 34.213 80.28 ;
     RECT  33.653 96.24 34.261 96.36 ;
     RECT  33.113 57.456 34.441 59.832 ;
     RECT  34.165 72 34.477 75.864 ;
     RECT  33.577 66.096 34.508 66.12 ;
     RECT  33.797 67.296 34.508 67.848 ;
     RECT  32.537 103.2 34.513 103.224 ;
     RECT  33.617 17.856 34.549 18.792 ;
     RECT  33.761 53.616 34.549 54.12 ;
     RECT  33.077 64.272 34.549 64.632 ;
     RECT  33.649 99.744 34.556 101.736 ;
     RECT  34.045 50.88 34.585 51.144 ;
     RECT  33.761 52.512 34.585 52.536 ;
     RECT  34.549 17.616 34.621 18.792 ;
     RECT  34.441 57.312 34.621 59.832 ;
     RECT  34.213 61.056 34.621 63.096 ;
     RECT  33.685 21.648 34.645 23.352 ;
     RECT  33.937 29.04 34.645 29.064 ;
     RECT  33.901 4.608 34.652 5.256 ;
     RECT  33.365 6.384 34.652 6.6 ;
     RECT  33.257 55.68 34.657 55.992 ;
     RECT  34.652 4.608 34.693 6.6 ;
     RECT  34.453 13.584 34.693 13.608 ;
     RECT  33.395 14.784 34.693 14.808 ;
     RECT  34.261 95.904 34.693 96.36 ;
     RECT  33.653 97.344 34.693 97.992 ;
     RECT  34.556 99.168 34.693 101.736 ;
     RECT  34.045 81.36 34.729 86.04 ;
     RECT  33.484 3.36 34.801 3.432 ;
     RECT  34.645 21.648 34.801 24.072 ;
     RECT  33.649 25.104 34.801 26.52 ;
     RECT  34.801 3.024 34.808 3.432 ;
     RECT  34.693 4.512 34.808 6.6 ;
     RECT  33.829 8.448 34.808 9.528 ;
     RECT  34.693 13.584 34.808 14.808 ;
     RECT  33.443 16.56 34.808 16.584 ;
     RECT  34.621 17.616 34.808 18.84 ;
     RECT  33.395 20.352 34.808 20.376 ;
     RECT  34.801 21.456 34.808 24.072 ;
     RECT  34.801 25.104 34.808 26.808 ;
     RECT  34.645 28.32 34.808 29.064 ;
     RECT  34.213 30.864 34.808 33.96 ;
     RECT  33.145 35.616 34.808 37.176 ;
     RECT  33.725 38.976 34.808 40.152 ;
     RECT  34.081 41.712 34.808 43.32 ;
     RECT  33.221 44.448 34.808 44.472 ;
     RECT  32.249 46.032 34.808 46.872 ;
     RECT  34.261 49.488 34.808 49.512 ;
     RECT  34.585 50.88 34.808 52.536 ;
     RECT  34.549 53.616 34.808 54.216 ;
     RECT  34.657 55.44 34.808 55.992 ;
     RECT  34.621 57.312 34.808 63.096 ;
     RECT  34.549 64.272 34.808 64.92 ;
     RECT  34.508 66.096 34.808 67.848 ;
     RECT  33.797 68.976 34.808 69.48 ;
     RECT  34.117 70.512 34.808 70.824 ;
     RECT  34.477 72 34.808 76.344 ;
     RECT  34.213 78.624 34.808 80.28 ;
     RECT  34.729 81.36 34.808 86.616 ;
     RECT  33.761 88.704 34.808 88.728 ;
     RECT  33.761 89.808 34.808 93.096 ;
     RECT  34.655 94.416 34.808 94.44 ;
     RECT  34.693 95.664 34.808 96.36 ;
     RECT  34.693 97.344 34.808 101.736 ;
     RECT  34.513 103.056 34.808 103.224 ;
     RECT  34.808 2.148 34.912 103.692 ;
     RECT  34.912 2.418 35.104 103.422 ;
     RECT  35.104 76.32 35.165 78.696 ;
     RECT  35.104 62.16 35.201 62.568 ;
     RECT  35.104 31.92 35.219 36.264 ;
     RECT  35.104 48.048 35.219 51.96 ;
     RECT  35.104 84.336 35.219 87.192 ;
     RECT  35.219 32.976 35.273 36.264 ;
     RECT  35.104 95.52 35.273 95.688 ;
     RECT  35.104 29.04 35.309 29.064 ;
     RECT  35.104 43.296 35.309 43.32 ;
     RECT  35.104 103.056 35.309 103.08 ;
     RECT  35.104 37.488 35.345 40.152 ;
     RECT  35.104 42.096 35.363 42.216 ;
     RECT  35.104 79.728 35.363 83.256 ;
     RECT  35.104 30.816 35.381 30.888 ;
     RECT  35.104 55.2 35.381 55.608 ;
     RECT  35.104 67.392 35.404 70.968 ;
     RECT  35.104 72 35.409 72.024 ;
     RECT  35.165 76.32 35.411 77.688 ;
     RECT  35.363 81.6 35.411 83.256 ;
     RECT  35.104 75.216 35.417 75.24 ;
     RECT  35.273 95.52 35.417 95.64 ;
     RECT  35.273 34.608 35.459 36.264 ;
     RECT  35.104 15.936 35.489 17.496 ;
     RECT  35.104 18.816 35.561 23.352 ;
     RECT  35.561 18.816 35.597 23.304 ;
     RECT  35.363 42.096 35.597 42.12 ;
     RECT  35.219 50.112 35.597 51.48 ;
     RECT  35.219 84.336 35.597 84.36 ;
     RECT  35.459 34.656 35.699 36.264 ;
     RECT  35.104 56.688 35.699 60.552 ;
     RECT  35.104 94.416 35.705 94.44 ;
     RECT  35.699 60.096 35.74 60.552 ;
     RECT  35.345 38.688 35.741 40.152 ;
     RECT  35.74 60.096 35.741 60.456 ;
     RECT  35.219 86.496 35.777 87.192 ;
     RECT  35.104 88.176 35.795 88.2 ;
     RECT  35.363 79.728 35.813 80.28 ;
     RECT  35.411 82.032 35.813 83.256 ;
     RECT  35.104 101.376 35.813 101.736 ;
     RECT  35.777 86.784 35.836 87.192 ;
     RECT  35.104 26.64 35.849 26.76 ;
     RECT  35.165 78.672 35.885 78.696 ;
     RECT  35.104 3.024 35.921 3.048 ;
     RECT  35.597 18.816 35.921 20.904 ;
     RECT  35.381 30.816 35.921 30.84 ;
     RECT  35.104 91.68 35.921 91.704 ;
     RECT  35.699 56.688 35.939 59.016 ;
     RECT  35.104 8.448 35.957 11.16 ;
     RECT  35.104 97.536 35.957 100.008 ;
     RECT  35.104 4.848 36.029 6.84 ;
     RECT  35.104 64.08 36.029 64.104 ;
     RECT  35.597 21.984 36.065 23.304 ;
     RECT  35.104 25.152 36.065 25.32 ;
     RECT  35.219 85.44 36.065 85.512 ;
     RECT  35.939 57.168 36.083 59.016 ;
     RECT  36.029 4.848 36.085 5.736 ;
     RECT  35.921 18.816 36.101 19.704 ;
     RECT  36.085 4.08 36.131 5.736 ;
     RECT  35.104 44.448 36.133 46.872 ;
     RECT  35.104 92.784 36.133 93.096 ;
     RECT  35.417 95.52 36.133 95.544 ;
     RECT  36.133 44.448 36.169 47.352 ;
     RECT  35.597 50.736 36.173 51.48 ;
     RECT  36.065 85.488 36.179 85.512 ;
     RECT  35.381 55.584 36.205 55.608 ;
     RECT  35.273 32.976 36.209 33.048 ;
     RECT  35.489 17.472 36.229 17.496 ;
     RECT  36.101 18.816 36.229 19.368 ;
     RECT  35.104 13.632 36.241 13.896 ;
     RECT  35.489 15.936 36.245 16.44 ;
     RECT  35.957 98.64 36.245 100.008 ;
     RECT  36.245 16.416 36.275 16.44 ;
     RECT  36.229 17.472 36.275 19.368 ;
     RECT  35.404 67.392 36.313 70.68 ;
     RECT  35.957 97.536 36.313 97.56 ;
     RECT  35.411 76.608 36.317 77.688 ;
     RECT  35.345 37.488 36.323 37.512 ;
     RECT  36.209 33.024 36.353 33.048 ;
     RECT  35.699 34.656 36.353 35.304 ;
     RECT  36.083 57.168 36.353 58.248 ;
     RECT  36.313 66.528 36.371 70.68 ;
     RECT  36.133 95.136 36.38 95.544 ;
     RECT  36.313 96.864 36.38 97.56 ;
     RECT  35.104 12.576 36.385 12.6 ;
     RECT  36.173 50.832 36.385 51.48 ;
     RECT  36.097 64.944 36.385 64.968 ;
     RECT  36.371 66.528 36.385 67.416 ;
     RECT  36.371 68.976 36.385 70.68 ;
     RECT  36.205 55.584 36.389 55.8 ;
     RECT  36.133 92.784 36.389 93.816 ;
     RECT  35.104 53.568 36.421 53.64 ;
     RECT  36.241 13.632 36.425 14.184 ;
     RECT  36.385 12.24 36.457 12.6 ;
     RECT  35.813 83.232 36.457 83.256 ;
     RECT  36.385 64.944 36.461 67.416 ;
     RECT  36.169 43.872 36.467 47.352 ;
     RECT  36.317 76.608 36.469 77.592 ;
     RECT  35.957 9.744 36.497 11.16 ;
     RECT  36.385 68.976 36.515 71.304 ;
     RECT  36.469 75.12 36.515 77.592 ;
     RECT  35.957 8.448 36.517 8.76 ;
     RECT  36.275 18.144 36.533 18.84 ;
     RECT  36.065 22.08 36.533 23.304 ;
     RECT  36.515 75.12 36.556 77.496 ;
     RECT  36.421 53.568 36.569 54.36 ;
     RECT  36.517 7.872 36.604 8.76 ;
     RECT  36.425 13.632 36.677 13.896 ;
     RECT  36.467 46.752 36.677 47.352 ;
     RECT  36.457 12.192 36.709 12.6 ;
     RECT  36.389 92.88 36.709 93.816 ;
     RECT  36.38 95.136 36.709 97.56 ;
     RECT  36.709 92.88 36.755 97.56 ;
     RECT  35.741 38.688 36.785 39.48 ;
     RECT  36.467 43.872 36.785 45.72 ;
     RECT  36.785 38.736 36.817 39.48 ;
     RECT  35.219 48.72 36.817 48.936 ;
     RECT  35.104 89.808 36.853 90.648 ;
     RECT  36.349 101.04 36.853 101.064 ;
     RECT  35.836 87.168 36.857 87.192 ;
     RECT  35.219 31.92 36.889 31.944 ;
     RECT  36.817 48.72 36.889 49.512 ;
     RECT  36.755 93.072 36.949 97.56 ;
     RECT  36.245 98.64 36.949 99.432 ;
     RECT  36.353 34.656 36.961 34.824 ;
     RECT  35.813 82.032 36.961 82.152 ;
     RECT  36.949 93.072 36.995 99.432 ;
     RECT  36.131 4.08 36.997 4.104 ;
     RECT  36.497 11.04 36.997 11.16 ;
     RECT  36.709 12.192 36.997 13.08 ;
     RECT  36.853 100.656 36.997 101.736 ;
     RECT  36.169 103.2 36.997 103.224 ;
     RECT  36.533 22.752 37.001 23.304 ;
     RECT  36.961 81.408 37.033 82.152 ;
     RECT  36.995 96.288 37.036 98.664 ;
     RECT  35.201 62.16 37.037 62.184 ;
     RECT  36.997 100.656 37.043 103.224 ;
     RECT  36.961 35.904 37.045 35.928 ;
     RECT  36.029 6.816 37.073 6.84 ;
     RECT  36.421 37.056 37.073 37.08 ;
     RECT  36.997 3.36 37.109 4.104 ;
     RECT  36.461 64.944 37.139 66.744 ;
     RECT  36.961 34.512 37.145 34.824 ;
     RECT  37.139 64.944 37.173 64.968 ;
     RECT  35.813 79.728 37.177 79.752 ;
     RECT  37.093 63.648 37.18 63.672 ;
     RECT  36.785 43.872 37.217 45 ;
     RECT  36.569 53.568 37.217 53.592 ;
     RECT  37.036 96.288 37.217 97.56 ;
     RECT  36.277 26.016 37.237 26.232 ;
     RECT  37.237 26.016 37.283 26.76 ;
     RECT  37.177 78.768 37.289 79.752 ;
     RECT  37.033 80.928 37.289 82.152 ;
     RECT  37.217 43.872 37.361 44.52 ;
     RECT  36.385 50.832 37.393 52.056 ;
     RECT  36.497 9.744 37.397 9.768 ;
     RECT  36.131 5.232 37.429 5.256 ;
     RECT  37.393 50.832 37.433 52.44 ;
     RECT  37.109 4.08 37.465 4.104 ;
     RECT  37.429 5.232 37.465 5.544 ;
     RECT  36.889 31.488 37.469 31.944 ;
     RECT  36.385 88.8 37.501 88.824 ;
     RECT  35.104 73.344 37.537 73.368 ;
     RECT  36.353 57.168 37.573 58.152 ;
     RECT  37.537 72.96 37.573 73.512 ;
     RECT  36.995 93.072 37.577 94.056 ;
     RECT  37.573 57.168 37.609 58.296 ;
     RECT  36.556 75.792 37.609 75.816 ;
     RECT  37.213 85.44 37.609 85.464 ;
     RECT  37.609 75.408 37.619 75.816 ;
     RECT  37.501 88.032 37.619 88.824 ;
     RECT  37.573 72.96 37.621 74.328 ;
     RECT  37.361 44.448 37.649 44.52 ;
     RECT  36.389 55.584 37.649 55.608 ;
     RECT  37.036 98.64 37.649 98.664 ;
     RECT  37.631 14.256 37.681 14.28 ;
     RECT  37.609 24.528 37.681 24.552 ;
     RECT  36.677 46.752 37.681 47.208 ;
     RECT  36.889 48.432 37.717 49.512 ;
     RECT  37.433 50.832 37.717 51.24 ;
     RECT  36.997 11.04 37.729 13.08 ;
     RECT  37.681 46.368 37.757 47.208 ;
     RECT  37.609 56.832 37.757 58.296 ;
     RECT  37.139 66.336 37.757 66.744 ;
     RECT  36.515 68.976 37.757 70.68 ;
     RECT  37.217 97.392 37.757 97.56 ;
     RECT  37.289 78.768 37.793 79.176 ;
     RECT  37.681 24.48 37.813 24.552 ;
     RECT  37.757 46.368 37.829 46.776 ;
     RECT  37.813 24.48 37.859 25.608 ;
     RECT  37.621 74.304 37.865 74.328 ;
     RECT  37.469 31.872 37.896 31.944 ;
     RECT  37.393 33.024 37.896 33.048 ;
     RECT  37.859 24.528 37.9 25.608 ;
     RECT  37.619 88.8 37.933 88.824 ;
     RECT  36.853 89.808 37.933 91.608 ;
     RECT  37.896 31.872 37.957 33.048 ;
     RECT  37.145 34.512 37.957 34.776 ;
     RECT  37.681 14.256 38.005 15.096 ;
     RECT  35.921 20.88 38.005 20.904 ;
     RECT  36.817 38.736 38.005 40.44 ;
     RECT  37.537 3.024 38.041 3.048 ;
     RECT  37.957 31.872 38.044 34.776 ;
     RECT  37.043 101.232 38.045 101.256 ;
     RECT  37.609 85.44 38.077 85.8 ;
     RECT  37.573 86.88 38.077 86.904 ;
     RECT  38.005 20.352 38.113 20.904 ;
     RECT  37.619 75.408 38.117 75.432 ;
     RECT  36.457 83.232 38.117 83.88 ;
     RECT  38.077 84.864 38.117 86.904 ;
     RECT  37.729 11.04 38.153 12.264 ;
     RECT  37.649 44.448 38.189 44.472 ;
     RECT  38.149 29.616 38.221 29.64 ;
     RECT  38.113 34.8 38.221 35.352 ;
     RECT  37.217 96.288 38.221 96.36 ;
     RECT  37.9 25.584 38.225 25.608 ;
     RECT  38.117 83.856 38.225 83.88 ;
     RECT  36.533 18.816 38.245 18.84 ;
     RECT  37.283 26.736 38.261 26.76 ;
     RECT  38.221 29.088 38.261 29.64 ;
     RECT  37.757 56.832 38.297 57.192 ;
     RECT  37.933 88.8 38.297 91.608 ;
     RECT  37.829 46.368 38.329 46.392 ;
     RECT  37.465 37.584 38.401 37.608 ;
     RECT  37.621 72.96 38.405 72.984 ;
     RECT  37.757 66.624 38.435 66.744 ;
     RECT  38.401 37.2 38.437 37.608 ;
     RECT  38.005 38.736 38.437 40.536 ;
     RECT  38.348 67.824 38.437 67.848 ;
     RECT  37.717 48.432 38.441 51.24 ;
     RECT  37.577 93.504 38.441 94.056 ;
     RECT  38.437 37.056 38.477 37.608 ;
     RECT  38.437 38.688 38.513 40.536 ;
     RECT  38.005 14.256 38.54 15.432 ;
     RECT  38.297 91.584 38.54 91.608 ;
     RECT  35.741 60.24 38.545 60.456 ;
     RECT  37.001 22.752 38.549 22.968 ;
     RECT  38.54 91.584 38.581 91.848 ;
     RECT  38.477 37.056 38.585 37.224 ;
     RECT  38.54 14.256 38.627 15.864 ;
     RECT  38.297 90.24 38.627 90.6 ;
     RECT  38.581 91.584 38.627 92.712 ;
     RECT  38.044 31.872 38.653 33.576 ;
     RECT  37.043 102.384 38.657 102.408 ;
     RECT  37.289 80.928 38.677 80.952 ;
     RECT  37.289 82.032 38.677 82.152 ;
     RECT  38.581 54.48 38.689 54.504 ;
     RECT  37.757 68.976 38.693 70.056 ;
     RECT  38.677 80.928 38.723 82.152 ;
     RECT  38.221 34.8 38.725 35.448 ;
     RECT  36.817 42.048 38.761 42.072 ;
     RECT  38.723 81.504 38.765 82.152 ;
     RECT  38.725 34.8 38.771 35.976 ;
     RECT  36.604 8.064 38.773 8.76 ;
     RECT  37.9 24.528 38.801 24.552 ;
     RECT  38.771 34.8 38.801 34.824 ;
     RECT  38.761 41.616 38.801 42.072 ;
     RECT  38.245 18.144 38.819 18.84 ;
     RECT  38.549 22.944 38.819 22.968 ;
     RECT  38.261 29.088 38.821 29.592 ;
     RECT  38.653 31.344 38.821 33.576 ;
     RECT  38.153 11.664 38.828 12.264 ;
     RECT  38.761 26.592 38.833 26.616 ;
     RECT  38.821 30.72 38.837 33.576 ;
     RECT  38.297 88.8 38.837 88.92 ;
     RECT  38.837 30.72 38.867 32.76 ;
     RECT  38.441 49.536 38.869 51.24 ;
     RECT  38.761 98.64 38.869 98.664 ;
     RECT  38.773 7.776 38.873 8.856 ;
     RECT  38.513 38.688 38.873 39.48 ;
     RECT  38.185 64.56 38.876 64.584 ;
     RECT  38.041 2.832 38.905 3.048 ;
     RECT  37.465 4.08 38.905 5.544 ;
     RECT  38.545 63.264 38.905 63.288 ;
     RECT  38.867 31.872 38.909 32.76 ;
     RECT  38.828 11.664 38.915 12.456 ;
     RECT  38.869 98.496 38.915 98.664 ;
     RECT  38.905 2.832 38.945 5.544 ;
     RECT  38.627 14.256 38.945 15.096 ;
     RECT  38.329 45.552 38.945 46.392 ;
     RECT  38.117 84.864 38.945 86.76 ;
     RECT  38.869 49.536 38.953 51.288 ;
     RECT  38.876 64.56 38.963 65.16 ;
     RECT  38.221 96.288 38.972 96.744 ;
     RECT  38.945 45.552 38.977 45.72 ;
     RECT  38.441 48.432 38.977 48.456 ;
     RECT  37.433 52.416 38.977 52.44 ;
     RECT  38.689 53.568 38.977 54.504 ;
     RECT  38.297 56.88 38.977 57.192 ;
     RECT  37.757 58.272 38.977 58.296 ;
     RECT  38.867 30.72 38.981 30.744 ;
     RECT  38.513 40.512 38.981 40.536 ;
     RECT  38.437 67.632 38.981 67.848 ;
     RECT  36.556 77.472 38.981 77.496 ;
     RECT  38.981 67.776 39.013 67.848 ;
     RECT  38.693 68.976 39.013 69.72 ;
     RECT  38.257 95.136 39.013 95.16 ;
     RECT  38.972 96.288 39.013 96.984 ;
     RECT  38.945 3.024 39.017 4.536 ;
     RECT  38.977 48.096 39.017 48.456 ;
     RECT  38.819 18.528 39.049 18.84 ;
     RECT  38.113 20.352 39.049 21.144 ;
     RECT  38.771 35.952 39.053 35.976 ;
     RECT  39.013 95.136 39.059 96.984 ;
     RECT  38.945 5.52 39.085 5.544 ;
     RECT  38.977 6.624 39.085 6.648 ;
     RECT  38.977 52.416 39.089 54.504 ;
     RECT  38.869 72.912 39.107 72.936 ;
     RECT  39.061 74.064 39.148 74.28 ;
     RECT  38.945 14.256 39.161 14.28 ;
     RECT  38.953 49.536 39.161 49.944 ;
     RECT  39.089 53.568 39.161 54.504 ;
     RECT  38.873 8.736 39.197 8.856 ;
     RECT  38.545 60.144 39.197 60.456 ;
     RECT  38.873 38.688 39.205 38.76 ;
     RECT  38.977 56.88 39.205 58.296 ;
     RECT  39.197 60.144 39.205 60.264 ;
     RECT  39.161 54.48 39.212 54.504 ;
     RECT  38.905 63.264 39.212 63.384 ;
     RECT  38.963 64.56 39.212 64.584 ;
     RECT  39.049 18.528 39.229 21.144 ;
     RECT  37.933 61.776 39.253 61.992 ;
     RECT  39.212 63.216 39.253 64.584 ;
     RECT  39.205 56.88 39.26 60.264 ;
     RECT  38.833 26.304 39.301 26.616 ;
     RECT  37.793 79.152 39.337 79.176 ;
     RECT  39.337 78.72 39.553 79.176 ;
     RECT  39.301 26.304 39.625 26.76 ;
     RECT  39.013 67.776 39.829 69.72 ;
     RECT  38.257 71.376 39.829 71.4 ;
     RECT  39.553 23.376 39.877 23.4 ;
     RECT  39.085 5.52 39.925 6.648 ;
     RECT  39.301 9.072 39.925 9.768 ;
     RECT  38.915 11.664 39.925 11.688 ;
     RECT  39.877 22.656 39.932 23.4 ;
     RECT  39.625 26.208 39.932 26.76 ;
     RECT  38.905 43.344 40.057 43.368 ;
     RECT  39.925 5.52 40.069 7.272 ;
     RECT  39.017 3.408 40.208 4.536 ;
     RECT  40.069 5.52 40.208 7.992 ;
     RECT  39.925 9.072 40.208 10.584 ;
     RECT  39.925 11.664 40.208 12.456 ;
     RECT  39.905 13.68 40.208 13.704 ;
     RECT  39.949 15.456 40.208 15.48 ;
     RECT  37.681 16.944 40.208 16.968 ;
     RECT  39.229 18.528 40.208 21.672 ;
     RECT  39.932 22.656 40.208 24.312 ;
     RECT  39.932 25.68 40.208 26.76 ;
     RECT  38.821 28.464 40.208 29.592 ;
     RECT  38.909 31.872 40.208 31.896 ;
     RECT  39.193 34.08 40.208 34.104 ;
     RECT  38.585 37.056 40.208 37.08 ;
     RECT  39.205 38.592 40.208 38.76 ;
     RECT  38.801 41.616 40.208 41.64 ;
     RECT  40.057 42.72 40.208 43.368 ;
     RECT  38.977 45.36 40.208 45.72 ;
     RECT  39.017 48.096 40.208 48.12 ;
     RECT  39.161 49.536 40.208 49.56 ;
     RECT  38.953 51.072 40.208 51.288 ;
     RECT  39.089 52.416 40.208 52.44 ;
     RECT  39.212 54.48 40.208 55.416 ;
     RECT  39.26 56.448 40.208 60.264 ;
     RECT  39.253 61.488 40.208 64.584 ;
     RECT  38.435 66.624 40.208 66.648 ;
     RECT  39.829 67.776 40.208 69.864 ;
     RECT  39.829 71.28 40.208 71.4 ;
     RECT  39.148 74.064 40.208 74.088 ;
     RECT  39.553 78.624 40.208 79.176 ;
     RECT  38.765 82.128 40.208 82.152 ;
     RECT  38.945 84.864 40.208 84.888 ;
     RECT  38.945 86.736 40.208 86.76 ;
     RECT  38.869 88.32 40.208 88.344 ;
     RECT  38.627 90.576 40.208 90.6 ;
     RECT  38.627 92.688 40.208 92.712 ;
     RECT  38.441 93.792 40.208 94.056 ;
     RECT  39.059 95.136 40.208 95.784 ;
     RECT  38.915 98.496 40.208 98.52 ;
     RECT  40.208 2.148 40.312 103.692 ;
     RECT  40.312 2.418 40.504 103.422 ;
    LAYER M5 ;
     RECT  9.024 0.144 13.512 1.763 ;
     RECT  2.4 2.137 2.52 2.151 ;
     RECT  7.8 2.137 7.92 2.151 ;
     RECT  18.6 2.137 18.72 2.151 ;
     RECT  24 2.137 24.12 2.151 ;
     RECT  29.4 2.137 29.52 2.151 ;
     RECT  34.8 2.137 34.92 2.151 ;
     RECT  40.2 2.137 40.32 2.151 ;
     RECT  29.4 2.151 29.712 2.629 ;
     RECT  18.6 2.151 18.912 2.725 ;
     RECT  24 2.151 24.312 2.821 ;
     RECT  29.28 2.629 29.712 2.821 ;
     RECT  18.6 2.725 19.8 2.915 ;
     RECT  17.424 2.485 17.448 3.299 ;
     RECT  29.184 2.821 29.712 3.301 ;
     RECT  7.8 2.151 8.112 3.349 ;
     RECT  34.8 2.151 35.112 3.397 ;
     RECT  33.408 2.821 33.432 3.443 ;
     RECT  9.456 1.763 13.512 3.589 ;
     RECT  24 2.821 24.696 3.683 ;
     RECT  40.2 2.151 40.512 3.685 ;
     RECT  31.536 2.677 31.56 3.875 ;
     RECT  2.4 2.151 2.712 3.925 ;
     RECT  7.248 3.349 8.112 3.925 ;
     RECT  9.456 3.589 13.656 3.925 ;
     RECT  18.6 2.915 19.752 3.925 ;
     RECT  9.456 3.925 14.232 4.067 ;
     RECT  37.008 3.349 37.032 4.069 ;
     RECT  36.096 4.069 37.032 4.115 ;
     RECT  9.456 4.067 9.624 4.261 ;
     RECT  17.616 3.925 19.752 4.547 ;
     RECT  17.616 4.547 18.912 4.931 ;
     RECT  5.376 4.261 5.4 5.029 ;
     RECT  6.528 3.925 8.112 5.029 ;
     RECT  24 3.683 24.312 5.029 ;
     RECT  5.376 5.029 8.112 5.077 ;
     RECT  9.264 4.261 9.624 5.077 ;
     RECT  15.648 4.453 15.672 5.077 ;
     RECT  5.376 5.077 9.624 5.123 ;
     RECT  2.304 3.925 2.712 5.171 ;
     RECT  34.704 3.397 35.112 5.459 ;
     RECT  7.248 5.123 9.624 5.653 ;
     RECT  10.8 4.067 14.232 5.699 ;
     RECT  7.248 5.653 9.672 5.701 ;
     RECT  10.8 5.699 13.656 5.701 ;
     RECT  39.888 3.685 40.512 5.891 ;
     RECT  24 5.029 25.128 6.085 ;
     RECT  29.136 3.301 29.712 6.181 ;
     RECT  23.04 6.085 25.128 6.275 ;
     RECT  6.048 5.123 6.072 6.277 ;
     RECT  17.664 4.931 18.912 6.323 ;
     RECT  7.248 5.701 13.656 6.805 ;
     RECT  23.04 6.275 24.408 6.805 ;
     RECT  36.096 4.115 36.12 6.805 ;
     RECT  7.248 6.805 13.704 6.851 ;
     RECT  36.096 6.805 36.552 6.851 ;
     RECT  22.8 6.805 24.408 7.187 ;
     RECT  28.464 6.181 29.712 7.189 ;
     RECT  5.952 6.277 6.072 7.237 ;
     RECT  39.984 5.891 40.512 7.237 ;
     RECT  5.952 7.237 6.264 7.283 ;
     RECT  15.36 5.077 15.672 7.333 ;
     RECT  15.36 7.333 15.816 7.379 ;
     RECT  20.736 5.653 20.76 7.379 ;
     RECT  33.216 5.653 33.24 7.381 ;
     RECT  7.8 6.851 13.704 7.717 ;
     RECT  28.464 7.189 30.312 8.003 ;
     RECT  22.8 7.187 24.312 8.147 ;
     RECT  28.464 8.003 29.712 8.149 ;
     RECT  28.176 8.149 29.712 8.195 ;
     RECT  18.192 6.323 18.912 8.245 ;
     RECT  17.088 8.149 17.112 8.291 ;
     RECT  18.192 8.245 19.32 8.389 ;
     RECT  32.448 7.381 33.24 8.437 ;
     RECT  34.8 5.459 35.112 8.437 ;
     RECT  36.528 6.851 36.552 8.437 ;
     RECT  6.048 7.283 6.264 8.485 ;
     RECT  32.448 8.437 36.552 8.579 ;
     RECT  33.216 8.579 36.552 8.675 ;
     RECT  20.544 7.429 20.568 8.723 ;
     RECT  38.784 7.765 38.808 8.867 ;
     RECT  26.736 7.333 26.76 9.013 ;
     RECT  28.176 8.195 28.2 9.013 ;
     RECT  15.648 7.379 15.816 9.061 ;
     RECT  33.216 8.675 35.88 9.539 ;
     RECT  7.8 7.717 14.28 9.589 ;
     RECT  5.28 8.485 6.264 9.637 ;
     RECT  7.8 9.589 14.328 9.637 ;
     RECT  5.28 9.637 14.328 9.683 ;
     RECT  25.536 8.341 25.56 9.731 ;
     RECT  2.4 5.171 2.712 10.165 ;
     RECT  26.736 9.013 28.2 10.307 ;
     RECT  28.176 10.307 28.2 10.453 ;
     RECT  29.28 8.195 29.712 10.453 ;
     RECT  5.28 9.683 5.304 10.741 ;
     RECT  15.648 9.061 16.152 10.837 ;
     RECT  28.176 10.453 29.712 10.883 ;
     RECT  2.4 10.165 2.808 11.027 ;
     RECT  34.8 9.539 35.88 11.075 ;
     RECT  6.864 9.683 14.328 11.171 ;
     RECT  4.56 10.741 5.304 11.411 ;
     RECT  15.648 10.837 16.584 11.413 ;
     RECT  6.864 11.171 13.512 11.555 ;
     RECT  26.736 10.307 26.76 11.749 ;
     RECT  15.408 11.413 16.584 11.845 ;
     RECT  23.04 8.147 24.312 11.941 ;
     RECT  26.688 11.749 26.76 11.941 ;
     RECT  17.616 8.389 19.32 12.035 ;
     RECT  38.88 11.653 38.904 12.467 ;
     RECT  7.152 11.555 13.512 12.517 ;
     RECT  15.36 11.845 16.584 12.517 ;
     RECT  26.688 11.941 26.808 12.563 ;
     RECT  28.176 10.883 28.2 12.949 ;
     RECT  29.4 10.883 29.712 12.949 ;
     RECT  28.176 12.949 29.712 12.995 ;
     RECT  22.848 11.941 24.312 13.045 ;
     RECT  18.432 12.035 19.32 13.091 ;
     RECT  15.36 12.517 16.68 13.139 ;
     RECT  18.6 13.091 19.32 13.573 ;
     RECT  34.8 11.075 35.112 13.573 ;
     RECT  2.4 11.027 2.712 13.621 ;
     RECT  39.936 7.237 40.512 13.715 ;
     RECT  5.136 11.411 5.304 13.813 ;
     RECT  5.136 13.813 5.688 13.859 ;
     RECT  26.688 12.563 26.76 13.957 ;
     RECT  7.152 12.517 13.608 14.099 ;
     RECT  22.848 13.045 24.456 14.099 ;
     RECT  7.152 14.099 13.512 14.243 ;
     RECT  2.4 13.621 3.48 14.291 ;
     RECT  7.152 14.243 9.528 14.291 ;
     RECT  18.6 13.573 20.184 14.291 ;
     RECT  37.68 13.045 37.704 14.291 ;
     RECT  33.216 9.539 33.24 14.389 ;
     RECT  15.408 13.139 16.68 14.581 ;
     RECT  15.12 14.581 16.68 14.627 ;
     RECT  18.6 14.291 19.32 14.773 ;
     RECT  5.28 13.859 5.688 15.347 ;
     RECT  32.832 14.389 33.24 15.349 ;
     RECT  18.24 14.773 19.32 15.395 ;
     RECT  32.832 15.349 33.384 15.395 ;
     RECT  33.36 15.395 33.384 15.877 ;
     RECT  26.688 13.957 27.24 15.925 ;
     RECT  18.6 15.395 19.32 16.501 ;
     RECT  26.688 15.925 27.672 16.501 ;
     RECT  28.8 12.995 29.712 16.501 ;
     RECT  34.464 13.573 35.112 16.595 ;
     RECT  26.688 16.501 29.712 16.787 ;
     RECT  38.592 15.061 38.616 16.933 ;
     RECT  38.256 16.933 38.616 16.979 ;
     RECT  16.656 14.627 16.68 16.981 ;
     RECT  15.12 14.627 15.672 17.029 ;
     RECT  5.28 15.347 5.304 17.077 ;
     RECT  26.688 16.787 27.96 17.077 ;
     RECT  24 14.099 24.456 17.315 ;
     RECT  4.8 17.077 5.304 17.461 ;
     RECT  18.6 16.501 19.992 17.461 ;
     RECT  14.544 17.029 15.672 17.605 ;
     RECT  16.656 16.981 17.352 17.605 ;
     RECT  38.256 16.979 38.28 18.133 ;
     RECT  38.256 18.133 38.808 18.179 ;
     RECT  18.6 17.461 20.568 18.419 ;
     RECT  26.208 17.077 27.96 18.469 ;
     RECT  38.784 18.179 38.808 18.565 ;
     RECT  40.08 13.715 40.512 18.565 ;
     RECT  38.784 18.565 40.512 18.611 ;
     RECT  4.8 17.461 5.736 18.613 ;
     RECT  24 17.315 24.312 18.757 ;
     RECT  4.8 18.613 5.928 18.851 ;
     RECT  33.36 15.877 33.432 18.947 ;
     RECT  14.544 17.605 17.352 18.949 ;
     RECT  18.6 18.419 19.32 18.949 ;
     RECT  14.544 18.949 19.32 18.995 ;
     RECT  22.848 14.099 22.872 19.141 ;
     RECT  2.4 14.291 2.712 19.237 ;
     RECT  5.904 18.851 5.928 19.285 ;
     RECT  34.8 16.595 35.112 19.333 ;
     RECT  36.24 16.405 36.264 19.333 ;
     RECT  34.8 19.333 36.264 19.379 ;
     RECT  14.544 18.995 18.912 19.667 ;
     RECT  24 18.757 24.408 19.763 ;
     RECT  2.304 19.237 2.712 20.003 ;
     RECT  20.544 18.419 20.568 20.149 ;
     RECT  4.8 18.851 4.824 20.437 ;
     RECT  5.904 19.285 6.792 20.437 ;
     RECT  39.312 18.611 40.512 20.485 ;
     RECT  4.8 20.437 6.792 20.531 ;
     RECT  34.8 19.379 35.88 20.531 ;
     RECT  14.544 19.667 15.672 20.579 ;
     RECT  20.544 20.149 21.096 20.867 ;
     RECT  4.8 20.531 5.928 21.155 ;
     RECT  29.4 16.787 29.712 21.253 ;
     RECT  31.296 19.909 31.32 21.299 ;
     RECT  22.752 19.141 22.872 21.301 ;
     RECT  14.832 20.579 15.672 21.683 ;
     RECT  16.656 19.667 18.912 21.683 ;
     RECT  38.784 20.485 40.512 21.683 ;
     RECT  5.904 21.155 5.928 21.973 ;
     RECT  17.856 21.683 18.912 22.163 ;
     RECT  4.8 21.155 4.824 22.165 ;
     RECT  5.904 21.973 5.976 22.165 ;
     RECT  20.544 20.867 20.568 22.165 ;
     RECT  22.272 21.301 22.872 22.165 ;
     RECT  20.544 22.165 22.872 22.211 ;
     RECT  20.88 22.211 22.872 22.259 ;
     RECT  39.888 21.683 40.512 22.691 ;
     RECT  4.8 22.165 5.976 22.741 ;
     RECT  4.608 22.741 5.976 22.787 ;
     RECT  5.712 22.787 5.976 22.835 ;
     RECT  38.784 21.683 38.808 22.979 ;
     RECT  26.208 18.469 28.344 23.123 ;
     RECT  22.848 22.259 22.872 23.173 ;
     RECT  24 19.763 24.312 23.173 ;
     RECT  22.848 23.173 24.312 23.219 ;
     RECT  33.36 18.947 33.384 23.269 ;
     RECT  34.8 20.531 35.112 23.269 ;
     RECT  20.88 22.259 21.864 23.315 ;
     RECT  33.36 23.269 35.112 23.315 ;
     RECT  18.48 22.163 18.912 23.365 ;
     RECT  39.936 22.691 40.512 23.411 ;
     RECT  16.656 21.683 16.68 24.083 ;
     RECT  20.88 23.315 20.904 24.277 ;
     RECT  20.592 24.277 20.904 24.323 ;
     RECT  4.608 22.787 4.632 24.563 ;
     RECT  15.12 21.683 15.672 24.563 ;
     RECT  10.512 14.243 13.512 24.661 ;
     RECT  7.8 14.291 9.528 24.901 ;
     RECT  10.512 24.661 14.28 24.901 ;
     RECT  18.384 23.365 18.912 24.901 ;
     RECT  18.384 24.901 19.464 25.091 ;
     RECT  29.4 21.253 30.264 25.091 ;
     RECT  23.04 23.219 24.312 25.477 ;
     RECT  33.984 23.315 35.112 25.715 ;
     RECT  39.984 23.411 40.512 25.715 ;
     RECT  5.952 22.835 5.976 25.861 ;
     RECT  37.824 24.469 37.848 26.197 ;
     RECT  23.04 25.477 24.504 26.291 ;
     RECT  7.8 24.901 14.28 26.483 ;
     RECT  29.4 25.091 30.168 26.485 ;
     RECT  18.48 25.091 19.464 26.627 ;
     RECT  29.4 26.485 30.312 26.627 ;
     RECT  37.248 26.197 37.848 26.771 ;
     RECT  5.088 25.861 5.976 26.819 ;
     RECT  20.592 24.323 20.616 26.819 ;
     RECT  26.448 23.123 28.344 26.963 ;
     RECT  5.088 26.819 5.112 27.107 ;
     RECT  32.544 25.861 32.568 27.203 ;
     RECT  7.8 26.483 13.512 27.637 ;
     RECT  7.8 27.637 13.608 27.971 ;
     RECT  18.6 26.627 19.464 28.261 ;
     RECT  34.8 25.715 35.112 28.309 ;
     RECT  2.4 20.003 2.712 28.453 ;
     RECT  21.984 28.453 22.008 29.029 ;
     RECT  23.04 26.291 24.312 29.029 ;
     RECT  34.656 28.309 35.112 29.075 ;
     RECT  21.984 29.029 24.312 29.123 ;
     RECT  32.496 27.301 32.52 29.123 ;
     RECT  29.4 26.627 30.168 29.219 ;
     RECT  21.984 29.123 22.776 29.795 ;
     RECT  15.6 24.563 15.672 30.421 ;
     RECT  25.392 29.653 25.416 30.563 ;
     RECT  27.648 26.963 28.344 30.709 ;
     RECT  29.4 29.219 29.712 30.709 ;
     RECT  24 29.123 24.312 30.757 ;
     RECT  25.344 30.709 25.368 30.757 ;
     RECT  26.448 26.963 26.472 30.757 ;
     RECT  27.648 30.709 29.712 30.757 ;
     RECT  17.664 28.261 19.464 30.851 ;
     RECT  34.8 29.075 35.112 30.853 ;
     RECT  26.448 30.757 29.712 30.899 ;
     RECT  5.76 27.781 5.784 30.901 ;
     RECT  5.568 30.901 5.784 30.995 ;
     RECT  24 30.757 25.368 30.995 ;
     RECT  31.2 29.605 31.224 30.997 ;
     RECT  31.2 30.997 31.8 31.043 ;
     RECT  15.6 30.421 15.72 31.189 ;
     RECT  25.344 30.995 25.368 31.379 ;
     RECT  38.832 28.453 38.856 31.379 ;
     RECT  2.304 28.453 2.712 31.427 ;
     RECT  5.568 30.995 5.592 31.907 ;
     RECT  34.224 30.853 35.112 31.909 ;
     RECT  21.984 29.795 22.68 31.955 ;
     RECT  34.224 31.909 35.208 32.197 ;
     RECT  33.312 32.197 35.208 32.243 ;
     RECT  31.776 31.043 31.8 32.485 ;
     RECT  7.8 27.971 13.512 32.579 ;
     RECT  5.664 32.341 5.688 33.013 ;
     RECT  33.312 32.243 35.112 33.059 ;
     RECT  5.568 33.013 5.688 33.299 ;
     RECT  5.568 33.299 5.592 33.589 ;
     RECT  26.448 30.899 26.472 33.683 ;
     RECT  7.8 32.579 10.536 33.827 ;
     RECT  24 30.995 24.312 34.117 ;
     RECT  18.6 30.851 19.464 34.309 ;
     RECT  31.104 32.485 31.8 34.355 ;
     RECT  11.664 32.579 13.512 34.597 ;
     RECT  15.552 31.189 16.632 34.597 ;
     RECT  34.8 33.059 35.112 34.597 ;
     RECT  31.776 34.355 31.8 34.643 ;
     RECT  11.664 34.597 14.232 34.693 ;
     RECT  2.4 31.427 2.712 34.741 ;
     RECT  37.968 32.437 37.992 34.741 ;
     RECT  15.312 34.597 16.632 34.787 ;
     RECT  37.008 34.741 37.992 34.787 ;
     RECT  18.6 34.309 19.656 34.789 ;
     RECT  9.696 33.827 10.536 34.835 ;
     RECT  26.496 34.741 26.52 35.027 ;
     RECT  18.6 34.789 20.04 35.029 ;
     RECT  34.8 34.597 35.448 35.269 ;
     RECT  10.224 34.835 10.536 35.317 ;
     RECT  11.52 34.693 14.232 35.317 ;
     RECT  2.4 34.741 3.384 35.411 ;
     RECT  4.896 33.589 5.592 35.893 ;
     RECT  7.8 33.827 8.664 35.893 ;
     RECT  10.224 35.317 14.232 35.893 ;
     RECT  18.6 35.029 20.376 35.939 ;
     RECT  37.008 34.787 37.032 35.939 ;
     RECT  7.8 35.893 14.232 35.987 ;
     RECT  38.736 34.789 38.76 35.987 ;
     RECT  22.656 31.955 22.68 35.989 ;
     RECT  21.888 35.989 22.68 36.421 ;
     RECT  26.448 35.077 26.472 36.467 ;
     RECT  7.8 35.987 13.512 36.515 ;
     RECT  2.4 35.411 3.24 36.661 ;
     RECT  4.896 35.893 5.688 36.661 ;
     RECT  2.4 36.661 5.688 36.901 ;
     RECT  21.888 36.421 22.824 37.043 ;
     RECT  24 34.117 25.032 37.237 ;
     RECT  24 37.237 25.944 37.283 ;
     RECT  34.8 35.269 35.688 37.477 ;
     RECT  34.8 37.477 36.312 37.523 ;
     RECT  15.552 34.787 16.632 37.573 ;
     RECT  18.6 35.939 19.656 38.147 ;
     RECT  25.92 37.283 25.944 38.147 ;
     RECT  40.2 25.715 40.512 38.581 ;
     RECT  21.888 37.043 22.68 38.677 ;
     RECT  24 37.283 24.312 38.677 ;
     RECT  33.312 33.059 33.336 38.677 ;
     RECT  36.288 37.523 36.312 38.771 ;
     RECT  39.216 38.581 40.512 38.771 ;
     RECT  9.6 36.515 11.496 38.819 ;
     RECT  15.552 37.573 16.872 38.819 ;
     RECT  24 38.677 24.456 38.819 ;
     RECT  2.4 36.901 5.832 39.203 ;
     RECT  21.888 38.677 22.872 39.301 ;
     RECT  27.648 30.899 29.712 39.301 ;
     RECT  33.312 38.677 33.672 39.347 ;
     RECT  21.12 39.301 22.872 39.349 ;
     RECT  21.12 39.349 22.968 39.491 ;
     RECT  7.8 36.515 8.616 40.067 ;
     RECT  33.312 39.347 33.48 40.117 ;
     RECT  26.736 39.301 29.712 40.405 ;
     RECT  21.12 39.491 22.68 40.451 ;
     RECT  15.552 38.819 15.624 40.453 ;
     RECT  26.736 40.405 29.832 40.499 ;
     RECT  7.8 40.067 8.52 40.835 ;
     RECT  24 38.819 24.408 40.835 ;
     RECT  2.4 39.203 4.392 40.885 ;
     RECT  12.96 36.515 13.512 40.981 ;
     RECT  15.552 40.453 15.768 41.027 ;
     RECT  9.6 38.819 11.448 41.075 ;
     RECT  12.96 40.981 14.232 41.123 ;
     RECT  9.6 41.075 11.064 41.509 ;
     RECT  28.32 40.499 29.832 41.557 ;
     RECT  28.224 41.557 29.832 41.651 ;
     RECT  7.8 40.835 8.232 41.891 ;
     RECT  9.456 41.509 11.064 41.893 ;
     RECT  32.496 40.117 33.48 41.939 ;
     RECT  34.8 37.523 35.112 42.085 ;
     RECT  7.8 41.891 8.112 42.133 ;
     RECT  28.224 41.651 29.712 42.227 ;
     RECT  34.8 42.085 35.352 42.227 ;
     RECT  24 40.835 24.312 42.517 ;
     RECT  2.4 40.885 4.728 42.709 ;
     RECT  5.808 39.203 5.832 42.709 ;
     RECT  12.96 41.123 13.704 42.709 ;
     RECT  15.552 41.027 15.624 42.709 ;
     RECT  16.848 38.819 16.872 42.709 ;
     RECT  18.6 38.147 19.128 42.709 ;
     RECT  18.48 42.709 19.128 43.093 ;
     RECT  24 42.517 24.504 43.139 ;
     RECT  28.32 42.227 29.712 43.141 ;
     RECT  12.576 42.709 13.704 43.283 ;
     RECT  34.8 42.227 35.112 43.285 ;
     RECT  20.16 41.989 20.184 43.333 ;
     RECT  33.456 41.939 33.48 43.333 ;
     RECT  33.072 43.333 33.48 43.379 ;
     RECT  18.432 43.093 19.128 43.523 ;
     RECT  18.48 43.523 19.128 43.811 ;
     RECT  12.576 43.283 13.512 43.859 ;
     RECT  2.4 42.709 5.832 44.339 ;
     RECT  28.32 43.141 30.216 44.341 ;
     RECT  6.864 42.133 8.112 44.483 ;
     RECT  20.16 43.333 20.664 44.579 ;
     RECT  15.552 42.709 16.872 44.627 ;
     RECT  20.16 44.579 20.184 45.155 ;
     RECT  13.056 43.859 13.512 45.157 ;
     RECT  13.056 45.157 13.656 45.203 ;
     RECT  15.552 44.627 15.624 45.443 ;
     RECT  28.32 44.341 31.08 45.635 ;
     RECT  24 43.139 24.312 45.685 ;
     RECT  2.4 44.339 4.776 45.731 ;
     RECT  21.888 40.451 22.68 45.877 ;
     RECT  25.488 42.709 25.512 45.925 ;
     RECT  26.832 44.101 26.856 45.925 ;
     RECT  25.488 45.925 26.856 45.971 ;
     RECT  36.432 43.861 36.456 45.971 ;
     RECT  31.056 45.635 31.08 46.645 ;
     RECT  34.8 43.285 35.208 46.645 ;
     RECT  20.928 45.877 22.68 46.739 ;
     RECT  2.4 45.731 4.728 46.741 ;
     RECT  5.808 44.339 5.832 46.741 ;
     RECT  25.968 45.971 26.856 46.787 ;
     RECT  15.552 45.443 15.576 46.789 ;
     RECT  33.072 43.379 33.096 46.883 ;
     RECT  28.32 45.635 29.712 46.885 ;
     RECT  31.056 46.645 31.944 46.885 ;
     RECT  13.2 45.203 13.656 46.931 ;
     RECT  14.736 46.789 15.576 46.931 ;
     RECT  9.36 41.893 11.064 47.747 ;
     RECT  28.32 46.885 31.944 47.749 ;
     RECT  15.552 46.931 15.576 47.845 ;
     RECT  16.848 44.627 16.872 47.845 ;
     RECT  25.968 46.787 25.992 48.083 ;
     RECT  27.552 47.749 31.944 48.083 ;
     RECT  21.648 46.739 22.68 48.467 ;
     RECT  27.552 48.083 28.344 48.467 ;
     RECT  15.552 47.845 16.872 48.707 ;
     RECT  18.6 43.811 19.128 48.899 ;
     RECT  34.8 46.645 35.88 48.947 ;
     RECT  37.008 48.901 37.032 49.043 ;
     RECT  18.6 48.899 19.032 49.523 ;
     RECT  29.4 48.083 31.944 49.523 ;
     RECT  28.32 48.467 28.344 49.525 ;
     RECT  24 45.685 24.408 49.619 ;
     RECT  7.8 44.483 8.112 50.005 ;
     RECT  15.552 48.707 16.008 50.101 ;
     RECT  30.912 49.523 31.944 50.147 ;
     RECT  9.888 47.747 11.064 50.195 ;
     RECT  21.888 48.467 22.68 50.533 ;
     RECT  21.072 50.533 23.016 50.629 ;
     RECT  24 49.619 24.312 50.629 ;
     RECT  15.168 50.101 16.008 50.725 ;
     RECT  7.8 50.005 8.376 50.771 ;
     RECT  2.4 46.741 5.832 50.965 ;
     RECT  38.88 50.101 38.904 51.253 ;
     RECT  40.2 38.771 40.512 51.253 ;
     RECT  38.88 51.253 40.512 51.299 ;
     RECT  15.168 50.725 16.536 51.347 ;
     RECT  30.912 50.147 31.08 51.395 ;
     RECT  15.696 51.347 16.536 51.829 ;
     RECT  7.8 50.771 8.112 51.877 ;
     RECT  15.696 51.829 16.776 51.923 ;
     RECT  32.928 49.477 32.952 51.923 ;
     RECT  16.752 51.923 16.776 51.971 ;
     RECT  34.8 48.947 35.208 51.971 ;
     RECT  21.072 50.629 24.312 52.067 ;
     RECT  21.888 52.067 24.312 52.115 ;
     RECT  27.6 49.525 28.344 52.403 ;
     RECT  18.6 49.523 18.912 52.405 ;
     RECT  28.32 52.403 28.344 52.405 ;
     RECT  29.4 49.523 29.712 52.405 ;
     RECT  31.056 51.395 31.08 52.453 ;
     RECT  2.4 50.965 6.264 52.499 ;
     RECT  31.056 52.453 31.272 52.499 ;
     RECT  28.32 52.405 29.712 52.931 ;
     RECT  15.696 51.923 15.72 52.981 ;
     RECT  29.4 52.931 29.712 52.981 ;
     RECT  13.2 46.931 13.512 53.557 ;
     RECT  18.48 52.405 18.912 53.603 ;
     RECT  0.24 14.869 0.264 53.891 ;
     RECT  26.4 48.949 26.424 54.085 ;
     RECT  28.32 52.931 28.344 54.085 ;
     RECT  29.4 52.981 30.024 54.085 ;
     RECT  28.32 54.085 30.024 54.131 ;
     RECT  33.312 52.981 33.336 54.131 ;
     RECT  10.272 50.195 11.064 54.179 ;
     RECT  2.4 52.499 5.832 54.421 ;
     RECT  13.2 53.557 13.608 54.467 ;
     RECT  39.312 51.299 40.512 54.469 ;
     RECT  2.304 54.421 5.832 54.707 ;
     RECT  2.4 54.707 5.832 54.709 ;
     RECT  18.6 53.603 18.912 54.709 ;
     RECT  7.8 51.877 8.952 55.237 ;
     RECT  24 52.115 24.312 55.237 ;
     RECT  2.4 54.709 6.696 55.283 ;
     RECT  39.264 54.469 40.512 55.427 ;
     RECT  34.8 51.971 35.112 55.573 ;
     RECT  36.432 53.557 36.456 55.573 ;
     RECT  34.8 55.573 36.456 55.619 ;
     RECT  15.696 52.981 16.44 55.813 ;
     RECT  18.6 54.709 19.416 55.813 ;
     RECT  21.888 52.115 22.68 55.813 ;
     RECT  13.2 54.467 13.512 55.861 ;
     RECT  26.4 54.085 26.952 55.907 ;
     RECT  24 55.237 24.408 56.003 ;
     RECT  28.32 54.131 29.712 56.387 ;
     RECT  28.32 56.387 28.344 56.389 ;
     RECT  17.616 55.813 19.416 56.483 ;
     RECT  24 56.003 24.312 56.725 ;
     RECT  23.904 56.725 24.312 56.867 ;
     RECT  18.6 56.483 19.416 57.011 ;
     RECT  7.8 55.237 9.72 57.013 ;
     RECT  11.04 54.179 11.064 57.013 ;
     RECT  7.8 57.013 11.064 57.059 ;
     RECT  13.056 55.861 13.512 57.059 ;
     RECT  21.12 55.813 22.68 57.059 ;
     RECT  10.56 57.059 11.064 57.107 ;
     RECT  14.832 55.813 16.44 57.107 ;
     RECT  29.4 56.387 29.712 57.541 ;
     RECT  31.248 52.499 31.272 57.541 ;
     RECT  32.304 57.445 32.328 57.541 ;
     RECT  26.4 55.907 26.424 57.635 ;
     RECT  34.8 55.619 35.928 57.973 ;
     RECT  7.8 57.059 8.952 58.117 ;
     RECT  28.176 56.389 28.344 58.117 ;
     RECT  18.6 57.011 18.912 58.165 ;
     RECT  15.696 57.107 16.44 58.211 ;
     RECT  24 56.867 24.312 58.693 ;
     RECT  21.648 57.059 22.68 58.739 ;
     RECT  32.304 57.541 32.76 58.885 ;
     RECT  39.312 55.427 40.512 59.029 ;
     RECT  24 58.693 24.984 59.267 ;
     RECT  13.2 57.059 13.512 59.269 ;
     RECT  18.048 58.165 18.912 59.315 ;
     RECT  16.368 58.211 16.44 59.363 ;
     RECT  27.312 58.117 28.344 59.797 ;
     RECT  29.4 57.541 31.272 59.797 ;
     RECT  27.312 59.797 31.272 59.843 ;
     RECT  7.248 58.117 8.952 60.133 ;
     RECT  39.216 59.029 40.512 60.179 ;
     RECT  7.248 60.133 9.144 60.275 ;
     RECT  13.104 59.269 13.512 60.373 ;
     RECT  34.8 57.973 36.072 60.467 ;
     RECT  16.416 59.363 16.44 60.517 ;
     RECT  34.8 60.467 35.688 60.563 ;
     RECT  24 59.267 24.312 60.805 ;
     RECT  24 60.805 24.456 60.853 ;
     RECT  21.888 58.739 22.68 60.949 ;
     RECT  13.104 60.373 14.376 61.043 ;
     RECT  32.304 58.885 33.048 61.091 ;
     RECT  27.312 59.843 29.712 61.189 ;
     RECT  40.2 60.179 40.512 61.477 ;
     RECT  18.6 59.315 18.912 61.525 ;
     RECT  34.8 60.563 35.112 61.525 ;
     RECT  16.176 60.517 16.44 61.619 ;
     RECT  26.544 61.189 29.712 61.619 ;
     RECT  7.248 60.275 8.112 61.763 ;
     RECT  13.2 61.043 14.376 61.907 ;
     RECT  26.544 61.619 28.344 62.053 ;
     RECT  24 60.853 25.128 62.099 ;
     RECT  16.416 61.619 16.44 62.149 ;
     RECT  34.224 61.525 35.112 62.435 ;
     RECT  18.6 61.525 19.224 62.579 ;
     RECT  9.12 60.275 9.144 62.725 ;
     RECT  26.208 62.053 28.344 62.963 ;
     RECT  24 62.099 24.456 63.203 ;
     RECT  2.4 55.283 5.832 63.205 ;
     RECT  13.2 61.907 13.512 63.205 ;
     RECT  21.648 60.949 22.68 63.253 ;
     RECT  24 63.203 24.312 63.253 ;
     RECT  7.68 61.763 8.112 63.299 ;
     RECT  26.208 62.963 26.568 63.299 ;
     RECT  21.648 63.253 24.312 63.301 ;
     RECT  21.264 63.301 24.312 63.347 ;
     RECT  12.432 63.205 13.512 63.685 ;
     RECT  16.416 62.149 16.536 63.781 ;
     RECT  21.264 63.347 21.288 64.019 ;
     RECT  9.12 62.725 9.288 64.067 ;
     RECT  2.304 63.205 5.832 64.309 ;
     RECT  11.568 63.685 13.512 64.355 ;
     RECT  16.416 63.781 16.632 64.451 ;
     RECT  31.248 59.843 31.272 64.549 ;
     RECT  32.304 61.091 32.808 64.549 ;
     RECT  39.264 61.477 40.512 64.549 ;
     RECT  38.928 64.549 40.512 64.595 ;
     RECT  7.8 63.299 8.112 64.741 ;
     RECT  34.704 62.435 35.112 64.885 ;
     RECT  28.176 62.963 28.344 64.933 ;
     RECT  2.256 64.309 5.832 64.979 ;
     RECT  11.568 64.355 11.592 65.027 ;
     RECT  20.976 64.357 21 65.027 ;
     RECT  31.248 64.549 32.808 65.027 ;
     RECT  38.928 64.595 38.952 65.171 ;
     RECT  13.2 64.355 13.512 65.173 ;
     RECT  2.4 64.979 5.832 65.269 ;
     RECT  16.416 64.451 16.584 65.315 ;
     RECT  7.584 64.741 8.112 65.509 ;
     RECT  9.264 64.067 9.288 65.509 ;
     RECT  10.56 57.107 10.584 65.509 ;
     RECT  26.544 63.299 26.568 65.509 ;
     RECT  27.744 64.933 28.344 65.509 ;
     RECT  7.584 65.509 9.288 65.603 ;
     RECT  2.4 65.269 6.264 66.227 ;
     RECT  16.56 65.315 16.584 66.613 ;
     RECT  7.8 65.603 9.288 66.661 ;
     RECT  26.544 65.509 28.344 66.755 ;
     RECT  37.104 63.637 37.128 66.755 ;
     RECT  13.2 65.173 14.088 66.899 ;
     RECT  31.536 65.027 32.808 67.141 ;
     RECT  16.56 66.613 16.632 67.283 ;
     RECT  2.4 66.227 5.832 67.331 ;
     RECT  16.56 67.283 16.584 67.429 ;
     RECT  16.464 67.429 16.584 67.475 ;
     RECT  29.4 61.619 29.712 67.477 ;
     RECT  10.56 65.509 10.776 67.717 ;
     RECT  26.976 66.755 28.344 67.717 ;
     RECT  10.56 67.717 10.824 67.763 ;
     RECT  34.56 64.885 35.112 67.813 ;
     RECT  26.016 67.717 28.344 67.859 ;
     RECT  31.296 67.141 32.808 67.859 ;
     RECT  38.4 66.613 38.424 67.859 ;
     RECT  6.864 66.661 9.288 67.909 ;
     RECT  27.072 67.859 28.344 68.101 ;
     RECT  29.4 67.477 29.832 68.101 ;
     RECT  27.072 68.101 29.832 68.147 ;
     RECT  31.296 67.859 32.424 68.339 ;
     RECT  26.016 67.859 26.04 68.341 ;
     RECT  25.68 68.341 26.04 68.387 ;
     RECT  31.536 68.339 32.424 68.435 ;
     RECT  21.072 67.765 21.096 68.773 ;
     RECT  22.368 63.347 24.312 68.773 ;
     RECT  40.2 64.595 40.512 68.773 ;
     RECT  16.464 67.475 16.488 68.917 ;
     RECT  32.4 68.435 32.424 68.917 ;
     RECT  19.92 68.773 19.944 69.587 ;
     RECT  25.68 68.387 25.704 69.587 ;
     RECT  16.08 68.917 16.488 69.971 ;
     RECT  21.072 68.773 24.312 69.971 ;
     RECT  27.072 68.147 29.712 69.973 ;
     RECT  32.4 68.917 32.904 70.019 ;
     RECT  21.072 69.971 22.68 70.163 ;
     RECT  27.072 69.973 29.832 70.163 ;
     RECT  27.072 70.163 27.24 70.261 ;
     RECT  6.864 67.909 9.384 70.405 ;
     RECT  34.032 67.813 35.112 70.549 ;
     RECT  36.336 68.341 36.36 70.645 ;
     RECT  36.336 70.645 36.504 70.691 ;
     RECT  16.464 69.971 16.488 70.693 ;
     RECT  23.904 69.971 24.312 70.739 ;
     RECT  28.32 70.163 29.832 70.739 ;
     RECT  34.032 70.549 35.304 70.933 ;
     RECT  26.16 70.261 27.24 71.315 ;
     RECT  36.48 70.691 36.504 71.315 ;
     RECT  39.84 68.773 40.512 71.315 ;
     RECT  26.16 71.315 27.192 71.363 ;
     RECT  24 70.739 24.312 71.653 ;
     RECT  29.4 70.739 29.832 71.797 ;
     RECT  32.4 70.019 32.424 71.797 ;
     RECT  16.464 70.693 16.536 71.843 ;
     RECT  32.4 71.797 32.52 71.939 ;
     RECT  34.032 70.933 35.352 72.035 ;
     RECT  10.752 67.763 10.824 72.179 ;
     RECT  32.496 71.939 32.52 72.229 ;
     RECT  18.6 62.579 18.912 72.277 ;
     RECT  21.456 70.163 22.68 72.707 ;
     RECT  24 71.653 24.984 72.851 ;
     RECT  29.4 71.797 29.976 72.947 ;
     RECT  32.496 72.229 32.808 72.947 ;
     RECT  18.6 72.277 19.608 72.995 ;
     RECT  24 72.851 24.504 73.571 ;
     RECT  27.072 71.363 27.192 73.957 ;
     RECT  31.008 72.901 31.032 73.957 ;
     RECT  26.784 73.957 27.192 74.051 ;
     RECT  22.368 72.707 22.68 74.101 ;
     RECT  24 73.571 24.312 74.101 ;
     RECT  16.464 71.843 16.488 74.147 ;
     RECT  34.032 72.035 35.112 74.291 ;
     RECT  39.072 72.901 39.096 74.291 ;
     RECT  18.6 72.995 18.912 74.485 ;
     RECT  15.072 66.373 15.096 74.581 ;
     RECT  31.008 73.957 31.32 74.581 ;
     RECT  22.368 74.101 24.312 74.723 ;
     RECT  30.768 74.581 31.32 74.723 ;
     RECT  28.32 70.739 28.344 75.205 ;
     RECT  29.4 72.947 29.712 75.205 ;
     RECT  34.8 74.291 35.112 75.205 ;
     RECT  31.296 74.723 31.32 75.349 ;
     RECT  31.296 75.349 31.56 75.395 ;
     RECT  32.784 72.947 32.808 75.541 ;
     RECT  10.752 72.179 10.776 75.781 ;
     RECT  24 74.723 24.312 75.781 ;
     RECT  37.584 73.477 37.608 75.827 ;
     RECT  26.784 74.051 27.096 75.875 ;
     RECT  15.072 74.581 16.008 75.923 ;
     RECT  6.864 70.405 9.48 76.067 ;
     RECT  25.68 75.541 25.704 76.403 ;
     RECT  34.8 75.205 35.4 76.739 ;
     RECT  17.808 74.485 18.912 76.885 ;
     RECT  31.536 75.395 31.56 76.979 ;
     RECT  23.856 75.781 24.312 77.027 ;
     RECT  7.8 76.067 9.48 77.221 ;
     RECT  15.072 75.923 15.096 77.221 ;
     RECT  16.176 76.357 16.2 77.221 ;
     RECT  15.072 77.221 16.2 77.267 ;
     RECT  22.368 74.723 22.68 77.269 ;
     RECT  7.8 77.221 9.576 77.555 ;
     RECT  10.752 75.781 11.736 77.555 ;
     RECT  15.072 77.267 15.528 77.555 ;
     RECT  36.48 75.109 36.504 77.603 ;
     RECT  32.784 75.541 32.904 77.701 ;
     RECT  22.368 77.269 22.776 77.939 ;
     RECT  27.072 75.875 27.096 78.037 ;
     RECT  17.808 76.885 19.368 78.131 ;
     RECT  31.872 77.701 32.904 78.131 ;
     RECT  27.072 78.037 27.288 78.613 ;
     RECT  40.2 71.315 40.512 78.613 ;
     RECT  10.752 77.555 10.776 78.661 ;
     RECT  10.752 78.661 10.968 78.803 ;
     RECT  22.368 77.939 22.392 78.901 ;
     RECT  34.8 76.739 35.112 79.045 ;
     RECT  39.6 78.613 40.512 79.187 ;
     RECT  2.4 67.331 4.728 79.237 ;
     RECT  20.496 78.517 20.52 79.331 ;
     RECT  31.872 78.131 32.808 79.475 ;
     RECT  22.224 78.901 22.392 79.621 ;
     RECT  24 77.027 24.312 79.765 ;
     RECT  26.832 78.613 27.288 79.813 ;
     RECT  28.32 75.205 29.712 79.813 ;
     RECT  26.832 79.813 29.712 79.859 ;
     RECT  7.8 77.555 9.48 80.101 ;
     RECT  10.752 78.803 10.776 80.101 ;
     RECT  26.832 79.859 28.344 80.147 ;
     RECT  34.224 79.045 35.112 80.245 ;
     RECT  2.304 79.237 4.728 80.291 ;
     RECT  7.8 80.101 10.776 80.291 ;
     RECT  34.224 80.245 35.352 80.291 ;
     RECT  2.4 80.291 4.728 80.387 ;
     RECT  32.4 79.475 32.808 80.483 ;
     RECT  21.6 79.621 22.392 80.677 ;
     RECT  9.36 80.291 10.776 81.011 ;
     RECT  17.808 78.131 18.912 81.445 ;
     RECT  2.4 80.387 4.536 81.539 ;
     RECT  38.688 80.917 38.712 81.539 ;
     RECT  9.456 81.011 10.776 81.587 ;
     RECT  34.8 80.291 35.352 81.589 ;
     RECT  9.456 81.587 9.528 81.683 ;
     RECT  34.8 81.589 35.4 82.069 ;
     RECT  31.296 81.445 31.32 82.163 ;
     RECT  24 79.765 24.648 82.211 ;
     RECT  29.4 79.859 29.712 82.597 ;
     RECT  2.4 81.539 4.44 82.645 ;
     RECT  17.808 81.445 19.416 82.645 ;
     RECT  9.504 81.683 9.528 82.691 ;
     RECT  34.032 82.069 35.4 82.979 ;
     RECT  21.6 80.677 22.536 83.077 ;
     RECT  34.8 82.979 35.4 83.171 ;
     RECT  24 82.211 24.312 83.221 ;
     RECT  32.784 80.483 32.808 83.221 ;
     RECT  17.808 82.645 19.752 83.267 ;
     RECT  16.8 80.917 16.824 83.365 ;
     RECT  13.2 66.899 13.512 83.605 ;
     RECT  24 83.221 24.456 83.747 ;
     RECT  7.8 80.291 8.112 84.133 ;
     RECT  9.12 83.749 9.144 84.133 ;
     RECT  21.6 83.077 22.68 84.275 ;
     RECT  7.8 84.133 9.144 84.563 ;
     RECT  32.064 83.221 32.808 84.803 ;
     RECT  26.928 80.147 28.344 84.853 ;
     RECT  29.4 82.597 30.6 84.853 ;
     RECT  10.752 81.587 10.776 84.901 ;
     RECT  17.808 83.267 18.912 84.901 ;
     RECT  16.512 83.365 16.824 84.947 ;
     RECT  5.808 67.331 5.832 84.995 ;
     RECT  32.448 84.803 32.808 85.091 ;
     RECT  22.512 84.275 22.68 85.139 ;
     RECT  26.928 84.853 30.6 85.139 ;
     RECT  10.08 84.901 10.776 85.427 ;
     RECT  26.928 85.139 29.712 85.429 ;
     RECT  34.8 83.171 35.208 85.477 ;
     RECT  26.112 85.429 29.712 85.523 ;
     RECT  24 83.747 24.408 85.715 ;
     RECT  28.32 85.523 29.712 85.715 ;
     RECT  38.736 84.853 38.76 85.811 ;
     RECT  13.056 83.605 13.512 86.005 ;
     RECT  15.072 77.555 15.096 86.005 ;
     RECT  2.4 82.645 4.536 86.051 ;
     RECT  22.656 85.139 22.68 86.053 ;
     RECT  24 85.715 24.312 86.053 ;
     RECT  17.808 84.901 19.848 86.149 ;
     RECT  7.8 84.563 8.616 86.437 ;
     RECT  32.448 85.091 32.52 86.437 ;
     RECT  2.4 86.051 4.44 86.675 ;
     RECT  22.656 86.053 24.312 86.675 ;
     RECT  13.056 86.005 15.096 86.771 ;
     RECT  24 86.675 24.312 86.917 ;
     RECT  32.304 86.437 32.52 86.917 ;
     RECT  24 86.917 24.648 87.109 ;
     RECT  26.112 85.523 27.288 87.203 ;
     RECT  32.304 86.917 33.048 87.251 ;
     RECT  6.288 87.157 6.312 87.731 ;
     RECT  17.808 86.149 20.232 87.731 ;
     RECT  7.68 86.437 8.616 87.827 ;
     RECT  28.32 85.715 28.344 87.827 ;
     RECT  16.8 84.947 16.824 88.067 ;
     RECT  37.584 85.429 37.608 88.067 ;
     RECT  24 87.109 24.84 88.117 ;
     RECT  34.8 85.477 36.168 88.211 ;
     RECT  26.928 87.203 27.288 88.403 ;
     RECT  22.656 86.675 22.68 88.741 ;
     RECT  10.752 85.427 10.776 88.885 ;
     RECT  29.4 85.715 29.712 88.933 ;
     RECT  28.512 88.933 29.712 88.981 ;
     RECT  17.808 87.731 19.608 89.123 ;
     RECT  13.2 86.771 15.096 89.317 ;
     RECT  33.024 87.251 33.048 89.413 ;
     RECT  24 88.117 25.08 89.461 ;
     RECT  7.8 87.827 8.616 89.509 ;
     RECT  13.056 89.317 15.096 89.699 ;
     RECT  7.8 89.509 8.712 89.747 ;
     RECT  21.072 88.885 21.096 89.845 ;
     RECT  27.264 88.403 27.288 89.845 ;
     RECT  28.512 88.981 30.024 89.845 ;
     RECT  20.976 89.845 21.096 89.891 ;
     RECT  2.4 86.675 4.296 90.083 ;
     RECT  27.264 89.845 30.024 90.227 ;
     RECT  13.056 89.699 14.232 90.563 ;
     RECT  22.224 88.741 22.68 90.563 ;
     RECT  32.448 89.413 33.048 90.613 ;
     RECT  22.224 90.563 22.248 90.659 ;
     RECT  24 89.461 25.656 90.755 ;
     RECT  9.936 88.885 10.776 90.851 ;
     RECT  32.448 90.613 33.144 90.947 ;
     RECT  7.8 89.747 8.112 91.141 ;
     RECT  33.12 90.947 33.144 91.285 ;
     RECT  24 90.755 24.84 91.717 ;
     RECT  7.8 91.141 8.856 91.763 ;
     RECT  38.592 88.885 38.616 91.859 ;
     RECT  10.08 90.851 10.776 92.387 ;
     RECT  2.4 90.083 2.712 92.533 ;
     RECT  3.696 90.083 4.296 92.533 ;
     RECT  29.4 90.227 29.712 92.629 ;
     RECT  24 91.717 25.272 92.675 ;
     RECT  18.6 89.123 19.608 92.677 ;
     RECT  27.6 90.227 27.624 92.869 ;
     RECT  36.144 88.211 36.168 92.869 ;
     RECT  2.4 92.533 4.296 92.963 ;
     RECT  27.312 92.869 27.624 92.963 ;
     RECT  33.12 91.285 33.816 93.107 ;
     RECT  13.2 90.563 14.232 93.203 ;
     RECT  22.8 92.293 22.824 93.491 ;
     RECT  11.952 92.485 11.976 93.541 ;
     RECT  20.976 89.891 21 93.779 ;
     RECT  6.384 92.101 6.408 94.019 ;
     RECT  27.312 92.963 27.336 94.019 ;
     RECT  10.464 92.387 10.776 94.021 ;
     RECT  40.2 79.187 40.512 94.021 ;
     RECT  10.224 94.021 10.776 94.069 ;
     RECT  11.856 93.541 11.976 94.261 ;
     RECT  13.2 93.203 14.136 94.261 ;
     RECT  36.144 92.869 36.744 94.261 ;
     RECT  10.224 94.069 10.872 94.405 ;
     RECT  34.8 88.211 35.112 94.405 ;
     RECT  29.136 92.629 29.712 94.547 ;
     RECT  2.4 92.963 3.672 94.549 ;
     RECT  9.984 94.405 10.872 94.549 ;
     RECT  11.856 94.261 14.136 94.549 ;
     RECT  24 92.675 24.84 94.691 ;
     RECT  18.6 92.677 19.992 95.077 ;
     RECT  39.456 94.021 40.512 95.125 ;
     RECT  9.984 94.549 14.136 95.221 ;
     RECT  18.6 95.077 20.568 95.411 ;
     RECT  36.144 94.261 36.984 95.459 ;
     RECT  29.28 94.547 29.712 95.507 ;
     RECT  33.12 93.107 33.144 95.653 ;
     RECT  39.36 95.125 40.512 95.701 ;
     RECT  39.024 95.701 40.512 95.795 ;
     RECT  2.4 94.549 4.488 96.179 ;
     RECT  9.744 95.221 14.136 96.277 ;
     RECT  33.072 95.653 33.144 96.371 ;
     RECT  9.408 96.277 14.136 96.661 ;
     RECT  2.4 96.179 3.672 96.707 ;
     RECT  16.752 94.021 16.776 96.707 ;
     RECT  7.8 91.763 8.112 96.757 ;
     RECT  9.408 96.661 14.424 96.757 ;
     RECT  18.6 95.411 18.912 96.853 ;
     RECT  28.032 94.981 28.056 96.899 ;
     RECT  39.024 95.795 39.048 96.995 ;
     RECT  29.4 95.507 29.712 97.141 ;
     RECT  22.8 96.277 22.824 97.523 ;
     RECT  7.8 96.757 14.424 97.525 ;
     RECT  34.704 94.405 35.112 97.525 ;
     RECT  21.744 96.277 21.768 97.571 ;
     RECT  33.12 96.371 33.144 97.571 ;
     RECT  6.864 97.525 14.424 97.667 ;
     RECT  18.6 96.853 19.128 97.763 ;
     RECT  4.464 97.381 4.488 98.099 ;
     RECT  7.8 97.667 14.424 98.099 ;
     RECT  6.192 97.765 6.216 98.197 ;
     RECT  29.4 97.141 30.264 98.435 ;
     RECT  5.472 98.197 6.216 98.629 ;
     RECT  16.512 97.909 16.536 98.675 ;
     RECT  38.88 98.485 38.904 98.675 ;
     RECT  5.472 98.629 6.36 98.771 ;
     RECT  7.8 98.099 14.136 98.965 ;
     RECT  7.68 98.965 14.136 99.157 ;
     RECT  18.6 97.763 18.912 99.157 ;
     RECT  5.472 98.771 5.88 99.443 ;
     RECT  36.432 95.459 36.984 99.443 ;
     RECT  7.632 99.157 14.136 99.685 ;
     RECT  18.6 99.157 19.032 99.685 ;
     RECT  30.72 98.485 31.704 99.685 ;
     RECT  34.272 97.525 35.112 99.779 ;
     RECT  24 94.691 24.552 100.163 ;
     RECT  7.632 99.685 14.856 100.211 ;
     RECT  25.536 99.157 25.56 100.259 ;
     RECT  17.616 99.685 19.032 100.355 ;
     RECT  21.696 99.157 21.72 100.355 ;
     RECT  20.544 95.411 20.568 100.453 ;
     RECT  5.856 99.443 5.88 100.499 ;
     RECT  20.544 100.453 21.144 100.499 ;
     RECT  7.632 100.211 14.136 100.597 ;
     RECT  36.432 99.443 36.456 100.645 ;
     RECT  30.72 99.685 32.52 100.787 ;
     RECT  34.608 99.779 35.112 100.789 ;
     RECT  2.4 96.707 3.096 100.931 ;
     RECT  20.976 100.499 21.144 101.075 ;
     RECT  36.432 100.645 37.032 101.075 ;
     RECT  27.984 100.069 28.008 101.507 ;
     RECT  31.632 100.787 32.52 101.507 ;
     RECT  7.44 100.597 14.136 101.603 ;
     RECT  34.272 100.789 35.112 101.747 ;
     RECT  29.4 98.435 29.712 101.989 ;
     RECT  24 100.163 24.312 102.037 ;
     RECT  21.12 101.075 21.144 102.131 ;
     RECT  7.44 101.603 13.512 102.133 ;
     RECT  6.96 102.133 13.512 102.613 ;
     RECT  6.864 102.613 13.512 102.659 ;
     RECT  32.496 101.507 32.52 102.659 ;
     RECT  6.864 102.659 12.216 102.803 ;
     RECT  6.96 102.803 12.216 102.899 ;
     RECT  28.512 101.989 30.408 103.187 ;
     RECT  22.896 101.413 22.92 103.235 ;
     RECT  24 102.037 24.792 103.235 ;
     RECT  29.4 103.187 30.408 103.235 ;
     RECT  37.008 101.075 37.032 103.235 ;
     RECT  7.8 102.899 12.216 103.283 ;
     RECT  11.472 103.283 12.216 103.331 ;
     RECT  2.4 100.931 2.712 103.689 ;
     RECT  13.2 102.659 13.512 103.689 ;
     RECT  18.6 100.355 18.912 103.689 ;
     RECT  24 103.235 24.312 103.689 ;
     RECT  29.4 103.235 29.712 103.689 ;
     RECT  34.8 101.747 35.112 103.689 ;
     RECT  40.2 95.795 40.512 103.689 ;
     RECT  2.4 103.689 2.52 103.703 ;
     RECT  7.8 103.283 10.488 103.703 ;
     RECT  13.2 103.689 13.32 103.703 ;
     RECT  18.6 103.689 18.72 103.703 ;
     RECT  24 103.689 24.12 103.703 ;
     RECT  29.4 103.689 29.52 103.703 ;
     RECT  34.8 103.689 34.92 103.703 ;
     RECT  40.2 103.689 40.32 103.703 ;
     RECT  8.832 103.703 10.488 104.293 ;
     RECT  12.192 103.331 12.216 104.867 ;
     RECT  8.832 104.293 10.776 104.869 ;
     RECT  8.832 104.869 11.208 104.915 ;
     RECT  9.024 104.915 11.208 105.68 ;
     RECT  9.024 1.763 9.456 2.137 ;
     RECT  7.92 2.137 9.456 2.151 ;
     RECT  8.112 2.151 9.456 4.261 ;
     RECT  17.448 2.485 18.6 3.299 ;
     RECT  33.432 2.821 34.8 3.397 ;
     RECT  17.616 3.299 18.6 3.925 ;
     RECT  33.432 3.397 34.704 3.443 ;
     RECT  24.312 3.683 24.696 5.029 ;
     RECT  9.624 4.067 10.8 5.653 ;
     RECT  35.112 4.069 36.096 6.851 ;
     RECT  5.4 4.261 6.528 5.029 ;
     RECT  8.112 4.261 9.264 5.077 ;
     RECT  14.232 4.453 15.648 5.077 ;
     RECT  14.232 5.077 15.36 5.699 ;
     RECT  5.952 5.123 6.048 6.277 ;
     RECT  6.072 5.123 7.248 6.851 ;
     RECT  9.672 5.653 10.8 5.701 ;
     RECT  13.656 5.699 13.704 6.805 ;
     RECT  39.936 5.891 39.984 7.237 ;
     RECT  6.072 6.851 6.264 7.237 ;
     RECT  35.112 6.851 36.528 8.437 ;
     RECT  24.312 7.187 24.408 8.341 ;
     RECT  5.952 7.283 6.048 8.485 ;
     RECT  15.36 7.379 15.648 7.717 ;
     RECT  14.28 7.717 15.648 9.589 ;
     RECT  38.808 7.765 39.936 8.867 ;
     RECT  15.816 8.149 17.088 8.291 ;
     RECT  17.112 8.149 18.192 8.291 ;
     RECT  26.76 8.149 28.176 9.013 ;
     RECT  28.2 8.195 29.28 10.453 ;
     RECT  19.32 8.245 20.544 8.723 ;
     RECT  15.816 8.291 18.192 8.389 ;
     RECT  24.312 8.341 25.536 9.731 ;
     RECT  25.56 8.341 26.736 9.731 ;
     RECT  15.816 8.389 17.616 9.061 ;
     RECT  16.152 9.061 17.616 10.837 ;
     RECT  14.328 9.589 15.648 11.171 ;
     RECT  26.76 10.307 28.176 11.941 ;
     RECT  16.584 10.837 17.616 12.035 ;
     RECT  28.2 10.883 29.4 12.949 ;
     RECT  13.512 11.171 13.608 12.517 ;
     RECT  15.36 11.171 15.648 11.413 ;
     RECT  15.36 11.413 15.408 11.845 ;
     RECT  38.904 11.653 39.936 12.467 ;
     RECT  26.808 11.941 28.176 12.563 ;
     RECT  16.584 12.035 16.68 12.517 ;
     RECT  26.76 12.563 28.176 12.995 ;
     RECT  26.76 12.995 27.24 13.957 ;
     RECT  15.36 13.139 15.408 14.581 ;
     RECT  33.24 13.573 34.464 15.349 ;
     RECT  39.936 13.715 40.08 15.061 ;
     RECT  5.688 13.813 7.152 14.291 ;
     RECT  22.872 14.099 24 23.173 ;
     RECT  9.528 14.243 10.512 24.901 ;
     RECT  15.672 14.627 16.656 17.605 ;
     RECT  38.616 15.061 40.08 16.979 ;
     RECT  33.384 15.349 34.464 15.877 ;
     RECT  33.432 15.877 34.464 16.595 ;
     RECT  27.672 15.925 28.8 16.501 ;
     RECT  35.112 16.405 36.24 19.333 ;
     RECT  33.432 16.595 34.8 18.947 ;
     RECT  27.96 16.787 29.4 18.469 ;
     RECT  38.28 16.979 40.08 18.133 ;
     RECT  17.352 16.981 18.6 18.949 ;
     RECT  13.512 17.029 14.544 20.579 ;
     RECT  24.312 17.315 24.408 18.757 ;
     RECT  38.808 18.133 40.08 18.565 ;
     RECT  19.32 18.419 20.544 18.995 ;
     RECT  28.344 18.469 29.4 30.709 ;
     RECT  4.824 18.851 5.904 20.437 ;
     RECT  33.384 18.947 34.8 23.269 ;
     RECT  6.792 19.285 7.8 20.531 ;
     RECT  15.672 19.667 16.656 24.083 ;
     RECT  5.928 20.531 5.976 21.973 ;
     RECT  13.512 20.579 14.832 21.683 ;
     RECT  20.568 20.867 21.096 21.301 ;
     RECT  4.824 21.155 5.904 22.165 ;
     RECT  30.264 21.253 31.296 21.299 ;
     RECT  20.568 21.301 22.272 22.165 ;
     RECT  16.68 21.683 17.856 22.163 ;
     RECT  38.808 21.683 39.888 22.691 ;
     RECT  18.384 22.163 18.48 23.365 ;
     RECT  21.864 22.259 22.848 23.219 ;
     RECT  38.808 22.691 39.936 22.979 ;
     RECT  4.632 22.787 5.712 22.835 ;
     RECT  4.632 22.835 5.952 24.563 ;
     RECT  21.864 23.219 23.04 23.315 ;
     RECT  5.088 24.563 5.952 25.861 ;
     RECT  15.12 24.563 15.6 24.661 ;
     RECT  14.28 24.661 15.6 26.483 ;
     RECT  19.464 24.901 20.592 26.819 ;
     RECT  30.168 25.091 30.264 26.485 ;
     RECT  13.512 26.483 13.608 27.637 ;
     RECT  5.112 26.819 5.784 27.107 ;
     RECT  26.472 26.963 27.648 30.757 ;
     RECT  5.76 27.107 5.784 27.781 ;
     RECT  22.008 28.453 23.04 29.029 ;
     RECT  38.856 28.453 40.2 31.379 ;
     RECT  22.776 29.123 24 29.795 ;
     RECT  29.712 29.219 30.168 29.605 ;
     RECT  29.712 29.605 31.2 31.043 ;
     RECT  24.312 29.653 25.392 30.563 ;
     RECT  25.416 29.653 26.448 30.563 ;
     RECT  22.68 29.795 24 36.421 ;
     RECT  24.312 30.563 26.448 30.709 ;
     RECT  24.312 30.709 25.344 30.757 ;
     RECT  25.368 30.709 26.448 31.379 ;
     RECT  26.472 30.899 27.648 33.683 ;
     RECT  5.592 30.995 5.688 31.907 ;
     RECT  24.312 30.995 25.344 31.379 ;
     RECT  29.712 31.043 31.776 32.485 ;
     RECT  5.568 31.907 5.688 32.341 ;
     RECT  31.8 32.197 33.312 34.643 ;
     RECT  5.568 32.341 5.664 33.013 ;
     RECT  29.712 32.485 31.104 34.355 ;
     RECT  10.536 32.579 11.664 34.693 ;
     RECT  33.336 33.059 34.8 38.677 ;
     RECT  26.448 33.683 27.648 34.117 ;
     RECT  8.664 33.827 9.696 34.835 ;
     RECT  25.032 34.117 27.648 34.741 ;
     RECT  14.232 34.597 15.312 34.787 ;
     RECT  10.536 34.693 11.52 35.317 ;
     RECT  3.384 34.741 4.896 35.411 ;
     RECT  25.032 34.741 26.496 35.027 ;
     RECT  26.52 34.741 27.648 35.027 ;
     RECT  14.232 34.787 15.552 35.987 ;
     RECT  38.76 34.789 40.2 35.987 ;
     RECT  8.664 34.835 10.224 35.893 ;
     RECT  25.032 35.027 27.648 35.077 ;
     RECT  25.032 35.077 26.448 36.467 ;
     RECT  26.472 35.077 27.648 36.467 ;
     RECT  35.688 35.269 37.008 35.939 ;
     RECT  3.24 35.411 4.896 36.661 ;
     RECT  22.824 36.421 24 37.043 ;
     RECT  25.032 36.467 25.944 37.237 ;
     RECT  8.616 36.515 9.6 40.067 ;
     RECT  11.496 36.515 12.96 38.819 ;
     RECT  22.68 37.043 24 38.677 ;
     RECT  24.312 37.283 25.92 38.147 ;
     RECT  35.112 37.523 36.288 38.771 ;
     RECT  24.312 38.147 24.456 38.677 ;
     RECT  22.872 38.677 24 39.349 ;
     RECT  33.672 38.677 34.8 39.347 ;
     RECT  11.448 38.819 12.96 41.075 ;
     RECT  15.624 38.819 16.848 40.453 ;
     RECT  4.392 39.203 5.808 40.885 ;
     RECT  33.48 39.347 34.8 43.379 ;
     RECT  22.968 39.349 24 39.491 ;
     RECT  22.68 39.491 24 50.533 ;
     RECT  8.52 40.067 9.6 40.835 ;
     RECT  15.768 40.453 16.848 41.027 ;
     RECT  28.224 40.499 28.32 41.557 ;
     RECT  8.232 40.835 9.6 41.509 ;
     RECT  4.728 40.885 5.808 42.709 ;
     RECT  14.232 40.981 15.552 41.123 ;
     RECT  15.624 41.027 16.848 42.709 ;
     RECT  8.232 41.509 9.456 41.891 ;
     RECT  29.712 41.651 29.832 43.141 ;
     RECT  8.112 41.891 9.456 41.893 ;
     RECT  8.112 41.893 9.36 47.747 ;
     RECT  33.072 41.939 33.456 43.333 ;
     RECT  19.128 41.989 20.16 45.155 ;
     RECT  5.832 42.133 6.864 44.483 ;
     RECT  35.112 42.227 35.208 43.285 ;
     RECT  11.064 42.709 12.576 43.859 ;
     RECT  24.504 42.709 25.488 43.139 ;
     RECT  24.312 43.139 25.488 45.685 ;
     RECT  20.664 43.333 21.888 44.579 ;
     RECT  35.208 43.861 36.432 45.971 ;
     RECT  25.512 44.101 26.832 45.925 ;
     RECT  26.856 44.101 28.32 46.787 ;
     RECT  4.776 44.339 5.808 45.731 ;
     RECT  20.184 44.579 21.888 45.155 ;
     RECT  15.624 44.627 16.848 45.443 ;
     RECT  20.928 45.155 21.888 45.877 ;
     RECT  15.576 45.443 16.848 47.845 ;
     RECT  29.712 45.635 31.056 46.885 ;
     RECT  24.408 45.685 25.488 45.971 ;
     RECT  4.728 45.731 5.808 46.741 ;
     RECT  35.208 45.971 35.88 46.645 ;
     RECT  31.944 46.645 33.072 46.883 ;
     RECT  27.552 46.787 28.32 47.749 ;
     RECT  13.656 46.789 14.736 46.931 ;
     RECT  28.344 48.083 29.4 52.405 ;
     RECT  27.552 48.467 28.32 48.949 ;
     RECT  35.88 48.901 37.008 48.947 ;
     RECT  26.424 48.949 28.32 49.525 ;
     RECT  31.944 49.477 32.928 50.147 ;
     RECT  29.712 49.523 30.912 51.395 ;
     RECT  26.424 49.525 27.6 52.403 ;
     RECT  8.376 50.005 9.888 50.195 ;
     RECT  38.904 50.101 40.2 51.253 ;
     RECT  23.016 50.533 24 50.629 ;
     RECT  8.112 50.771 8.376 51.877 ;
     RECT  29.712 51.395 31.056 52.499 ;
     RECT  8.952 51.877 10.272 54.179 ;
     RECT  15.72 51.923 16.752 51.971 ;
     RECT  15.72 51.971 16.44 52.981 ;
     RECT  22.68 52.115 24 56.725 ;
     RECT  29.712 52.499 31.248 52.981 ;
     RECT  28.344 52.931 29.4 54.085 ;
     RECT  30.024 52.981 31.248 54.131 ;
     RECT  33.336 52.981 34.8 54.131 ;
     RECT  35.112 53.557 36.432 55.573 ;
     RECT  26.952 54.085 28.32 55.907 ;
     RECT  8.952 54.179 11.04 55.237 ;
     RECT  13.512 54.467 13.608 55.813 ;
     RECT  6.696 54.709 7.8 55.283 ;
     RECT  9.72 55.237 11.04 57.013 ;
     RECT  13.512 55.813 14.832 57.107 ;
     RECT  16.44 55.813 17.616 56.483 ;
     RECT  28.176 55.907 28.32 56.389 ;
     RECT  28.344 56.387 29.4 59.797 ;
     RECT  22.68 56.725 23.904 56.867 ;
     RECT  22.68 56.867 24 63.253 ;
     RECT  31.272 57.445 32.304 64.549 ;
     RECT  5.832 58.117 7.248 61.763 ;
     RECT  16.368 59.363 16.416 60.517 ;
     RECT  9.144 60.133 10.56 62.725 ;
     RECT  39.264 60.179 40.2 61.477 ;
     RECT  8.112 60.275 9.12 64.067 ;
     RECT  32.808 61.091 33.048 61.525 ;
     RECT  25.128 61.189 26.544 62.053 ;
     RECT  32.808 61.525 34.224 62.435 ;
     RECT  28.344 61.619 29.4 68.101 ;
     RECT  25.128 62.053 26.208 62.099 ;
     RECT  9.288 62.725 10.56 67.763 ;
     RECT  7.68 63.299 7.8 64.741 ;
     RECT  21.288 63.347 22.368 64.019 ;
     RECT  10.584 63.685 11.568 65.027 ;
     RECT  21.264 64.019 22.368 64.357 ;
     RECT  8.112 64.067 9.264 65.509 ;
     RECT  21 64.357 22.368 65.027 ;
     RECT  38.952 64.595 40.2 65.171 ;
     RECT  26.568 64.933 27.744 65.509 ;
     RECT  10.584 65.027 10.776 65.509 ;
     RECT  6.264 65.269 7.584 65.603 ;
     RECT  16.416 65.315 16.56 66.373 ;
     RECT  6.264 65.603 7.8 66.227 ;
     RECT  5.832 66.227 7.8 66.661 ;
     RECT  14.088 66.373 15.072 66.899 ;
     RECT  15.096 66.373 16.56 67.429 ;
     RECT  37.128 66.613 38.4 66.755 ;
     RECT  5.832 66.661 6.864 76.067 ;
     RECT  26.544 66.755 26.976 67.717 ;
     RECT  4.728 67.331 5.808 80.387 ;
     RECT  15.096 67.429 16.464 68.917 ;
     RECT  29.832 67.477 31.296 68.147 ;
     RECT  9.288 67.763 10.752 67.909 ;
     RECT  21.096 67.765 22.368 68.773 ;
     RECT  32.808 67.813 34.032 67.859 ;
     RECT  26.04 67.859 27.072 68.387 ;
     RECT  32.424 67.859 34.032 68.917 ;
     RECT  9.384 67.909 10.752 70.405 ;
     RECT  24.312 68.341 25.68 69.587 ;
     RECT  35.112 68.341 36.336 70.549 ;
     RECT  25.704 68.387 27.072 69.587 ;
     RECT  18.912 68.773 19.92 69.587 ;
     RECT  19.944 68.773 21.072 69.587 ;
     RECT  15.096 68.917 16.08 69.971 ;
     RECT  32.904 68.917 34.032 70.019 ;
     RECT  26.16 69.587 27.072 70.261 ;
     RECT  15.096 69.971 16.464 74.147 ;
     RECT  22.68 69.971 23.904 70.739 ;
     RECT  27.24 70.163 28.32 71.315 ;
     RECT  9.48 70.405 10.752 77.221 ;
     RECT  35.304 70.549 36.336 70.691 ;
     RECT  35.304 70.691 36.48 70.933 ;
     RECT  22.68 70.739 24 74.101 ;
     RECT  28.344 70.739 29.4 75.205 ;
     RECT  35.352 70.933 36.48 71.315 ;
     RECT  27.192 71.315 28.32 74.051 ;
     RECT  32.52 71.797 34.032 72.229 ;
     RECT  32.4 71.939 32.496 72.901 ;
     RECT  32.808 72.229 34.032 74.291 ;
     RECT  29.976 72.901 31.008 72.947 ;
     RECT  31.032 72.901 32.496 72.947 ;
     RECT  39.096 72.901 40.2 74.291 ;
     RECT  29.712 72.947 31.008 74.581 ;
     RECT  31.032 72.947 32.784 73.957 ;
     RECT  37.608 73.477 39.072 74.291 ;
     RECT  31.32 73.957 32.784 75.349 ;
     RECT  27.096 74.051 28.32 78.037 ;
     RECT  15.096 74.147 16.008 74.581 ;
     RECT  32.808 74.291 32.904 75.541 ;
     RECT  29.712 74.581 30.768 74.723 ;
     RECT  22.68 74.723 24 75.781 ;
     RECT  35.112 75.109 36.48 75.205 ;
     RECT  36.504 75.109 37.584 75.827 ;
     RECT  35.4 75.205 36.48 76.739 ;
     RECT  31.56 75.349 32.784 76.979 ;
     RECT  24.312 75.541 25.68 76.403 ;
     RECT  25.704 75.541 26.784 75.875 ;
     RECT  11.736 75.781 13.2 77.555 ;
     RECT  22.68 75.781 23.856 77.027 ;
     RECT  25.704 75.875 27.072 76.403 ;
     RECT  15.096 75.923 16.008 76.357 ;
     RECT  15.096 76.357 16.176 77.221 ;
     RECT  35.112 76.739 36.48 77.603 ;
     RECT  31.872 76.979 32.784 77.701 ;
     RECT  22.68 77.027 24 77.269 ;
     RECT  9.576 77.221 10.752 77.555 ;
     RECT  22.776 77.269 24 77.939 ;
     RECT  9.48 77.555 10.752 80.101 ;
     RECT  10.776 77.555 10.968 78.661 ;
     RECT  27.288 78.037 28.32 79.813 ;
     RECT  32.808 78.131 32.904 79.045 ;
     RECT  32.808 79.045 34.224 80.291 ;
     RECT  28.344 79.859 29.4 84.853 ;
     RECT  8.112 80.291 9.36 81.011 ;
     RECT  4.536 80.387 5.808 81.539 ;
     RECT  32.4 80.483 32.784 81.445 ;
     RECT  22.536 80.677 24 83.077 ;
     RECT  16.824 80.917 17.808 88.067 ;
     RECT  38.712 80.917 40.2 81.539 ;
     RECT  8.112 81.011 9.456 81.683 ;
     RECT  31.32 81.445 32.784 82.163 ;
     RECT  4.44 81.539 5.808 82.645 ;
     RECT  9.528 81.587 10.752 82.691 ;
     RECT  8.112 81.683 9.504 82.691 ;
     RECT  32.808 82.069 34.032 82.979 ;
     RECT  31.296 82.163 32.784 82.597 ;
     RECT  24.312 82.211 24.456 83.221 ;
     RECT  30.6 82.597 32.784 83.221 ;
     RECT  4.536 82.645 5.808 84.995 ;
     RECT  8.112 82.691 9.144 83.749 ;
     RECT  22.68 83.077 24 86.053 ;
     RECT  30.6 83.221 32.064 84.803 ;
     RECT  15.096 83.365 16.512 84.947 ;
     RECT  8.112 83.749 9.12 84.133 ;
     RECT  8.616 84.563 9.144 84.901 ;
     RECT  38.76 84.853 40.2 85.811 ;
     RECT  8.616 84.901 10.08 85.427 ;
     RECT  37.608 85.429 38.736 85.811 ;
     RECT  36.168 85.477 37.584 88.067 ;
     RECT  27.288 85.523 28.32 87.827 ;
     RECT  24.312 85.715 24.408 86.917 ;
     RECT  28.344 85.715 29.4 87.827 ;
     RECT  22.68 86.675 24 90.563 ;
     RECT  24.648 86.917 26.112 87.109 ;
     RECT  24.84 87.109 26.112 87.203 ;
     RECT  6.312 87.157 7.68 87.731 ;
     RECT  24.84 87.203 25.08 88.117 ;
     RECT  19.608 87.731 20.232 88.885 ;
     RECT  27.288 87.827 29.4 88.933 ;
     RECT  35.112 88.211 36.144 95.459 ;
     RECT  8.616 88.885 9.936 89.509 ;
     RECT  19.608 88.885 21.072 89.845 ;
     RECT  21.096 88.885 22.224 89.891 ;
     RECT  27.288 88.933 28.512 89.845 ;
     RECT  8.712 89.509 9.936 89.747 ;
     RECT  8.112 89.747 9.936 90.851 ;
     RECT  19.608 89.845 20.976 92.677 ;
     RECT  21 89.891 22.224 90.659 ;
     RECT  2.712 90.083 3.696 92.533 ;
     RECT  24.84 90.755 25.272 91.717 ;
     RECT  8.112 90.851 10.08 91.141 ;
     RECT  8.856 91.141 10.08 91.763 ;
     RECT  33.816 91.285 34.8 93.107 ;
     RECT  6.408 92.101 7.8 94.019 ;
     RECT  22.824 92.293 24 93.491 ;
     RECT  10.776 92.485 11.952 93.541 ;
     RECT  11.976 92.485 13.2 94.261 ;
     RECT  27.624 92.629 29.136 92.963 ;
     RECT  19.992 92.677 20.976 93.779 ;
     RECT  34.704 93.107 34.8 94.405 ;
     RECT  10.776 93.541 11.856 94.069 ;
     RECT  19.992 93.779 20.568 95.077 ;
     RECT  10.872 94.069 11.856 94.549 ;
     RECT  29.136 94.547 29.28 94.981 ;
     RECT  28.056 94.981 29.28 95.507 ;
     RECT  18.912 95.411 20.544 96.853 ;
     RECT  35.112 95.459 36.432 101.075 ;
     RECT  28.056 95.507 29.4 96.899 ;
     RECT  39.048 95.795 40.2 96.995 ;
     RECT  3.672 96.179 4.488 96.707 ;
     RECT  8.112 96.277 9.408 96.757 ;
     RECT  20.568 96.277 21.744 97.571 ;
     RECT  21.768 96.277 22.8 97.523 ;
     RECT  22.824 96.277 24 97.523 ;
     RECT  3.096 96.707 4.488 97.381 ;
     RECT  19.128 96.853 20.544 97.763 ;
     RECT  39.024 96.995 40.2 98.485 ;
     RECT  3.096 97.381 4.464 98.099 ;
     RECT  33.144 97.525 34.272 97.571 ;
     RECT  6.864 97.667 7.8 97.765 ;
     RECT  18.912 97.763 20.544 99.157 ;
     RECT  6.216 97.765 7.8 98.629 ;
     RECT  29.712 98.435 30.264 98.485 ;
     RECT  29.712 98.485 30.72 100.787 ;
     RECT  38.904 98.485 40.2 98.675 ;
     RECT  6.36 98.629 7.8 98.771 ;
     RECT  7.632 98.771 7.8 98.965 ;
     RECT  7.632 98.965 7.68 99.157 ;
     RECT  19.032 99.157 20.544 100.355 ;
     RECT  20.568 99.157 21.696 100.355 ;
     RECT  24.552 99.157 25.536 100.163 ;
     RECT  36.456 99.443 36.984 100.645 ;
     RECT  34.272 99.779 34.608 100.789 ;
     RECT  28.008 100.069 29.4 101.507 ;
     RECT  24.312 100.163 25.536 100.259 ;
     RECT  20.568 100.355 21.144 100.453 ;
     RECT  29.712 100.787 31.632 101.507 ;
     RECT  22.92 101.413 24 103.235 ;
     RECT  28.512 101.507 29.4 101.989 ;
     RECT  29.712 101.507 30.408 101.989 ;
     RECT  12.216 102.659 13.2 103.703 ;
     RECT  10.488 103.283 11.472 103.331 ;
     RECT  10.488 103.331 12.192 104.293 ;
     RECT  10.776 104.293 12.192 104.867 ;
     RECT  10.776 104.867 11.208 104.869 ;
  END
END ot_s81_markov_chunk6_native
END LIBRARY
